VERSION 5.7 ;
BUSBITCHARS "[]" ;
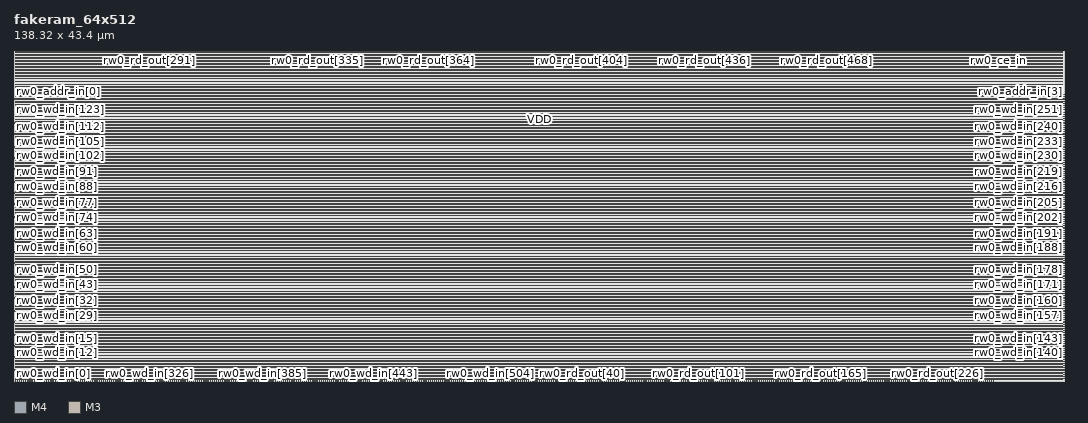
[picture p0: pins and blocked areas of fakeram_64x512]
MACRO fakeram_64x512
  FOREIGN fakeram_64x512 0 0 ;
  SYMMETRY X Y R90 ;
  SIZE 138.320 BY 43.400 ;
  CLASS BLOCK ;
  PIN rw0_wd_in[0]
    DIRECTION INPUT ;
    USE SIGNAL ;
    SHAPE ABUTMENT ;
    PORT
      LAYER M4 ;
      RECT 0.000 0.276 0.072 0.300 ;
    END
  END rw0_wd_in[0]
  PIN rw0_wd_in[1]
    DIRECTION INPUT ;
    USE SIGNAL ;
    SHAPE ABUTMENT ;
    PORT
      LAYER M4 ;
      RECT 0.000 0.564 0.072 0.588 ;
    END
  END rw0_wd_in[1]
  PIN rw0_wd_in[2]
    DIRECTION INPUT ;
    USE SIGNAL ;
    SHAPE ABUTMENT ;
    PORT
      LAYER M4 ;
      RECT 0.000 0.852 0.072 0.876 ;
    END
  END rw0_wd_in[2]
  PIN rw0_wd_in[3]
    DIRECTION INPUT ;
    USE SIGNAL ;
    SHAPE ABUTMENT ;
    PORT
      LAYER M4 ;
      RECT 0.000 1.140 0.072 1.164 ;
    END
  END rw0_wd_in[3]
  PIN rw0_wd_in[4]
    DIRECTION INPUT ;
    USE SIGNAL ;
    SHAPE ABUTMENT ;
    PORT
      LAYER M4 ;
      RECT 0.000 1.428 0.072 1.452 ;
    END
  END rw0_wd_in[4]
  PIN rw0_wd_in[5]
    DIRECTION INPUT ;
    USE SIGNAL ;
    SHAPE ABUTMENT ;
    PORT
      LAYER M4 ;
      RECT 0.000 1.716 0.072 1.740 ;
    END
  END rw0_wd_in[5]
  PIN rw0_wd_in[6]
    DIRECTION INPUT ;
    USE SIGNAL ;
    SHAPE ABUTMENT ;
    PORT
      LAYER M4 ;
      RECT 0.000 2.004 0.072 2.028 ;
    END
  END rw0_wd_in[6]
  PIN rw0_wd_in[7]
    DIRECTION INPUT ;
    USE SIGNAL ;
    SHAPE ABUTMENT ;
    PORT
      LAYER M4 ;
      RECT 0.000 2.292 0.072 2.316 ;
    END
  END rw0_wd_in[7]
  PIN rw0_wd_in[8]
    DIRECTION INPUT ;
    USE SIGNAL ;
    SHAPE ABUTMENT ;
    PORT
      LAYER M4 ;
      RECT 0.000 2.580 0.072 2.604 ;
    END
  END rw0_wd_in[8]
  PIN rw0_wd_in[9]
    DIRECTION INPUT ;
    USE SIGNAL ;
    SHAPE ABUTMENT ;
    PORT
      LAYER M4 ;
      RECT 0.000 2.868 0.072 2.892 ;
    END
  END rw0_wd_in[9]
  PIN rw0_wd_in[10]
    DIRECTION INPUT ;
    USE SIGNAL ;
    SHAPE ABUTMENT ;
    PORT
      LAYER M4 ;
      RECT 0.000 3.156 0.072 3.180 ;
    END
  END rw0_wd_in[10]
  PIN rw0_wd_in[11]
    DIRECTION INPUT ;
    USE SIGNAL ;
    SHAPE ABUTMENT ;
    PORT
      LAYER M4 ;
      RECT 0.000 3.444 0.072 3.468 ;
    END
  END rw0_wd_in[11]
  PIN rw0_wd_in[12]
    DIRECTION INPUT ;
    USE SIGNAL ;
    SHAPE ABUTMENT ;
    PORT
      LAYER M4 ;
      RECT 0.000 3.732 0.072 3.756 ;
    END
  END rw0_wd_in[12]
  PIN rw0_wd_in[13]
    DIRECTION INPUT ;
    USE SIGNAL ;
    SHAPE ABUTMENT ;
    PORT
      LAYER M4 ;
      RECT 0.000 4.020 0.072 4.044 ;
    END
  END rw0_wd_in[13]
  PIN rw0_wd_in[14]
    DIRECTION INPUT ;
    USE SIGNAL ;
    SHAPE ABUTMENT ;
    PORT
      LAYER M4 ;
      RECT 0.000 4.308 0.072 4.332 ;
    END
  END rw0_wd_in[14]
  PIN rw0_wd_in[15]
    DIRECTION INPUT ;
    USE SIGNAL ;
    SHAPE ABUTMENT ;
    PORT
      LAYER M4 ;
      RECT 0.000 4.596 0.072 4.620 ;
    END
  END rw0_wd_in[15]
  PIN rw0_wd_in[16]
    DIRECTION INPUT ;
    USE SIGNAL ;
    SHAPE ABUTMENT ;
    PORT
      LAYER M4 ;
      RECT 0.000 4.884 0.072 4.908 ;
    END
  END rw0_wd_in[16]
  PIN rw0_wd_in[17]
    DIRECTION INPUT ;
    USE SIGNAL ;
    SHAPE ABUTMENT ;
    PORT
      LAYER M4 ;
      RECT 0.000 5.172 0.072 5.196 ;
    END
  END rw0_wd_in[17]
  PIN rw0_wd_in[18]
    DIRECTION INPUT ;
    USE SIGNAL ;
    SHAPE ABUTMENT ;
    PORT
      LAYER M4 ;
      RECT 0.000 5.460 0.072 5.484 ;
    END
  END rw0_wd_in[18]
  PIN rw0_wd_in[19]
    DIRECTION INPUT ;
    USE SIGNAL ;
    SHAPE ABUTMENT ;
    PORT
      LAYER M4 ;
      RECT 0.000 5.748 0.072 5.772 ;
    END
  END rw0_wd_in[19]
  PIN rw0_wd_in[20]
    DIRECTION INPUT ;
    USE SIGNAL ;
    SHAPE ABUTMENT ;
    PORT
      LAYER M4 ;
      RECT 0.000 6.036 0.072 6.060 ;
    END
  END rw0_wd_in[20]
  PIN rw0_wd_in[21]
    DIRECTION INPUT ;
    USE SIGNAL ;
    SHAPE ABUTMENT ;
    PORT
      LAYER M4 ;
      RECT 0.000 6.324 0.072 6.348 ;
    END
  END rw0_wd_in[21]
  PIN rw0_wd_in[22]
    DIRECTION INPUT ;
    USE SIGNAL ;
    SHAPE ABUTMENT ;
    PORT
      LAYER M4 ;
      RECT 0.000 6.612 0.072 6.636 ;
    END
  END rw0_wd_in[22]
  PIN rw0_wd_in[23]
    DIRECTION INPUT ;
    USE SIGNAL ;
    SHAPE ABUTMENT ;
    PORT
      LAYER M4 ;
      RECT 0.000 6.900 0.072 6.924 ;
    END
  END rw0_wd_in[23]
  PIN rw0_wd_in[24]
    DIRECTION INPUT ;
    USE SIGNAL ;
    SHAPE ABUTMENT ;
    PORT
      LAYER M4 ;
      RECT 0.000 7.188 0.072 7.212 ;
    END
  END rw0_wd_in[24]
  PIN rw0_wd_in[25]
    DIRECTION INPUT ;
    USE SIGNAL ;
    SHAPE ABUTMENT ;
    PORT
      LAYER M4 ;
      RECT 0.000 7.476 0.072 7.500 ;
    END
  END rw0_wd_in[25]
  PIN rw0_wd_in[26]
    DIRECTION INPUT ;
    USE SIGNAL ;
    SHAPE ABUTMENT ;
    PORT
      LAYER M4 ;
      RECT 0.000 7.764 0.072 7.788 ;
    END
  END rw0_wd_in[26]
  PIN rw0_wd_in[27]
    DIRECTION INPUT ;
    USE SIGNAL ;
    SHAPE ABUTMENT ;
    PORT
      LAYER M4 ;
      RECT 0.000 8.052 0.072 8.076 ;
    END
  END rw0_wd_in[27]
  PIN rw0_wd_in[28]
    DIRECTION INPUT ;
    USE SIGNAL ;
    SHAPE ABUTMENT ;
    PORT
      LAYER M4 ;
      RECT 0.000 8.340 0.072 8.364 ;
    END
  END rw0_wd_in[28]
  PIN rw0_wd_in[29]
    DIRECTION INPUT ;
    USE SIGNAL ;
    SHAPE ABUTMENT ;
    PORT
      LAYER M4 ;
      RECT 0.000 8.628 0.072 8.652 ;
    END
  END rw0_wd_in[29]
  PIN rw0_wd_in[30]
    DIRECTION INPUT ;
    USE SIGNAL ;
    SHAPE ABUTMENT ;
    PORT
      LAYER M4 ;
      RECT 0.000 8.916 0.072 8.940 ;
    END
  END rw0_wd_in[30]
  PIN rw0_wd_in[31]
    DIRECTION INPUT ;
    USE SIGNAL ;
    SHAPE ABUTMENT ;
    PORT
      LAYER M4 ;
      RECT 0.000 9.204 0.072 9.228 ;
    END
  END rw0_wd_in[31]
  PIN rw0_wd_in[32]
    DIRECTION INPUT ;
    USE SIGNAL ;
    SHAPE ABUTMENT ;
    PORT
      LAYER M4 ;
      RECT 0.000 9.492 0.072 9.516 ;
    END
  END rw0_wd_in[32]
  PIN rw0_wd_in[33]
    DIRECTION INPUT ;
    USE SIGNAL ;
    SHAPE ABUTMENT ;
    PORT
      LAYER M4 ;
      RECT 0.000 9.780 0.072 9.804 ;
    END
  END rw0_wd_in[33]
  PIN rw0_wd_in[34]
    DIRECTION INPUT ;
    USE SIGNAL ;
    SHAPE ABUTMENT ;
    PORT
      LAYER M4 ;
      RECT 0.000 10.068 0.072 10.092 ;
    END
  END rw0_wd_in[34]
  PIN rw0_wd_in[35]
    DIRECTION INPUT ;
    USE SIGNAL ;
    SHAPE ABUTMENT ;
    PORT
      LAYER M4 ;
      RECT 0.000 10.356 0.072 10.380 ;
    END
  END rw0_wd_in[35]
  PIN rw0_wd_in[36]
    DIRECTION INPUT ;
    USE SIGNAL ;
    SHAPE ABUTMENT ;
    PORT
      LAYER M4 ;
      RECT 0.000 10.644 0.072 10.668 ;
    END
  END rw0_wd_in[36]
  PIN rw0_wd_in[37]
    DIRECTION INPUT ;
    USE SIGNAL ;
    SHAPE ABUTMENT ;
    PORT
      LAYER M4 ;
      RECT 0.000 10.932 0.072 10.956 ;
    END
  END rw0_wd_in[37]
  PIN rw0_wd_in[38]
    DIRECTION INPUT ;
    USE SIGNAL ;
    SHAPE ABUTMENT ;
    PORT
      LAYER M4 ;
      RECT 0.000 11.220 0.072 11.244 ;
    END
  END rw0_wd_in[38]
  PIN rw0_wd_in[39]
    DIRECTION INPUT ;
    USE SIGNAL ;
    SHAPE ABUTMENT ;
    PORT
      LAYER M4 ;
      RECT 0.000 11.508 0.072 11.532 ;
    END
  END rw0_wd_in[39]
  PIN rw0_wd_in[40]
    DIRECTION INPUT ;
    USE SIGNAL ;
    SHAPE ABUTMENT ;
    PORT
      LAYER M4 ;
      RECT 0.000 11.796 0.072 11.820 ;
    END
  END rw0_wd_in[40]
  PIN rw0_wd_in[41]
    DIRECTION INPUT ;
    USE SIGNAL ;
    SHAPE ABUTMENT ;
    PORT
      LAYER M4 ;
      RECT 0.000 12.084 0.072 12.108 ;
    END
  END rw0_wd_in[41]
  PIN rw0_wd_in[42]
    DIRECTION INPUT ;
    USE SIGNAL ;
    SHAPE ABUTMENT ;
    PORT
      LAYER M4 ;
      RECT 0.000 12.372 0.072 12.396 ;
    END
  END rw0_wd_in[42]
  PIN rw0_wd_in[43]
    DIRECTION INPUT ;
    USE SIGNAL ;
    SHAPE ABUTMENT ;
    PORT
      LAYER M4 ;
      RECT 0.000 12.660 0.072 12.684 ;
    END
  END rw0_wd_in[43]
  PIN rw0_wd_in[44]
    DIRECTION INPUT ;
    USE SIGNAL ;
    SHAPE ABUTMENT ;
    PORT
      LAYER M4 ;
      RECT 0.000 12.948 0.072 12.972 ;
    END
  END rw0_wd_in[44]
  PIN rw0_wd_in[45]
    DIRECTION INPUT ;
    USE SIGNAL ;
    SHAPE ABUTMENT ;
    PORT
      LAYER M4 ;
      RECT 0.000 13.236 0.072 13.260 ;
    END
  END rw0_wd_in[45]
  PIN rw0_wd_in[46]
    DIRECTION INPUT ;
    USE SIGNAL ;
    SHAPE ABUTMENT ;
    PORT
      LAYER M4 ;
      RECT 0.000 13.524 0.072 13.548 ;
    END
  END rw0_wd_in[46]
  PIN rw0_wd_in[47]
    DIRECTION INPUT ;
    USE SIGNAL ;
    SHAPE ABUTMENT ;
    PORT
      LAYER M4 ;
      RECT 0.000 13.812 0.072 13.836 ;
    END
  END rw0_wd_in[47]
  PIN rw0_wd_in[48]
    DIRECTION INPUT ;
    USE SIGNAL ;
    SHAPE ABUTMENT ;
    PORT
      LAYER M4 ;
      RECT 0.000 14.100 0.072 14.124 ;
    END
  END rw0_wd_in[48]
  PIN rw0_wd_in[49]
    DIRECTION INPUT ;
    USE SIGNAL ;
    SHAPE ABUTMENT ;
    PORT
      LAYER M4 ;
      RECT 0.000 14.388 0.072 14.412 ;
    END
  END rw0_wd_in[49]
  PIN rw0_wd_in[50]
    DIRECTION INPUT ;
    USE SIGNAL ;
    SHAPE ABUTMENT ;
    PORT
      LAYER M4 ;
      RECT 0.000 14.676 0.072 14.700 ;
    END
  END rw0_wd_in[50]
  PIN rw0_wd_in[51]
    DIRECTION INPUT ;
    USE SIGNAL ;
    SHAPE ABUTMENT ;
    PORT
      LAYER M4 ;
      RECT 0.000 14.964 0.072 14.988 ;
    END
  END rw0_wd_in[51]
  PIN rw0_wd_in[52]
    DIRECTION INPUT ;
    USE SIGNAL ;
    SHAPE ABUTMENT ;
    PORT
      LAYER M4 ;
      RECT 0.000 15.252 0.072 15.276 ;
    END
  END rw0_wd_in[52]
  PIN rw0_wd_in[53]
    DIRECTION INPUT ;
    USE SIGNAL ;
    SHAPE ABUTMENT ;
    PORT
      LAYER M4 ;
      RECT 0.000 15.540 0.072 15.564 ;
    END
  END rw0_wd_in[53]
  PIN rw0_wd_in[54]
    DIRECTION INPUT ;
    USE SIGNAL ;
    SHAPE ABUTMENT ;
    PORT
      LAYER M4 ;
      RECT 0.000 15.828 0.072 15.852 ;
    END
  END rw0_wd_in[54]
  PIN rw0_wd_in[55]
    DIRECTION INPUT ;
    USE SIGNAL ;
    SHAPE ABUTMENT ;
    PORT
      LAYER M4 ;
      RECT 0.000 16.116 0.072 16.140 ;
    END
  END rw0_wd_in[55]
  PIN rw0_wd_in[56]
    DIRECTION INPUT ;
    USE SIGNAL ;
    SHAPE ABUTMENT ;
    PORT
      LAYER M4 ;
      RECT 0.000 16.404 0.072 16.428 ;
    END
  END rw0_wd_in[56]
  PIN rw0_wd_in[57]
    DIRECTION INPUT ;
    USE SIGNAL ;
    SHAPE ABUTMENT ;
    PORT
      LAYER M4 ;
      RECT 0.000 16.692 0.072 16.716 ;
    END
  END rw0_wd_in[57]
  PIN rw0_wd_in[58]
    DIRECTION INPUT ;
    USE SIGNAL ;
    SHAPE ABUTMENT ;
    PORT
      LAYER M4 ;
      RECT 0.000 16.980 0.072 17.004 ;
    END
  END rw0_wd_in[58]
  PIN rw0_wd_in[59]
    DIRECTION INPUT ;
    USE SIGNAL ;
    SHAPE ABUTMENT ;
    PORT
      LAYER M4 ;
      RECT 0.000 17.268 0.072 17.292 ;
    END
  END rw0_wd_in[59]
  PIN rw0_wd_in[60]
    DIRECTION INPUT ;
    USE SIGNAL ;
    SHAPE ABUTMENT ;
    PORT
      LAYER M4 ;
      RECT 0.000 17.556 0.072 17.580 ;
    END
  END rw0_wd_in[60]
  PIN rw0_wd_in[61]
    DIRECTION INPUT ;
    USE SIGNAL ;
    SHAPE ABUTMENT ;
    PORT
      LAYER M4 ;
      RECT 0.000 17.844 0.072 17.868 ;
    END
  END rw0_wd_in[61]
  PIN rw0_wd_in[62]
    DIRECTION INPUT ;
    USE SIGNAL ;
    SHAPE ABUTMENT ;
    PORT
      LAYER M4 ;
      RECT 0.000 18.132 0.072 18.156 ;
    END
  END rw0_wd_in[62]
  PIN rw0_wd_in[63]
    DIRECTION INPUT ;
    USE SIGNAL ;
    SHAPE ABUTMENT ;
    PORT
      LAYER M4 ;
      RECT 0.000 18.420 0.072 18.444 ;
    END
  END rw0_wd_in[63]
  PIN rw0_wd_in[64]
    DIRECTION INPUT ;
    USE SIGNAL ;
    SHAPE ABUTMENT ;
    PORT
      LAYER M4 ;
      RECT 0.000 18.708 0.072 18.732 ;
    END
  END rw0_wd_in[64]
  PIN rw0_wd_in[65]
    DIRECTION INPUT ;
    USE SIGNAL ;
    SHAPE ABUTMENT ;
    PORT
      LAYER M4 ;
      RECT 0.000 18.996 0.072 19.020 ;
    END
  END rw0_wd_in[65]
  PIN rw0_wd_in[66]
    DIRECTION INPUT ;
    USE SIGNAL ;
    SHAPE ABUTMENT ;
    PORT
      LAYER M4 ;
      RECT 0.000 19.284 0.072 19.308 ;
    END
  END rw0_wd_in[66]
  PIN rw0_wd_in[67]
    DIRECTION INPUT ;
    USE SIGNAL ;
    SHAPE ABUTMENT ;
    PORT
      LAYER M4 ;
      RECT 0.000 19.572 0.072 19.596 ;
    END
  END rw0_wd_in[67]
  PIN rw0_wd_in[68]
    DIRECTION INPUT ;
    USE SIGNAL ;
    SHAPE ABUTMENT ;
    PORT
      LAYER M4 ;
      RECT 0.000 19.860 0.072 19.884 ;
    END
  END rw0_wd_in[68]
  PIN rw0_wd_in[69]
    DIRECTION INPUT ;
    USE SIGNAL ;
    SHAPE ABUTMENT ;
    PORT
      LAYER M4 ;
      RECT 0.000 20.148 0.072 20.172 ;
    END
  END rw0_wd_in[69]
  PIN rw0_wd_in[70]
    DIRECTION INPUT ;
    USE SIGNAL ;
    SHAPE ABUTMENT ;
    PORT
      LAYER M4 ;
      RECT 0.000 20.436 0.072 20.460 ;
    END
  END rw0_wd_in[70]
  PIN rw0_wd_in[71]
    DIRECTION INPUT ;
    USE SIGNAL ;
    SHAPE ABUTMENT ;
    PORT
      LAYER M4 ;
      RECT 0.000 20.724 0.072 20.748 ;
    END
  END rw0_wd_in[71]
  PIN rw0_wd_in[72]
    DIRECTION INPUT ;
    USE SIGNAL ;
    SHAPE ABUTMENT ;
    PORT
      LAYER M4 ;
      RECT 0.000 21.012 0.072 21.036 ;
    END
  END rw0_wd_in[72]
  PIN rw0_wd_in[73]
    DIRECTION INPUT ;
    USE SIGNAL ;
    SHAPE ABUTMENT ;
    PORT
      LAYER M4 ;
      RECT 0.000 21.300 0.072 21.324 ;
    END
  END rw0_wd_in[73]
  PIN rw0_wd_in[74]
    DIRECTION INPUT ;
    USE SIGNAL ;
    SHAPE ABUTMENT ;
    PORT
      LAYER M4 ;
      RECT 0.000 21.588 0.072 21.612 ;
    END
  END rw0_wd_in[74]
  PIN rw0_wd_in[75]
    DIRECTION INPUT ;
    USE SIGNAL ;
    SHAPE ABUTMENT ;
    PORT
      LAYER M4 ;
      RECT 0.000 21.876 0.072 21.900 ;
    END
  END rw0_wd_in[75]
  PIN rw0_wd_in[76]
    DIRECTION INPUT ;
    USE SIGNAL ;
    SHAPE ABUTMENT ;
    PORT
      LAYER M4 ;
      RECT 0.000 22.164 0.072 22.188 ;
    END
  END rw0_wd_in[76]
  PIN rw0_wd_in[77]
    DIRECTION INPUT ;
    USE SIGNAL ;
    SHAPE ABUTMENT ;
    PORT
      LAYER M4 ;
      RECT 0.000 22.452 0.072 22.476 ;
    END
  END rw0_wd_in[77]
  PIN rw0_wd_in[78]
    DIRECTION INPUT ;
    USE SIGNAL ;
    SHAPE ABUTMENT ;
    PORT
      LAYER M4 ;
      RECT 0.000 22.740 0.072 22.764 ;
    END
  END rw0_wd_in[78]
  PIN rw0_wd_in[79]
    DIRECTION INPUT ;
    USE SIGNAL ;
    SHAPE ABUTMENT ;
    PORT
      LAYER M4 ;
      RECT 0.000 23.028 0.072 23.052 ;
    END
  END rw0_wd_in[79]
  PIN rw0_wd_in[80]
    DIRECTION INPUT ;
    USE SIGNAL ;
    SHAPE ABUTMENT ;
    PORT
      LAYER M4 ;
      RECT 0.000 23.316 0.072 23.340 ;
    END
  END rw0_wd_in[80]
  PIN rw0_wd_in[81]
    DIRECTION INPUT ;
    USE SIGNAL ;
    SHAPE ABUTMENT ;
    PORT
      LAYER M4 ;
      RECT 0.000 23.604 0.072 23.628 ;
    END
  END rw0_wd_in[81]
  PIN rw0_wd_in[82]
    DIRECTION INPUT ;
    USE SIGNAL ;
    SHAPE ABUTMENT ;
    PORT
      LAYER M4 ;
      RECT 0.000 23.892 0.072 23.916 ;
    END
  END rw0_wd_in[82]
  PIN rw0_wd_in[83]
    DIRECTION INPUT ;
    USE SIGNAL ;
    SHAPE ABUTMENT ;
    PORT
      LAYER M4 ;
      RECT 0.000 24.180 0.072 24.204 ;
    END
  END rw0_wd_in[83]
  PIN rw0_wd_in[84]
    DIRECTION INPUT ;
    USE SIGNAL ;
    SHAPE ABUTMENT ;
    PORT
      LAYER M4 ;
      RECT 0.000 24.468 0.072 24.492 ;
    END
  END rw0_wd_in[84]
  PIN rw0_wd_in[85]
    DIRECTION INPUT ;
    USE SIGNAL ;
    SHAPE ABUTMENT ;
    PORT
      LAYER M4 ;
      RECT 0.000 24.756 0.072 24.780 ;
    END
  END rw0_wd_in[85]
  PIN rw0_wd_in[86]
    DIRECTION INPUT ;
    USE SIGNAL ;
    SHAPE ABUTMENT ;
    PORT
      LAYER M4 ;
      RECT 0.000 25.044 0.072 25.068 ;
    END
  END rw0_wd_in[86]
  PIN rw0_wd_in[87]
    DIRECTION INPUT ;
    USE SIGNAL ;
    SHAPE ABUTMENT ;
    PORT
      LAYER M4 ;
      RECT 0.000 25.332 0.072 25.356 ;
    END
  END rw0_wd_in[87]
  PIN rw0_wd_in[88]
    DIRECTION INPUT ;
    USE SIGNAL ;
    SHAPE ABUTMENT ;
    PORT
      LAYER M4 ;
      RECT 0.000 25.620 0.072 25.644 ;
    END
  END rw0_wd_in[88]
  PIN rw0_wd_in[89]
    DIRECTION INPUT ;
    USE SIGNAL ;
    SHAPE ABUTMENT ;
    PORT
      LAYER M4 ;
      RECT 0.000 25.908 0.072 25.932 ;
    END
  END rw0_wd_in[89]
  PIN rw0_wd_in[90]
    DIRECTION INPUT ;
    USE SIGNAL ;
    SHAPE ABUTMENT ;
    PORT
      LAYER M4 ;
      RECT 0.000 26.196 0.072 26.220 ;
    END
  END rw0_wd_in[90]
  PIN rw0_wd_in[91]
    DIRECTION INPUT ;
    USE SIGNAL ;
    SHAPE ABUTMENT ;
    PORT
      LAYER M4 ;
      RECT 0.000 26.484 0.072 26.508 ;
    END
  END rw0_wd_in[91]
  PIN rw0_wd_in[92]
    DIRECTION INPUT ;
    USE SIGNAL ;
    SHAPE ABUTMENT ;
    PORT
      LAYER M4 ;
      RECT 0.000 26.772 0.072 26.796 ;
    END
  END rw0_wd_in[92]
  PIN rw0_wd_in[93]
    DIRECTION INPUT ;
    USE SIGNAL ;
    SHAPE ABUTMENT ;
    PORT
      LAYER M4 ;
      RECT 0.000 27.060 0.072 27.084 ;
    END
  END rw0_wd_in[93]
  PIN rw0_wd_in[94]
    DIRECTION INPUT ;
    USE SIGNAL ;
    SHAPE ABUTMENT ;
    PORT
      LAYER M4 ;
      RECT 0.000 27.348 0.072 27.372 ;
    END
  END rw0_wd_in[94]
  PIN rw0_wd_in[95]
    DIRECTION INPUT ;
    USE SIGNAL ;
    SHAPE ABUTMENT ;
    PORT
      LAYER M4 ;
      RECT 0.000 27.636 0.072 27.660 ;
    END
  END rw0_wd_in[95]
  PIN rw0_wd_in[96]
    DIRECTION INPUT ;
    USE SIGNAL ;
    SHAPE ABUTMENT ;
    PORT
      LAYER M4 ;
      RECT 0.000 27.924 0.072 27.948 ;
    END
  END rw0_wd_in[96]
  PIN rw0_wd_in[97]
    DIRECTION INPUT ;
    USE SIGNAL ;
    SHAPE ABUTMENT ;
    PORT
      LAYER M4 ;
      RECT 0.000 28.212 0.072 28.236 ;
    END
  END rw0_wd_in[97]
  PIN rw0_wd_in[98]
    DIRECTION INPUT ;
    USE SIGNAL ;
    SHAPE ABUTMENT ;
    PORT
      LAYER M4 ;
      RECT 0.000 28.500 0.072 28.524 ;
    END
  END rw0_wd_in[98]
  PIN rw0_wd_in[99]
    DIRECTION INPUT ;
    USE SIGNAL ;
    SHAPE ABUTMENT ;
    PORT
      LAYER M4 ;
      RECT 0.000 28.788 0.072 28.812 ;
    END
  END rw0_wd_in[99]
  PIN rw0_wd_in[100]
    DIRECTION INPUT ;
    USE SIGNAL ;
    SHAPE ABUTMENT ;
    PORT
      LAYER M4 ;
      RECT 0.000 29.076 0.072 29.100 ;
    END
  END rw0_wd_in[100]
  PIN rw0_wd_in[101]
    DIRECTION INPUT ;
    USE SIGNAL ;
    SHAPE ABUTMENT ;
    PORT
      LAYER M4 ;
      RECT 0.000 29.364 0.072 29.388 ;
    END
  END rw0_wd_in[101]
  PIN rw0_wd_in[102]
    DIRECTION INPUT ;
    USE SIGNAL ;
    SHAPE ABUTMENT ;
    PORT
      LAYER M4 ;
      RECT 0.000 29.652 0.072 29.676 ;
    END
  END rw0_wd_in[102]
  PIN rw0_wd_in[103]
    DIRECTION INPUT ;
    USE SIGNAL ;
    SHAPE ABUTMENT ;
    PORT
      LAYER M4 ;
      RECT 0.000 29.940 0.072 29.964 ;
    END
  END rw0_wd_in[103]
  PIN rw0_wd_in[104]
    DIRECTION INPUT ;
    USE SIGNAL ;
    SHAPE ABUTMENT ;
    PORT
      LAYER M4 ;
      RECT 0.000 30.228 0.072 30.252 ;
    END
  END rw0_wd_in[104]
  PIN rw0_wd_in[105]
    DIRECTION INPUT ;
    USE SIGNAL ;
    SHAPE ABUTMENT ;
    PORT
      LAYER M4 ;
      RECT 0.000 30.516 0.072 30.540 ;
    END
  END rw0_wd_in[105]
  PIN rw0_wd_in[106]
    DIRECTION INPUT ;
    USE SIGNAL ;
    SHAPE ABUTMENT ;
    PORT
      LAYER M4 ;
      RECT 0.000 30.804 0.072 30.828 ;
    END
  END rw0_wd_in[106]
  PIN rw0_wd_in[107]
    DIRECTION INPUT ;
    USE SIGNAL ;
    SHAPE ABUTMENT ;
    PORT
      LAYER M4 ;
      RECT 0.000 31.092 0.072 31.116 ;
    END
  END rw0_wd_in[107]
  PIN rw0_wd_in[108]
    DIRECTION INPUT ;
    USE SIGNAL ;
    SHAPE ABUTMENT ;
    PORT
      LAYER M4 ;
      RECT 0.000 31.380 0.072 31.404 ;
    END
  END rw0_wd_in[108]
  PIN rw0_wd_in[109]
    DIRECTION INPUT ;
    USE SIGNAL ;
    SHAPE ABUTMENT ;
    PORT
      LAYER M4 ;
      RECT 0.000 31.668 0.072 31.692 ;
    END
  END rw0_wd_in[109]
  PIN rw0_wd_in[110]
    DIRECTION INPUT ;
    USE SIGNAL ;
    SHAPE ABUTMENT ;
    PORT
      LAYER M4 ;
      RECT 0.000 31.956 0.072 31.980 ;
    END
  END rw0_wd_in[110]
  PIN rw0_wd_in[111]
    DIRECTION INPUT ;
    USE SIGNAL ;
    SHAPE ABUTMENT ;
    PORT
      LAYER M4 ;
      RECT 0.000 32.244 0.072 32.268 ;
    END
  END rw0_wd_in[111]
  PIN rw0_wd_in[112]
    DIRECTION INPUT ;
    USE SIGNAL ;
    SHAPE ABUTMENT ;
    PORT
      LAYER M4 ;
      RECT 0.000 32.532 0.072 32.556 ;
    END
  END rw0_wd_in[112]
  PIN rw0_wd_in[113]
    DIRECTION INPUT ;
    USE SIGNAL ;
    SHAPE ABUTMENT ;
    PORT
      LAYER M4 ;
      RECT 0.000 32.820 0.072 32.844 ;
    END
  END rw0_wd_in[113]
  PIN rw0_wd_in[114]
    DIRECTION INPUT ;
    USE SIGNAL ;
    SHAPE ABUTMENT ;
    PORT
      LAYER M4 ;
      RECT 0.000 33.108 0.072 33.132 ;
    END
  END rw0_wd_in[114]
  PIN rw0_wd_in[115]
    DIRECTION INPUT ;
    USE SIGNAL ;
    SHAPE ABUTMENT ;
    PORT
      LAYER M4 ;
      RECT 0.000 33.396 0.072 33.420 ;
    END
  END rw0_wd_in[115]
  PIN rw0_wd_in[116]
    DIRECTION INPUT ;
    USE SIGNAL ;
    SHAPE ABUTMENT ;
    PORT
      LAYER M4 ;
      RECT 0.000 33.684 0.072 33.708 ;
    END
  END rw0_wd_in[116]
  PIN rw0_wd_in[117]
    DIRECTION INPUT ;
    USE SIGNAL ;
    SHAPE ABUTMENT ;
    PORT
      LAYER M4 ;
      RECT 0.000 33.972 0.072 33.996 ;
    END
  END rw0_wd_in[117]
  PIN rw0_wd_in[118]
    DIRECTION INPUT ;
    USE SIGNAL ;
    SHAPE ABUTMENT ;
    PORT
      LAYER M4 ;
      RECT 0.000 34.260 0.072 34.284 ;
    END
  END rw0_wd_in[118]
  PIN rw0_wd_in[119]
    DIRECTION INPUT ;
    USE SIGNAL ;
    SHAPE ABUTMENT ;
    PORT
      LAYER M4 ;
      RECT 0.000 34.548 0.072 34.572 ;
    END
  END rw0_wd_in[119]
  PIN rw0_wd_in[120]
    DIRECTION INPUT ;
    USE SIGNAL ;
    SHAPE ABUTMENT ;
    PORT
      LAYER M4 ;
      RECT 0.000 34.836 0.072 34.860 ;
    END
  END rw0_wd_in[120]
  PIN rw0_wd_in[121]
    DIRECTION INPUT ;
    USE SIGNAL ;
    SHAPE ABUTMENT ;
    PORT
      LAYER M4 ;
      RECT 0.000 35.124 0.072 35.148 ;
    END
  END rw0_wd_in[121]
  PIN rw0_wd_in[122]
    DIRECTION INPUT ;
    USE SIGNAL ;
    SHAPE ABUTMENT ;
    PORT
      LAYER M4 ;
      RECT 0.000 35.412 0.072 35.436 ;
    END
  END rw0_wd_in[122]
  PIN rw0_wd_in[123]
    DIRECTION INPUT ;
    USE SIGNAL ;
    SHAPE ABUTMENT ;
    PORT
      LAYER M4 ;
      RECT 0.000 35.700 0.072 35.724 ;
    END
  END rw0_wd_in[123]
  PIN rw0_wd_in[124]
    DIRECTION INPUT ;
    USE SIGNAL ;
    SHAPE ABUTMENT ;
    PORT
      LAYER M4 ;
      RECT 0.000 35.988 0.072 36.012 ;
    END
  END rw0_wd_in[124]
  PIN rw0_wd_in[125]
    DIRECTION INPUT ;
    USE SIGNAL ;
    SHAPE ABUTMENT ;
    PORT
      LAYER M4 ;
      RECT 0.000 36.276 0.072 36.300 ;
    END
  END rw0_wd_in[125]
  PIN rw0_wd_in[126]
    DIRECTION INPUT ;
    USE SIGNAL ;
    SHAPE ABUTMENT ;
    PORT
      LAYER M4 ;
      RECT 0.000 36.564 0.072 36.588 ;
    END
  END rw0_wd_in[126]
  PIN rw0_wd_in[127]
    DIRECTION INPUT ;
    USE SIGNAL ;
    SHAPE ABUTMENT ;
    PORT
      LAYER M4 ;
      RECT 0.000 36.852 0.072 36.876 ;
    END
  END rw0_wd_in[127]
  PIN rw0_wd_in[128]
    DIRECTION INPUT ;
    USE SIGNAL ;
    SHAPE ABUTMENT ;
    PORT
      LAYER M4 ;
      RECT 138.248 0.276 138.320 0.300 ;
    END
  END rw0_wd_in[128]
  PIN rw0_wd_in[129]
    DIRECTION INPUT ;
    USE SIGNAL ;
    SHAPE ABUTMENT ;
    PORT
      LAYER M4 ;
      RECT 138.248 0.564 138.320 0.588 ;
    END
  END rw0_wd_in[129]
  PIN rw0_wd_in[130]
    DIRECTION INPUT ;
    USE SIGNAL ;
    SHAPE ABUTMENT ;
    PORT
      LAYER M4 ;
      RECT 138.248 0.852 138.320 0.876 ;
    END
  END rw0_wd_in[130]
  PIN rw0_wd_in[131]
    DIRECTION INPUT ;
    USE SIGNAL ;
    SHAPE ABUTMENT ;
    PORT
      LAYER M4 ;
      RECT 138.248 1.140 138.320 1.164 ;
    END
  END rw0_wd_in[131]
  PIN rw0_wd_in[132]
    DIRECTION INPUT ;
    USE SIGNAL ;
    SHAPE ABUTMENT ;
    PORT
      LAYER M4 ;
      RECT 138.248 1.428 138.320 1.452 ;
    END
  END rw0_wd_in[132]
  PIN rw0_wd_in[133]
    DIRECTION INPUT ;
    USE SIGNAL ;
    SHAPE ABUTMENT ;
    PORT
      LAYER M4 ;
      RECT 138.248 1.716 138.320 1.740 ;
    END
  END rw0_wd_in[133]
  PIN rw0_wd_in[134]
    DIRECTION INPUT ;
    USE SIGNAL ;
    SHAPE ABUTMENT ;
    PORT
      LAYER M4 ;
      RECT 138.248 2.004 138.320 2.028 ;
    END
  END rw0_wd_in[134]
  PIN rw0_wd_in[135]
    DIRECTION INPUT ;
    USE SIGNAL ;
    SHAPE ABUTMENT ;
    PORT
      LAYER M4 ;
      RECT 138.248 2.292 138.320 2.316 ;
    END
  END rw0_wd_in[135]
  PIN rw0_wd_in[136]
    DIRECTION INPUT ;
    USE SIGNAL ;
    SHAPE ABUTMENT ;
    PORT
      LAYER M4 ;
      RECT 138.248 2.580 138.320 2.604 ;
    END
  END rw0_wd_in[136]
  PIN rw0_wd_in[137]
    DIRECTION INPUT ;
    USE SIGNAL ;
    SHAPE ABUTMENT ;
    PORT
      LAYER M4 ;
      RECT 138.248 2.868 138.320 2.892 ;
    END
  END rw0_wd_in[137]
  PIN rw0_wd_in[138]
    DIRECTION INPUT ;
    USE SIGNAL ;
    SHAPE ABUTMENT ;
    PORT
      LAYER M4 ;
      RECT 138.248 3.156 138.320 3.180 ;
    END
  END rw0_wd_in[138]
  PIN rw0_wd_in[139]
    DIRECTION INPUT ;
    USE SIGNAL ;
    SHAPE ABUTMENT ;
    PORT
      LAYER M4 ;
      RECT 138.248 3.444 138.320 3.468 ;
    END
  END rw0_wd_in[139]
  PIN rw0_wd_in[140]
    DIRECTION INPUT ;
    USE SIGNAL ;
    SHAPE ABUTMENT ;
    PORT
      LAYER M4 ;
      RECT 138.248 3.732 138.320 3.756 ;
    END
  END rw0_wd_in[140]
  PIN rw0_wd_in[141]
    DIRECTION INPUT ;
    USE SIGNAL ;
    SHAPE ABUTMENT ;
    PORT
      LAYER M4 ;
      RECT 138.248 4.020 138.320 4.044 ;
    END
  END rw0_wd_in[141]
  PIN rw0_wd_in[142]
    DIRECTION INPUT ;
    USE SIGNAL ;
    SHAPE ABUTMENT ;
    PORT
      LAYER M4 ;
      RECT 138.248 4.308 138.320 4.332 ;
    END
  END rw0_wd_in[142]
  PIN rw0_wd_in[143]
    DIRECTION INPUT ;
    USE SIGNAL ;
    SHAPE ABUTMENT ;
    PORT
      LAYER M4 ;
      RECT 138.248 4.596 138.320 4.620 ;
    END
  END rw0_wd_in[143]
  PIN rw0_wd_in[144]
    DIRECTION INPUT ;
    USE SIGNAL ;
    SHAPE ABUTMENT ;
    PORT
      LAYER M4 ;
      RECT 138.248 4.884 138.320 4.908 ;
    END
  END rw0_wd_in[144]
  PIN rw0_wd_in[145]
    DIRECTION INPUT ;
    USE SIGNAL ;
    SHAPE ABUTMENT ;
    PORT
      LAYER M4 ;
      RECT 138.248 5.172 138.320 5.196 ;
    END
  END rw0_wd_in[145]
  PIN rw0_wd_in[146]
    DIRECTION INPUT ;
    USE SIGNAL ;
    SHAPE ABUTMENT ;
    PORT
      LAYER M4 ;
      RECT 138.248 5.460 138.320 5.484 ;
    END
  END rw0_wd_in[146]
  PIN rw0_wd_in[147]
    DIRECTION INPUT ;
    USE SIGNAL ;
    SHAPE ABUTMENT ;
    PORT
      LAYER M4 ;
      RECT 138.248 5.748 138.320 5.772 ;
    END
  END rw0_wd_in[147]
  PIN rw0_wd_in[148]
    DIRECTION INPUT ;
    USE SIGNAL ;
    SHAPE ABUTMENT ;
    PORT
      LAYER M4 ;
      RECT 138.248 6.036 138.320 6.060 ;
    END
  END rw0_wd_in[148]
  PIN rw0_wd_in[149]
    DIRECTION INPUT ;
    USE SIGNAL ;
    SHAPE ABUTMENT ;
    PORT
      LAYER M4 ;
      RECT 138.248 6.324 138.320 6.348 ;
    END
  END rw0_wd_in[149]
  PIN rw0_wd_in[150]
    DIRECTION INPUT ;
    USE SIGNAL ;
    SHAPE ABUTMENT ;
    PORT
      LAYER M4 ;
      RECT 138.248 6.612 138.320 6.636 ;
    END
  END rw0_wd_in[150]
  PIN rw0_wd_in[151]
    DIRECTION INPUT ;
    USE SIGNAL ;
    SHAPE ABUTMENT ;
    PORT
      LAYER M4 ;
      RECT 138.248 6.900 138.320 6.924 ;
    END
  END rw0_wd_in[151]
  PIN rw0_wd_in[152]
    DIRECTION INPUT ;
    USE SIGNAL ;
    SHAPE ABUTMENT ;
    PORT
      LAYER M4 ;
      RECT 138.248 7.188 138.320 7.212 ;
    END
  END rw0_wd_in[152]
  PIN rw0_wd_in[153]
    DIRECTION INPUT ;
    USE SIGNAL ;
    SHAPE ABUTMENT ;
    PORT
      LAYER M4 ;
      RECT 138.248 7.476 138.320 7.500 ;
    END
  END rw0_wd_in[153]
  PIN rw0_wd_in[154]
    DIRECTION INPUT ;
    USE SIGNAL ;
    SHAPE ABUTMENT ;
    PORT
      LAYER M4 ;
      RECT 138.248 7.764 138.320 7.788 ;
    END
  END rw0_wd_in[154]
  PIN rw0_wd_in[155]
    DIRECTION INPUT ;
    USE SIGNAL ;
    SHAPE ABUTMENT ;
    PORT
      LAYER M4 ;
      RECT 138.248 8.052 138.320 8.076 ;
    END
  END rw0_wd_in[155]
  PIN rw0_wd_in[156]
    DIRECTION INPUT ;
    USE SIGNAL ;
    SHAPE ABUTMENT ;
    PORT
      LAYER M4 ;
      RECT 138.248 8.340 138.320 8.364 ;
    END
  END rw0_wd_in[156]
  PIN rw0_wd_in[157]
    DIRECTION INPUT ;
    USE SIGNAL ;
    SHAPE ABUTMENT ;
    PORT
      LAYER M4 ;
      RECT 138.248 8.628 138.320 8.652 ;
    END
  END rw0_wd_in[157]
  PIN rw0_wd_in[158]
    DIRECTION INPUT ;
    USE SIGNAL ;
    SHAPE ABUTMENT ;
    PORT
      LAYER M4 ;
      RECT 138.248 8.916 138.320 8.940 ;
    END
  END rw0_wd_in[158]
  PIN rw0_wd_in[159]
    DIRECTION INPUT ;
    USE SIGNAL ;
    SHAPE ABUTMENT ;
    PORT
      LAYER M4 ;
      RECT 138.248 9.204 138.320 9.228 ;
    END
  END rw0_wd_in[159]
  PIN rw0_wd_in[160]
    DIRECTION INPUT ;
    USE SIGNAL ;
    SHAPE ABUTMENT ;
    PORT
      LAYER M4 ;
      RECT 138.248 9.492 138.320 9.516 ;
    END
  END rw0_wd_in[160]
  PIN rw0_wd_in[161]
    DIRECTION INPUT ;
    USE SIGNAL ;
    SHAPE ABUTMENT ;
    PORT
      LAYER M4 ;
      RECT 138.248 9.780 138.320 9.804 ;
    END
  END rw0_wd_in[161]
  PIN rw0_wd_in[162]
    DIRECTION INPUT ;
    USE SIGNAL ;
    SHAPE ABUTMENT ;
    PORT
      LAYER M4 ;
      RECT 138.248 10.068 138.320 10.092 ;
    END
  END rw0_wd_in[162]
  PIN rw0_wd_in[163]
    DIRECTION INPUT ;
    USE SIGNAL ;
    SHAPE ABUTMENT ;
    PORT
      LAYER M4 ;
      RECT 138.248 10.356 138.320 10.380 ;
    END
  END rw0_wd_in[163]
  PIN rw0_wd_in[164]
    DIRECTION INPUT ;
    USE SIGNAL ;
    SHAPE ABUTMENT ;
    PORT
      LAYER M4 ;
      RECT 138.248 10.644 138.320 10.668 ;
    END
  END rw0_wd_in[164]
  PIN rw0_wd_in[165]
    DIRECTION INPUT ;
    USE SIGNAL ;
    SHAPE ABUTMENT ;
    PORT
      LAYER M4 ;
      RECT 138.248 10.932 138.320 10.956 ;
    END
  END rw0_wd_in[165]
  PIN rw0_wd_in[166]
    DIRECTION INPUT ;
    USE SIGNAL ;
    SHAPE ABUTMENT ;
    PORT
      LAYER M4 ;
      RECT 138.248 11.220 138.320 11.244 ;
    END
  END rw0_wd_in[166]
  PIN rw0_wd_in[167]
    DIRECTION INPUT ;
    USE SIGNAL ;
    SHAPE ABUTMENT ;
    PORT
      LAYER M4 ;
      RECT 138.248 11.508 138.320 11.532 ;
    END
  END rw0_wd_in[167]
  PIN rw0_wd_in[168]
    DIRECTION INPUT ;
    USE SIGNAL ;
    SHAPE ABUTMENT ;
    PORT
      LAYER M4 ;
      RECT 138.248 11.796 138.320 11.820 ;
    END
  END rw0_wd_in[168]
  PIN rw0_wd_in[169]
    DIRECTION INPUT ;
    USE SIGNAL ;
    SHAPE ABUTMENT ;
    PORT
      LAYER M4 ;
      RECT 138.248 12.084 138.320 12.108 ;
    END
  END rw0_wd_in[169]
  PIN rw0_wd_in[170]
    DIRECTION INPUT ;
    USE SIGNAL ;
    SHAPE ABUTMENT ;
    PORT
      LAYER M4 ;
      RECT 138.248 12.372 138.320 12.396 ;
    END
  END rw0_wd_in[170]
  PIN rw0_wd_in[171]
    DIRECTION INPUT ;
    USE SIGNAL ;
    SHAPE ABUTMENT ;
    PORT
      LAYER M4 ;
      RECT 138.248 12.660 138.320 12.684 ;
    END
  END rw0_wd_in[171]
  PIN rw0_wd_in[172]
    DIRECTION INPUT ;
    USE SIGNAL ;
    SHAPE ABUTMENT ;
    PORT
      LAYER M4 ;
      RECT 138.248 12.948 138.320 12.972 ;
    END
  END rw0_wd_in[172]
  PIN rw0_wd_in[173]
    DIRECTION INPUT ;
    USE SIGNAL ;
    SHAPE ABUTMENT ;
    PORT
      LAYER M4 ;
      RECT 138.248 13.236 138.320 13.260 ;
    END
  END rw0_wd_in[173]
  PIN rw0_wd_in[174]
    DIRECTION INPUT ;
    USE SIGNAL ;
    SHAPE ABUTMENT ;
    PORT
      LAYER M4 ;
      RECT 138.248 13.524 138.320 13.548 ;
    END
  END rw0_wd_in[174]
  PIN rw0_wd_in[175]
    DIRECTION INPUT ;
    USE SIGNAL ;
    SHAPE ABUTMENT ;
    PORT
      LAYER M4 ;
      RECT 138.248 13.812 138.320 13.836 ;
    END
  END rw0_wd_in[175]
  PIN rw0_wd_in[176]
    DIRECTION INPUT ;
    USE SIGNAL ;
    SHAPE ABUTMENT ;
    PORT
      LAYER M4 ;
      RECT 138.248 14.100 138.320 14.124 ;
    END
  END rw0_wd_in[176]
  PIN rw0_wd_in[177]
    DIRECTION INPUT ;
    USE SIGNAL ;
    SHAPE ABUTMENT ;
    PORT
      LAYER M4 ;
      RECT 138.248 14.388 138.320 14.412 ;
    END
  END rw0_wd_in[177]
  PIN rw0_wd_in[178]
    DIRECTION INPUT ;
    USE SIGNAL ;
    SHAPE ABUTMENT ;
    PORT
      LAYER M4 ;
      RECT 138.248 14.676 138.320 14.700 ;
    END
  END rw0_wd_in[178]
  PIN rw0_wd_in[179]
    DIRECTION INPUT ;
    USE SIGNAL ;
    SHAPE ABUTMENT ;
    PORT
      LAYER M4 ;
      RECT 138.248 14.964 138.320 14.988 ;
    END
  END rw0_wd_in[179]
  PIN rw0_wd_in[180]
    DIRECTION INPUT ;
    USE SIGNAL ;
    SHAPE ABUTMENT ;
    PORT
      LAYER M4 ;
      RECT 138.248 15.252 138.320 15.276 ;
    END
  END rw0_wd_in[180]
  PIN rw0_wd_in[181]
    DIRECTION INPUT ;
    USE SIGNAL ;
    SHAPE ABUTMENT ;
    PORT
      LAYER M4 ;
      RECT 138.248 15.540 138.320 15.564 ;
    END
  END rw0_wd_in[181]
  PIN rw0_wd_in[182]
    DIRECTION INPUT ;
    USE SIGNAL ;
    SHAPE ABUTMENT ;
    PORT
      LAYER M4 ;
      RECT 138.248 15.828 138.320 15.852 ;
    END
  END rw0_wd_in[182]
  PIN rw0_wd_in[183]
    DIRECTION INPUT ;
    USE SIGNAL ;
    SHAPE ABUTMENT ;
    PORT
      LAYER M4 ;
      RECT 138.248 16.116 138.320 16.140 ;
    END
  END rw0_wd_in[183]
  PIN rw0_wd_in[184]
    DIRECTION INPUT ;
    USE SIGNAL ;
    SHAPE ABUTMENT ;
    PORT
      LAYER M4 ;
      RECT 138.248 16.404 138.320 16.428 ;
    END
  END rw0_wd_in[184]
  PIN rw0_wd_in[185]
    DIRECTION INPUT ;
    USE SIGNAL ;
    SHAPE ABUTMENT ;
    PORT
      LAYER M4 ;
      RECT 138.248 16.692 138.320 16.716 ;
    END
  END rw0_wd_in[185]
  PIN rw0_wd_in[186]
    DIRECTION INPUT ;
    USE SIGNAL ;
    SHAPE ABUTMENT ;
    PORT
      LAYER M4 ;
      RECT 138.248 16.980 138.320 17.004 ;
    END
  END rw0_wd_in[186]
  PIN rw0_wd_in[187]
    DIRECTION INPUT ;
    USE SIGNAL ;
    SHAPE ABUTMENT ;
    PORT
      LAYER M4 ;
      RECT 138.248 17.268 138.320 17.292 ;
    END
  END rw0_wd_in[187]
  PIN rw0_wd_in[188]
    DIRECTION INPUT ;
    USE SIGNAL ;
    SHAPE ABUTMENT ;
    PORT
      LAYER M4 ;
      RECT 138.248 17.556 138.320 17.580 ;
    END
  END rw0_wd_in[188]
  PIN rw0_wd_in[189]
    DIRECTION INPUT ;
    USE SIGNAL ;
    SHAPE ABUTMENT ;
    PORT
      LAYER M4 ;
      RECT 138.248 17.844 138.320 17.868 ;
    END
  END rw0_wd_in[189]
  PIN rw0_wd_in[190]
    DIRECTION INPUT ;
    USE SIGNAL ;
    SHAPE ABUTMENT ;
    PORT
      LAYER M4 ;
      RECT 138.248 18.132 138.320 18.156 ;
    END
  END rw0_wd_in[190]
  PIN rw0_wd_in[191]
    DIRECTION INPUT ;
    USE SIGNAL ;
    SHAPE ABUTMENT ;
    PORT
      LAYER M4 ;
      RECT 138.248 18.420 138.320 18.444 ;
    END
  END rw0_wd_in[191]
  PIN rw0_wd_in[192]
    DIRECTION INPUT ;
    USE SIGNAL ;
    SHAPE ABUTMENT ;
    PORT
      LAYER M4 ;
      RECT 138.248 18.708 138.320 18.732 ;
    END
  END rw0_wd_in[192]
  PIN rw0_wd_in[193]
    DIRECTION INPUT ;
    USE SIGNAL ;
    SHAPE ABUTMENT ;
    PORT
      LAYER M4 ;
      RECT 138.248 18.996 138.320 19.020 ;
    END
  END rw0_wd_in[193]
  PIN rw0_wd_in[194]
    DIRECTION INPUT ;
    USE SIGNAL ;
    SHAPE ABUTMENT ;
    PORT
      LAYER M4 ;
      RECT 138.248 19.284 138.320 19.308 ;
    END
  END rw0_wd_in[194]
  PIN rw0_wd_in[195]
    DIRECTION INPUT ;
    USE SIGNAL ;
    SHAPE ABUTMENT ;
    PORT
      LAYER M4 ;
      RECT 138.248 19.572 138.320 19.596 ;
    END
  END rw0_wd_in[195]
  PIN rw0_wd_in[196]
    DIRECTION INPUT ;
    USE SIGNAL ;
    SHAPE ABUTMENT ;
    PORT
      LAYER M4 ;
      RECT 138.248 19.860 138.320 19.884 ;
    END
  END rw0_wd_in[196]
  PIN rw0_wd_in[197]
    DIRECTION INPUT ;
    USE SIGNAL ;
    SHAPE ABUTMENT ;
    PORT
      LAYER M4 ;
      RECT 138.248 20.148 138.320 20.172 ;
    END
  END rw0_wd_in[197]
  PIN rw0_wd_in[198]
    DIRECTION INPUT ;
    USE SIGNAL ;
    SHAPE ABUTMENT ;
    PORT
      LAYER M4 ;
      RECT 138.248 20.436 138.320 20.460 ;
    END
  END rw0_wd_in[198]
  PIN rw0_wd_in[199]
    DIRECTION INPUT ;
    USE SIGNAL ;
    SHAPE ABUTMENT ;
    PORT
      LAYER M4 ;
      RECT 138.248 20.724 138.320 20.748 ;
    END
  END rw0_wd_in[199]
  PIN rw0_wd_in[200]
    DIRECTION INPUT ;
    USE SIGNAL ;
    SHAPE ABUTMENT ;
    PORT
      LAYER M4 ;
      RECT 138.248 21.012 138.320 21.036 ;
    END
  END rw0_wd_in[200]
  PIN rw0_wd_in[201]
    DIRECTION INPUT ;
    USE SIGNAL ;
    SHAPE ABUTMENT ;
    PORT
      LAYER M4 ;
      RECT 138.248 21.300 138.320 21.324 ;
    END
  END rw0_wd_in[201]
  PIN rw0_wd_in[202]
    DIRECTION INPUT ;
    USE SIGNAL ;
    SHAPE ABUTMENT ;
    PORT
      LAYER M4 ;
      RECT 138.248 21.588 138.320 21.612 ;
    END
  END rw0_wd_in[202]
  PIN rw0_wd_in[203]
    DIRECTION INPUT ;
    USE SIGNAL ;
    SHAPE ABUTMENT ;
    PORT
      LAYER M4 ;
      RECT 138.248 21.876 138.320 21.900 ;
    END
  END rw0_wd_in[203]
  PIN rw0_wd_in[204]
    DIRECTION INPUT ;
    USE SIGNAL ;
    SHAPE ABUTMENT ;
    PORT
      LAYER M4 ;
      RECT 138.248 22.164 138.320 22.188 ;
    END
  END rw0_wd_in[204]
  PIN rw0_wd_in[205]
    DIRECTION INPUT ;
    USE SIGNAL ;
    SHAPE ABUTMENT ;
    PORT
      LAYER M4 ;
      RECT 138.248 22.452 138.320 22.476 ;
    END
  END rw0_wd_in[205]
  PIN rw0_wd_in[206]
    DIRECTION INPUT ;
    USE SIGNAL ;
    SHAPE ABUTMENT ;
    PORT
      LAYER M4 ;
      RECT 138.248 22.740 138.320 22.764 ;
    END
  END rw0_wd_in[206]
  PIN rw0_wd_in[207]
    DIRECTION INPUT ;
    USE SIGNAL ;
    SHAPE ABUTMENT ;
    PORT
      LAYER M4 ;
      RECT 138.248 23.028 138.320 23.052 ;
    END
  END rw0_wd_in[207]
  PIN rw0_wd_in[208]
    DIRECTION INPUT ;
    USE SIGNAL ;
    SHAPE ABUTMENT ;
    PORT
      LAYER M4 ;
      RECT 138.248 23.316 138.320 23.340 ;
    END
  END rw0_wd_in[208]
  PIN rw0_wd_in[209]
    DIRECTION INPUT ;
    USE SIGNAL ;
    SHAPE ABUTMENT ;
    PORT
      LAYER M4 ;
      RECT 138.248 23.604 138.320 23.628 ;
    END
  END rw0_wd_in[209]
  PIN rw0_wd_in[210]
    DIRECTION INPUT ;
    USE SIGNAL ;
    SHAPE ABUTMENT ;
    PORT
      LAYER M4 ;
      RECT 138.248 23.892 138.320 23.916 ;
    END
  END rw0_wd_in[210]
  PIN rw0_wd_in[211]
    DIRECTION INPUT ;
    USE SIGNAL ;
    SHAPE ABUTMENT ;
    PORT
      LAYER M4 ;
      RECT 138.248 24.180 138.320 24.204 ;
    END
  END rw0_wd_in[211]
  PIN rw0_wd_in[212]
    DIRECTION INPUT ;
    USE SIGNAL ;
    SHAPE ABUTMENT ;
    PORT
      LAYER M4 ;
      RECT 138.248 24.468 138.320 24.492 ;
    END
  END rw0_wd_in[212]
  PIN rw0_wd_in[213]
    DIRECTION INPUT ;
    USE SIGNAL ;
    SHAPE ABUTMENT ;
    PORT
      LAYER M4 ;
      RECT 138.248 24.756 138.320 24.780 ;
    END
  END rw0_wd_in[213]
  PIN rw0_wd_in[214]
    DIRECTION INPUT ;
    USE SIGNAL ;
    SHAPE ABUTMENT ;
    PORT
      LAYER M4 ;
      RECT 138.248 25.044 138.320 25.068 ;
    END
  END rw0_wd_in[214]
  PIN rw0_wd_in[215]
    DIRECTION INPUT ;
    USE SIGNAL ;
    SHAPE ABUTMENT ;
    PORT
      LAYER M4 ;
      RECT 138.248 25.332 138.320 25.356 ;
    END
  END rw0_wd_in[215]
  PIN rw0_wd_in[216]
    DIRECTION INPUT ;
    USE SIGNAL ;
    SHAPE ABUTMENT ;
    PORT
      LAYER M4 ;
      RECT 138.248 25.620 138.320 25.644 ;
    END
  END rw0_wd_in[216]
  PIN rw0_wd_in[217]
    DIRECTION INPUT ;
    USE SIGNAL ;
    SHAPE ABUTMENT ;
    PORT
      LAYER M4 ;
      RECT 138.248 25.908 138.320 25.932 ;
    END
  END rw0_wd_in[217]
  PIN rw0_wd_in[218]
    DIRECTION INPUT ;
    USE SIGNAL ;
    SHAPE ABUTMENT ;
    PORT
      LAYER M4 ;
      RECT 138.248 26.196 138.320 26.220 ;
    END
  END rw0_wd_in[218]
  PIN rw0_wd_in[219]
    DIRECTION INPUT ;
    USE SIGNAL ;
    SHAPE ABUTMENT ;
    PORT
      LAYER M4 ;
      RECT 138.248 26.484 138.320 26.508 ;
    END
  END rw0_wd_in[219]
  PIN rw0_wd_in[220]
    DIRECTION INPUT ;
    USE SIGNAL ;
    SHAPE ABUTMENT ;
    PORT
      LAYER M4 ;
      RECT 138.248 26.772 138.320 26.796 ;
    END
  END rw0_wd_in[220]
  PIN rw0_wd_in[221]
    DIRECTION INPUT ;
    USE SIGNAL ;
    SHAPE ABUTMENT ;
    PORT
      LAYER M4 ;
      RECT 138.248 27.060 138.320 27.084 ;
    END
  END rw0_wd_in[221]
  PIN rw0_wd_in[222]
    DIRECTION INPUT ;
    USE SIGNAL ;
    SHAPE ABUTMENT ;
    PORT
      LAYER M4 ;
      RECT 138.248 27.348 138.320 27.372 ;
    END
  END rw0_wd_in[222]
  PIN rw0_wd_in[223]
    DIRECTION INPUT ;
    USE SIGNAL ;
    SHAPE ABUTMENT ;
    PORT
      LAYER M4 ;
      RECT 138.248 27.636 138.320 27.660 ;
    END
  END rw0_wd_in[223]
  PIN rw0_wd_in[224]
    DIRECTION INPUT ;
    USE SIGNAL ;
    SHAPE ABUTMENT ;
    PORT
      LAYER M4 ;
      RECT 138.248 27.924 138.320 27.948 ;
    END
  END rw0_wd_in[224]
  PIN rw0_wd_in[225]
    DIRECTION INPUT ;
    USE SIGNAL ;
    SHAPE ABUTMENT ;
    PORT
      LAYER M4 ;
      RECT 138.248 28.212 138.320 28.236 ;
    END
  END rw0_wd_in[225]
  PIN rw0_wd_in[226]
    DIRECTION INPUT ;
    USE SIGNAL ;
    SHAPE ABUTMENT ;
    PORT
      LAYER M4 ;
      RECT 138.248 28.500 138.320 28.524 ;
    END
  END rw0_wd_in[226]
  PIN rw0_wd_in[227]
    DIRECTION INPUT ;
    USE SIGNAL ;
    SHAPE ABUTMENT ;
    PORT
      LAYER M4 ;
      RECT 138.248 28.788 138.320 28.812 ;
    END
  END rw0_wd_in[227]
  PIN rw0_wd_in[228]
    DIRECTION INPUT ;
    USE SIGNAL ;
    SHAPE ABUTMENT ;
    PORT
      LAYER M4 ;
      RECT 138.248 29.076 138.320 29.100 ;
    END
  END rw0_wd_in[228]
  PIN rw0_wd_in[229]
    DIRECTION INPUT ;
    USE SIGNAL ;
    SHAPE ABUTMENT ;
    PORT
      LAYER M4 ;
      RECT 138.248 29.364 138.320 29.388 ;
    END
  END rw0_wd_in[229]
  PIN rw0_wd_in[230]
    DIRECTION INPUT ;
    USE SIGNAL ;
    SHAPE ABUTMENT ;
    PORT
      LAYER M4 ;
      RECT 138.248 29.652 138.320 29.676 ;
    END
  END rw0_wd_in[230]
  PIN rw0_wd_in[231]
    DIRECTION INPUT ;
    USE SIGNAL ;
    SHAPE ABUTMENT ;
    PORT
      LAYER M4 ;
      RECT 138.248 29.940 138.320 29.964 ;
    END
  END rw0_wd_in[231]
  PIN rw0_wd_in[232]
    DIRECTION INPUT ;
    USE SIGNAL ;
    SHAPE ABUTMENT ;
    PORT
      LAYER M4 ;
      RECT 138.248 30.228 138.320 30.252 ;
    END
  END rw0_wd_in[232]
  PIN rw0_wd_in[233]
    DIRECTION INPUT ;
    USE SIGNAL ;
    SHAPE ABUTMENT ;
    PORT
      LAYER M4 ;
      RECT 138.248 30.516 138.320 30.540 ;
    END
  END rw0_wd_in[233]
  PIN rw0_wd_in[234]
    DIRECTION INPUT ;
    USE SIGNAL ;
    SHAPE ABUTMENT ;
    PORT
      LAYER M4 ;
      RECT 138.248 30.804 138.320 30.828 ;
    END
  END rw0_wd_in[234]
  PIN rw0_wd_in[235]
    DIRECTION INPUT ;
    USE SIGNAL ;
    SHAPE ABUTMENT ;
    PORT
      LAYER M4 ;
      RECT 138.248 31.092 138.320 31.116 ;
    END
  END rw0_wd_in[235]
  PIN rw0_wd_in[236]
    DIRECTION INPUT ;
    USE SIGNAL ;
    SHAPE ABUTMENT ;
    PORT
      LAYER M4 ;
      RECT 138.248 31.380 138.320 31.404 ;
    END
  END rw0_wd_in[236]
  PIN rw0_wd_in[237]
    DIRECTION INPUT ;
    USE SIGNAL ;
    SHAPE ABUTMENT ;
    PORT
      LAYER M4 ;
      RECT 138.248 31.668 138.320 31.692 ;
    END
  END rw0_wd_in[237]
  PIN rw0_wd_in[238]
    DIRECTION INPUT ;
    USE SIGNAL ;
    SHAPE ABUTMENT ;
    PORT
      LAYER M4 ;
      RECT 138.248 31.956 138.320 31.980 ;
    END
  END rw0_wd_in[238]
  PIN rw0_wd_in[239]
    DIRECTION INPUT ;
    USE SIGNAL ;
    SHAPE ABUTMENT ;
    PORT
      LAYER M4 ;
      RECT 138.248 32.244 138.320 32.268 ;
    END
  END rw0_wd_in[239]
  PIN rw0_wd_in[240]
    DIRECTION INPUT ;
    USE SIGNAL ;
    SHAPE ABUTMENT ;
    PORT
      LAYER M4 ;
      RECT 138.248 32.532 138.320 32.556 ;
    END
  END rw0_wd_in[240]
  PIN rw0_wd_in[241]
    DIRECTION INPUT ;
    USE SIGNAL ;
    SHAPE ABUTMENT ;
    PORT
      LAYER M4 ;
      RECT 138.248 32.820 138.320 32.844 ;
    END
  END rw0_wd_in[241]
  PIN rw0_wd_in[242]
    DIRECTION INPUT ;
    USE SIGNAL ;
    SHAPE ABUTMENT ;
    PORT
      LAYER M4 ;
      RECT 138.248 33.108 138.320 33.132 ;
    END
  END rw0_wd_in[242]
  PIN rw0_wd_in[243]
    DIRECTION INPUT ;
    USE SIGNAL ;
    SHAPE ABUTMENT ;
    PORT
      LAYER M4 ;
      RECT 138.248 33.396 138.320 33.420 ;
    END
  END rw0_wd_in[243]
  PIN rw0_wd_in[244]
    DIRECTION INPUT ;
    USE SIGNAL ;
    SHAPE ABUTMENT ;
    PORT
      LAYER M4 ;
      RECT 138.248 33.684 138.320 33.708 ;
    END
  END rw0_wd_in[244]
  PIN rw0_wd_in[245]
    DIRECTION INPUT ;
    USE SIGNAL ;
    SHAPE ABUTMENT ;
    PORT
      LAYER M4 ;
      RECT 138.248 33.972 138.320 33.996 ;
    END
  END rw0_wd_in[245]
  PIN rw0_wd_in[246]
    DIRECTION INPUT ;
    USE SIGNAL ;
    SHAPE ABUTMENT ;
    PORT
      LAYER M4 ;
      RECT 138.248 34.260 138.320 34.284 ;
    END
  END rw0_wd_in[246]
  PIN rw0_wd_in[247]
    DIRECTION INPUT ;
    USE SIGNAL ;
    SHAPE ABUTMENT ;
    PORT
      LAYER M4 ;
      RECT 138.248 34.548 138.320 34.572 ;
    END
  END rw0_wd_in[247]
  PIN rw0_wd_in[248]
    DIRECTION INPUT ;
    USE SIGNAL ;
    SHAPE ABUTMENT ;
    PORT
      LAYER M4 ;
      RECT 138.248 34.836 138.320 34.860 ;
    END
  END rw0_wd_in[248]
  PIN rw0_wd_in[249]
    DIRECTION INPUT ;
    USE SIGNAL ;
    SHAPE ABUTMENT ;
    PORT
      LAYER M4 ;
      RECT 138.248 35.124 138.320 35.148 ;
    END
  END rw0_wd_in[249]
  PIN rw0_wd_in[250]
    DIRECTION INPUT ;
    USE SIGNAL ;
    SHAPE ABUTMENT ;
    PORT
      LAYER M4 ;
      RECT 138.248 35.412 138.320 35.436 ;
    END
  END rw0_wd_in[250]
  PIN rw0_wd_in[251]
    DIRECTION INPUT ;
    USE SIGNAL ;
    SHAPE ABUTMENT ;
    PORT
      LAYER M4 ;
      RECT 138.248 35.700 138.320 35.724 ;
    END
  END rw0_wd_in[251]
  PIN rw0_wd_in[252]
    DIRECTION INPUT ;
    USE SIGNAL ;
    SHAPE ABUTMENT ;
    PORT
      LAYER M4 ;
      RECT 138.248 35.988 138.320 36.012 ;
    END
  END rw0_wd_in[252]
  PIN rw0_wd_in[253]
    DIRECTION INPUT ;
    USE SIGNAL ;
    SHAPE ABUTMENT ;
    PORT
      LAYER M4 ;
      RECT 138.248 36.276 138.320 36.300 ;
    END
  END rw0_wd_in[253]
  PIN rw0_wd_in[254]
    DIRECTION INPUT ;
    USE SIGNAL ;
    SHAPE ABUTMENT ;
    PORT
      LAYER M4 ;
      RECT 138.248 36.564 138.320 36.588 ;
    END
  END rw0_wd_in[254]
  PIN rw0_wd_in[255]
    DIRECTION INPUT ;
    USE SIGNAL ;
    SHAPE ABUTMENT ;
    PORT
      LAYER M4 ;
      RECT 138.248 36.852 138.320 36.876 ;
    END
  END rw0_wd_in[255]
  PIN rw0_wd_in[256]
    DIRECTION INPUT ;
    USE SIGNAL ;
    SHAPE ABUTMENT ;
    PORT
      LAYER M3 ;
      RECT 0.207 0.000 0.225 0.054 ;
    END
  END rw0_wd_in[256]
  PIN rw0_wd_in[257]
    DIRECTION INPUT ;
    USE SIGNAL ;
    SHAPE ABUTMENT ;
    PORT
      LAYER M3 ;
      RECT 0.459 0.000 0.477 0.054 ;
    END
  END rw0_wd_in[257]
  PIN rw0_wd_in[258]
    DIRECTION INPUT ;
    USE SIGNAL ;
    SHAPE ABUTMENT ;
    PORT
      LAYER M3 ;
      RECT 0.711 0.000 0.729 0.054 ;
    END
  END rw0_wd_in[258]
  PIN rw0_wd_in[259]
    DIRECTION INPUT ;
    USE SIGNAL ;
    SHAPE ABUTMENT ;
    PORT
      LAYER M3 ;
      RECT 0.963 0.000 0.981 0.054 ;
    END
  END rw0_wd_in[259]
  PIN rw0_wd_in[260]
    DIRECTION INPUT ;
    USE SIGNAL ;
    SHAPE ABUTMENT ;
    PORT
      LAYER M3 ;
      RECT 1.215 0.000 1.233 0.054 ;
    END
  END rw0_wd_in[260]
  PIN rw0_wd_in[261]
    DIRECTION INPUT ;
    USE SIGNAL ;
    SHAPE ABUTMENT ;
    PORT
      LAYER M3 ;
      RECT 1.467 0.000 1.485 0.054 ;
    END
  END rw0_wd_in[261]
  PIN rw0_wd_in[262]
    DIRECTION INPUT ;
    USE SIGNAL ;
    SHAPE ABUTMENT ;
    PORT
      LAYER M3 ;
      RECT 1.719 0.000 1.737 0.054 ;
    END
  END rw0_wd_in[262]
  PIN rw0_wd_in[263]
    DIRECTION INPUT ;
    USE SIGNAL ;
    SHAPE ABUTMENT ;
    PORT
      LAYER M3 ;
      RECT 1.971 0.000 1.989 0.054 ;
    END
  END rw0_wd_in[263]
  PIN rw0_wd_in[264]
    DIRECTION INPUT ;
    USE SIGNAL ;
    SHAPE ABUTMENT ;
    PORT
      LAYER M3 ;
      RECT 2.223 0.000 2.241 0.054 ;
    END
  END rw0_wd_in[264]
  PIN rw0_wd_in[265]
    DIRECTION INPUT ;
    USE SIGNAL ;
    SHAPE ABUTMENT ;
    PORT
      LAYER M3 ;
      RECT 2.475 0.000 2.493 0.054 ;
    END
  END rw0_wd_in[265]
  PIN rw0_wd_in[266]
    DIRECTION INPUT ;
    USE SIGNAL ;
    SHAPE ABUTMENT ;
    PORT
      LAYER M3 ;
      RECT 2.727 0.000 2.745 0.054 ;
    END
  END rw0_wd_in[266]
  PIN rw0_wd_in[267]
    DIRECTION INPUT ;
    USE SIGNAL ;
    SHAPE ABUTMENT ;
    PORT
      LAYER M3 ;
      RECT 2.979 0.000 2.997 0.054 ;
    END
  END rw0_wd_in[267]
  PIN rw0_wd_in[268]
    DIRECTION INPUT ;
    USE SIGNAL ;
    SHAPE ABUTMENT ;
    PORT
      LAYER M3 ;
      RECT 3.231 0.000 3.249 0.054 ;
    END
  END rw0_wd_in[268]
  PIN rw0_wd_in[269]
    DIRECTION INPUT ;
    USE SIGNAL ;
    SHAPE ABUTMENT ;
    PORT
      LAYER M3 ;
      RECT 3.483 0.000 3.501 0.054 ;
    END
  END rw0_wd_in[269]
  PIN rw0_wd_in[270]
    DIRECTION INPUT ;
    USE SIGNAL ;
    SHAPE ABUTMENT ;
    PORT
      LAYER M3 ;
      RECT 3.735 0.000 3.753 0.054 ;
    END
  END rw0_wd_in[270]
  PIN rw0_wd_in[271]
    DIRECTION INPUT ;
    USE SIGNAL ;
    SHAPE ABUTMENT ;
    PORT
      LAYER M3 ;
      RECT 3.987 0.000 4.005 0.054 ;
    END
  END rw0_wd_in[271]
  PIN rw0_wd_in[272]
    DIRECTION INPUT ;
    USE SIGNAL ;
    SHAPE ABUTMENT ;
    PORT
      LAYER M3 ;
      RECT 4.239 0.000 4.257 0.054 ;
    END
  END rw0_wd_in[272]
  PIN rw0_wd_in[273]
    DIRECTION INPUT ;
    USE SIGNAL ;
    SHAPE ABUTMENT ;
    PORT
      LAYER M3 ;
      RECT 4.491 0.000 4.509 0.054 ;
    END
  END rw0_wd_in[273]
  PIN rw0_wd_in[274]
    DIRECTION INPUT ;
    USE SIGNAL ;
    SHAPE ABUTMENT ;
    PORT
      LAYER M3 ;
      RECT 4.743 0.000 4.761 0.054 ;
    END
  END rw0_wd_in[274]
  PIN rw0_wd_in[275]
    DIRECTION INPUT ;
    USE SIGNAL ;
    SHAPE ABUTMENT ;
    PORT
      LAYER M3 ;
      RECT 4.995 0.000 5.013 0.054 ;
    END
  END rw0_wd_in[275]
  PIN rw0_wd_in[276]
    DIRECTION INPUT ;
    USE SIGNAL ;
    SHAPE ABUTMENT ;
    PORT
      LAYER M3 ;
      RECT 5.247 0.000 5.265 0.054 ;
    END
  END rw0_wd_in[276]
  PIN rw0_wd_in[277]
    DIRECTION INPUT ;
    USE SIGNAL ;
    SHAPE ABUTMENT ;
    PORT
      LAYER M3 ;
      RECT 5.499 0.000 5.517 0.054 ;
    END
  END rw0_wd_in[277]
  PIN rw0_wd_in[278]
    DIRECTION INPUT ;
    USE SIGNAL ;
    SHAPE ABUTMENT ;
    PORT
      LAYER M3 ;
      RECT 5.751 0.000 5.769 0.054 ;
    END
  END rw0_wd_in[278]
  PIN rw0_wd_in[279]
    DIRECTION INPUT ;
    USE SIGNAL ;
    SHAPE ABUTMENT ;
    PORT
      LAYER M3 ;
      RECT 6.003 0.000 6.021 0.054 ;
    END
  END rw0_wd_in[279]
  PIN rw0_wd_in[280]
    DIRECTION INPUT ;
    USE SIGNAL ;
    SHAPE ABUTMENT ;
    PORT
      LAYER M3 ;
      RECT 6.255 0.000 6.273 0.054 ;
    END
  END rw0_wd_in[280]
  PIN rw0_wd_in[281]
    DIRECTION INPUT ;
    USE SIGNAL ;
    SHAPE ABUTMENT ;
    PORT
      LAYER M3 ;
      RECT 6.507 0.000 6.525 0.054 ;
    END
  END rw0_wd_in[281]
  PIN rw0_wd_in[282]
    DIRECTION INPUT ;
    USE SIGNAL ;
    SHAPE ABUTMENT ;
    PORT
      LAYER M3 ;
      RECT 6.759 0.000 6.777 0.054 ;
    END
  END rw0_wd_in[282]
  PIN rw0_wd_in[283]
    DIRECTION INPUT ;
    USE SIGNAL ;
    SHAPE ABUTMENT ;
    PORT
      LAYER M3 ;
      RECT 7.011 0.000 7.029 0.054 ;
    END
  END rw0_wd_in[283]
  PIN rw0_wd_in[284]
    DIRECTION INPUT ;
    USE SIGNAL ;
    SHAPE ABUTMENT ;
    PORT
      LAYER M3 ;
      RECT 7.263 0.000 7.281 0.054 ;
    END
  END rw0_wd_in[284]
  PIN rw0_wd_in[285]
    DIRECTION INPUT ;
    USE SIGNAL ;
    SHAPE ABUTMENT ;
    PORT
      LAYER M3 ;
      RECT 7.515 0.000 7.533 0.054 ;
    END
  END rw0_wd_in[285]
  PIN rw0_wd_in[286]
    DIRECTION INPUT ;
    USE SIGNAL ;
    SHAPE ABUTMENT ;
    PORT
      LAYER M3 ;
      RECT 7.767 0.000 7.785 0.054 ;
    END
  END rw0_wd_in[286]
  PIN rw0_wd_in[287]
    DIRECTION INPUT ;
    USE SIGNAL ;
    SHAPE ABUTMENT ;
    PORT
      LAYER M3 ;
      RECT 8.019 0.000 8.037 0.054 ;
    END
  END rw0_wd_in[287]
  PIN rw0_wd_in[288]
    DIRECTION INPUT ;
    USE SIGNAL ;
    SHAPE ABUTMENT ;
    PORT
      LAYER M3 ;
      RECT 8.271 0.000 8.289 0.054 ;
    END
  END rw0_wd_in[288]
  PIN rw0_wd_in[289]
    DIRECTION INPUT ;
    USE SIGNAL ;
    SHAPE ABUTMENT ;
    PORT
      LAYER M3 ;
      RECT 8.523 0.000 8.541 0.054 ;
    END
  END rw0_wd_in[289]
  PIN rw0_wd_in[290]
    DIRECTION INPUT ;
    USE SIGNAL ;
    SHAPE ABUTMENT ;
    PORT
      LAYER M3 ;
      RECT 8.775 0.000 8.793 0.054 ;
    END
  END rw0_wd_in[290]
  PIN rw0_wd_in[291]
    DIRECTION INPUT ;
    USE SIGNAL ;
    SHAPE ABUTMENT ;
    PORT
      LAYER M3 ;
      RECT 9.027 0.000 9.045 0.054 ;
    END
  END rw0_wd_in[291]
  PIN rw0_wd_in[292]
    DIRECTION INPUT ;
    USE SIGNAL ;
    SHAPE ABUTMENT ;
    PORT
      LAYER M3 ;
      RECT 9.279 0.000 9.297 0.054 ;
    END
  END rw0_wd_in[292]
  PIN rw0_wd_in[293]
    DIRECTION INPUT ;
    USE SIGNAL ;
    SHAPE ABUTMENT ;
    PORT
      LAYER M3 ;
      RECT 9.531 0.000 9.549 0.054 ;
    END
  END rw0_wd_in[293]
  PIN rw0_wd_in[294]
    DIRECTION INPUT ;
    USE SIGNAL ;
    SHAPE ABUTMENT ;
    PORT
      LAYER M3 ;
      RECT 9.783 0.000 9.801 0.054 ;
    END
  END rw0_wd_in[294]
  PIN rw0_wd_in[295]
    DIRECTION INPUT ;
    USE SIGNAL ;
    SHAPE ABUTMENT ;
    PORT
      LAYER M3 ;
      RECT 10.035 0.000 10.053 0.054 ;
    END
  END rw0_wd_in[295]
  PIN rw0_wd_in[296]
    DIRECTION INPUT ;
    USE SIGNAL ;
    SHAPE ABUTMENT ;
    PORT
      LAYER M3 ;
      RECT 10.287 0.000 10.305 0.054 ;
    END
  END rw0_wd_in[296]
  PIN rw0_wd_in[297]
    DIRECTION INPUT ;
    USE SIGNAL ;
    SHAPE ABUTMENT ;
    PORT
      LAYER M3 ;
      RECT 10.539 0.000 10.557 0.054 ;
    END
  END rw0_wd_in[297]
  PIN rw0_wd_in[298]
    DIRECTION INPUT ;
    USE SIGNAL ;
    SHAPE ABUTMENT ;
    PORT
      LAYER M3 ;
      RECT 10.791 0.000 10.809 0.054 ;
    END
  END rw0_wd_in[298]
  PIN rw0_wd_in[299]
    DIRECTION INPUT ;
    USE SIGNAL ;
    SHAPE ABUTMENT ;
    PORT
      LAYER M3 ;
      RECT 11.043 0.000 11.061 0.054 ;
    END
  END rw0_wd_in[299]
  PIN rw0_wd_in[300]
    DIRECTION INPUT ;
    USE SIGNAL ;
    SHAPE ABUTMENT ;
    PORT
      LAYER M3 ;
      RECT 11.295 0.000 11.313 0.054 ;
    END
  END rw0_wd_in[300]
  PIN rw0_wd_in[301]
    DIRECTION INPUT ;
    USE SIGNAL ;
    SHAPE ABUTMENT ;
    PORT
      LAYER M3 ;
      RECT 11.547 0.000 11.565 0.054 ;
    END
  END rw0_wd_in[301]
  PIN rw0_wd_in[302]
    DIRECTION INPUT ;
    USE SIGNAL ;
    SHAPE ABUTMENT ;
    PORT
      LAYER M3 ;
      RECT 11.799 0.000 11.817 0.054 ;
    END
  END rw0_wd_in[302]
  PIN rw0_wd_in[303]
    DIRECTION INPUT ;
    USE SIGNAL ;
    SHAPE ABUTMENT ;
    PORT
      LAYER M3 ;
      RECT 12.051 0.000 12.069 0.054 ;
    END
  END rw0_wd_in[303]
  PIN rw0_wd_in[304]
    DIRECTION INPUT ;
    USE SIGNAL ;
    SHAPE ABUTMENT ;
    PORT
      LAYER M3 ;
      RECT 12.303 0.000 12.321 0.054 ;
    END
  END rw0_wd_in[304]
  PIN rw0_wd_in[305]
    DIRECTION INPUT ;
    USE SIGNAL ;
    SHAPE ABUTMENT ;
    PORT
      LAYER M3 ;
      RECT 12.555 0.000 12.573 0.054 ;
    END
  END rw0_wd_in[305]
  PIN rw0_wd_in[306]
    DIRECTION INPUT ;
    USE SIGNAL ;
    SHAPE ABUTMENT ;
    PORT
      LAYER M3 ;
      RECT 12.807 0.000 12.825 0.054 ;
    END
  END rw0_wd_in[306]
  PIN rw0_wd_in[307]
    DIRECTION INPUT ;
    USE SIGNAL ;
    SHAPE ABUTMENT ;
    PORT
      LAYER M3 ;
      RECT 13.059 0.000 13.077 0.054 ;
    END
  END rw0_wd_in[307]
  PIN rw0_wd_in[308]
    DIRECTION INPUT ;
    USE SIGNAL ;
    SHAPE ABUTMENT ;
    PORT
      LAYER M3 ;
      RECT 13.311 0.000 13.329 0.054 ;
    END
  END rw0_wd_in[308]
  PIN rw0_wd_in[309]
    DIRECTION INPUT ;
    USE SIGNAL ;
    SHAPE ABUTMENT ;
    PORT
      LAYER M3 ;
      RECT 13.563 0.000 13.581 0.054 ;
    END
  END rw0_wd_in[309]
  PIN rw0_wd_in[310]
    DIRECTION INPUT ;
    USE SIGNAL ;
    SHAPE ABUTMENT ;
    PORT
      LAYER M3 ;
      RECT 13.815 0.000 13.833 0.054 ;
    END
  END rw0_wd_in[310]
  PIN rw0_wd_in[311]
    DIRECTION INPUT ;
    USE SIGNAL ;
    SHAPE ABUTMENT ;
    PORT
      LAYER M3 ;
      RECT 14.067 0.000 14.085 0.054 ;
    END
  END rw0_wd_in[311]
  PIN rw0_wd_in[312]
    DIRECTION INPUT ;
    USE SIGNAL ;
    SHAPE ABUTMENT ;
    PORT
      LAYER M3 ;
      RECT 14.319 0.000 14.337 0.054 ;
    END
  END rw0_wd_in[312]
  PIN rw0_wd_in[313]
    DIRECTION INPUT ;
    USE SIGNAL ;
    SHAPE ABUTMENT ;
    PORT
      LAYER M3 ;
      RECT 14.571 0.000 14.589 0.054 ;
    END
  END rw0_wd_in[313]
  PIN rw0_wd_in[314]
    DIRECTION INPUT ;
    USE SIGNAL ;
    SHAPE ABUTMENT ;
    PORT
      LAYER M3 ;
      RECT 14.823 0.000 14.841 0.054 ;
    END
  END rw0_wd_in[314]
  PIN rw0_wd_in[315]
    DIRECTION INPUT ;
    USE SIGNAL ;
    SHAPE ABUTMENT ;
    PORT
      LAYER M3 ;
      RECT 15.075 0.000 15.093 0.054 ;
    END
  END rw0_wd_in[315]
  PIN rw0_wd_in[316]
    DIRECTION INPUT ;
    USE SIGNAL ;
    SHAPE ABUTMENT ;
    PORT
      LAYER M3 ;
      RECT 15.327 0.000 15.345 0.054 ;
    END
  END rw0_wd_in[316]
  PIN rw0_wd_in[317]
    DIRECTION INPUT ;
    USE SIGNAL ;
    SHAPE ABUTMENT ;
    PORT
      LAYER M3 ;
      RECT 15.579 0.000 15.597 0.054 ;
    END
  END rw0_wd_in[317]
  PIN rw0_wd_in[318]
    DIRECTION INPUT ;
    USE SIGNAL ;
    SHAPE ABUTMENT ;
    PORT
      LAYER M3 ;
      RECT 15.831 0.000 15.849 0.054 ;
    END
  END rw0_wd_in[318]
  PIN rw0_wd_in[319]
    DIRECTION INPUT ;
    USE SIGNAL ;
    SHAPE ABUTMENT ;
    PORT
      LAYER M3 ;
      RECT 16.083 0.000 16.101 0.054 ;
    END
  END rw0_wd_in[319]
  PIN rw0_wd_in[320]
    DIRECTION INPUT ;
    USE SIGNAL ;
    SHAPE ABUTMENT ;
    PORT
      LAYER M3 ;
      RECT 16.335 0.000 16.353 0.054 ;
    END
  END rw0_wd_in[320]
  PIN rw0_wd_in[321]
    DIRECTION INPUT ;
    USE SIGNAL ;
    SHAPE ABUTMENT ;
    PORT
      LAYER M3 ;
      RECT 16.587 0.000 16.605 0.054 ;
    END
  END rw0_wd_in[321]
  PIN rw0_wd_in[322]
    DIRECTION INPUT ;
    USE SIGNAL ;
    SHAPE ABUTMENT ;
    PORT
      LAYER M3 ;
      RECT 16.839 0.000 16.857 0.054 ;
    END
  END rw0_wd_in[322]
  PIN rw0_wd_in[323]
    DIRECTION INPUT ;
    USE SIGNAL ;
    SHAPE ABUTMENT ;
    PORT
      LAYER M3 ;
      RECT 17.091 0.000 17.109 0.054 ;
    END
  END rw0_wd_in[323]
  PIN rw0_wd_in[324]
    DIRECTION INPUT ;
    USE SIGNAL ;
    SHAPE ABUTMENT ;
    PORT
      LAYER M3 ;
      RECT 17.343 0.000 17.361 0.054 ;
    END
  END rw0_wd_in[324]
  PIN rw0_wd_in[325]
    DIRECTION INPUT ;
    USE SIGNAL ;
    SHAPE ABUTMENT ;
    PORT
      LAYER M3 ;
      RECT 17.595 0.000 17.613 0.054 ;
    END
  END rw0_wd_in[325]
  PIN rw0_wd_in[326]
    DIRECTION INPUT ;
    USE SIGNAL ;
    SHAPE ABUTMENT ;
    PORT
      LAYER M3 ;
      RECT 17.847 0.000 17.865 0.054 ;
    END
  END rw0_wd_in[326]
  PIN rw0_wd_in[327]
    DIRECTION INPUT ;
    USE SIGNAL ;
    SHAPE ABUTMENT ;
    PORT
      LAYER M3 ;
      RECT 18.099 0.000 18.117 0.054 ;
    END
  END rw0_wd_in[327]
  PIN rw0_wd_in[328]
    DIRECTION INPUT ;
    USE SIGNAL ;
    SHAPE ABUTMENT ;
    PORT
      LAYER M3 ;
      RECT 18.351 0.000 18.369 0.054 ;
    END
  END rw0_wd_in[328]
  PIN rw0_wd_in[329]
    DIRECTION INPUT ;
    USE SIGNAL ;
    SHAPE ABUTMENT ;
    PORT
      LAYER M3 ;
      RECT 18.603 0.000 18.621 0.054 ;
    END
  END rw0_wd_in[329]
  PIN rw0_wd_in[330]
    DIRECTION INPUT ;
    USE SIGNAL ;
    SHAPE ABUTMENT ;
    PORT
      LAYER M3 ;
      RECT 18.855 0.000 18.873 0.054 ;
    END
  END rw0_wd_in[330]
  PIN rw0_wd_in[331]
    DIRECTION INPUT ;
    USE SIGNAL ;
    SHAPE ABUTMENT ;
    PORT
      LAYER M3 ;
      RECT 19.107 0.000 19.125 0.054 ;
    END
  END rw0_wd_in[331]
  PIN rw0_wd_in[332]
    DIRECTION INPUT ;
    USE SIGNAL ;
    SHAPE ABUTMENT ;
    PORT
      LAYER M3 ;
      RECT 19.359 0.000 19.377 0.054 ;
    END
  END rw0_wd_in[332]
  PIN rw0_wd_in[333]
    DIRECTION INPUT ;
    USE SIGNAL ;
    SHAPE ABUTMENT ;
    PORT
      LAYER M3 ;
      RECT 19.611 0.000 19.629 0.054 ;
    END
  END rw0_wd_in[333]
  PIN rw0_wd_in[334]
    DIRECTION INPUT ;
    USE SIGNAL ;
    SHAPE ABUTMENT ;
    PORT
      LAYER M3 ;
      RECT 19.863 0.000 19.881 0.054 ;
    END
  END rw0_wd_in[334]
  PIN rw0_wd_in[335]
    DIRECTION INPUT ;
    USE SIGNAL ;
    SHAPE ABUTMENT ;
    PORT
      LAYER M3 ;
      RECT 20.115 0.000 20.133 0.054 ;
    END
  END rw0_wd_in[335]
  PIN rw0_wd_in[336]
    DIRECTION INPUT ;
    USE SIGNAL ;
    SHAPE ABUTMENT ;
    PORT
      LAYER M3 ;
      RECT 20.367 0.000 20.385 0.054 ;
    END
  END rw0_wd_in[336]
  PIN rw0_wd_in[337]
    DIRECTION INPUT ;
    USE SIGNAL ;
    SHAPE ABUTMENT ;
    PORT
      LAYER M3 ;
      RECT 20.619 0.000 20.637 0.054 ;
    END
  END rw0_wd_in[337]
  PIN rw0_wd_in[338]
    DIRECTION INPUT ;
    USE SIGNAL ;
    SHAPE ABUTMENT ;
    PORT
      LAYER M3 ;
      RECT 20.871 0.000 20.889 0.054 ;
    END
  END rw0_wd_in[338]
  PIN rw0_wd_in[339]
    DIRECTION INPUT ;
    USE SIGNAL ;
    SHAPE ABUTMENT ;
    PORT
      LAYER M3 ;
      RECT 21.123 0.000 21.141 0.054 ;
    END
  END rw0_wd_in[339]
  PIN rw0_wd_in[340]
    DIRECTION INPUT ;
    USE SIGNAL ;
    SHAPE ABUTMENT ;
    PORT
      LAYER M3 ;
      RECT 21.375 0.000 21.393 0.054 ;
    END
  END rw0_wd_in[340]
  PIN rw0_wd_in[341]
    DIRECTION INPUT ;
    USE SIGNAL ;
    SHAPE ABUTMENT ;
    PORT
      LAYER M3 ;
      RECT 21.627 0.000 21.645 0.054 ;
    END
  END rw0_wd_in[341]
  PIN rw0_wd_in[342]
    DIRECTION INPUT ;
    USE SIGNAL ;
    SHAPE ABUTMENT ;
    PORT
      LAYER M3 ;
      RECT 21.879 0.000 21.897 0.054 ;
    END
  END rw0_wd_in[342]
  PIN rw0_wd_in[343]
    DIRECTION INPUT ;
    USE SIGNAL ;
    SHAPE ABUTMENT ;
    PORT
      LAYER M3 ;
      RECT 22.131 0.000 22.149 0.054 ;
    END
  END rw0_wd_in[343]
  PIN rw0_wd_in[344]
    DIRECTION INPUT ;
    USE SIGNAL ;
    SHAPE ABUTMENT ;
    PORT
      LAYER M3 ;
      RECT 22.383 0.000 22.401 0.054 ;
    END
  END rw0_wd_in[344]
  PIN rw0_wd_in[345]
    DIRECTION INPUT ;
    USE SIGNAL ;
    SHAPE ABUTMENT ;
    PORT
      LAYER M3 ;
      RECT 22.635 0.000 22.653 0.054 ;
    END
  END rw0_wd_in[345]
  PIN rw0_wd_in[346]
    DIRECTION INPUT ;
    USE SIGNAL ;
    SHAPE ABUTMENT ;
    PORT
      LAYER M3 ;
      RECT 22.887 0.000 22.905 0.054 ;
    END
  END rw0_wd_in[346]
  PIN rw0_wd_in[347]
    DIRECTION INPUT ;
    USE SIGNAL ;
    SHAPE ABUTMENT ;
    PORT
      LAYER M3 ;
      RECT 23.139 0.000 23.157 0.054 ;
    END
  END rw0_wd_in[347]
  PIN rw0_wd_in[348]
    DIRECTION INPUT ;
    USE SIGNAL ;
    SHAPE ABUTMENT ;
    PORT
      LAYER M3 ;
      RECT 23.391 0.000 23.409 0.054 ;
    END
  END rw0_wd_in[348]
  PIN rw0_wd_in[349]
    DIRECTION INPUT ;
    USE SIGNAL ;
    SHAPE ABUTMENT ;
    PORT
      LAYER M3 ;
      RECT 23.643 0.000 23.661 0.054 ;
    END
  END rw0_wd_in[349]
  PIN rw0_wd_in[350]
    DIRECTION INPUT ;
    USE SIGNAL ;
    SHAPE ABUTMENT ;
    PORT
      LAYER M3 ;
      RECT 23.895 0.000 23.913 0.054 ;
    END
  END rw0_wd_in[350]
  PIN rw0_wd_in[351]
    DIRECTION INPUT ;
    USE SIGNAL ;
    SHAPE ABUTMENT ;
    PORT
      LAYER M3 ;
      RECT 24.147 0.000 24.165 0.054 ;
    END
  END rw0_wd_in[351]
  PIN rw0_wd_in[352]
    DIRECTION INPUT ;
    USE SIGNAL ;
    SHAPE ABUTMENT ;
    PORT
      LAYER M3 ;
      RECT 24.399 0.000 24.417 0.054 ;
    END
  END rw0_wd_in[352]
  PIN rw0_wd_in[353]
    DIRECTION INPUT ;
    USE SIGNAL ;
    SHAPE ABUTMENT ;
    PORT
      LAYER M3 ;
      RECT 24.651 0.000 24.669 0.054 ;
    END
  END rw0_wd_in[353]
  PIN rw0_wd_in[354]
    DIRECTION INPUT ;
    USE SIGNAL ;
    SHAPE ABUTMENT ;
    PORT
      LAYER M3 ;
      RECT 24.903 0.000 24.921 0.054 ;
    END
  END rw0_wd_in[354]
  PIN rw0_wd_in[355]
    DIRECTION INPUT ;
    USE SIGNAL ;
    SHAPE ABUTMENT ;
    PORT
      LAYER M3 ;
      RECT 25.155 0.000 25.173 0.054 ;
    END
  END rw0_wd_in[355]
  PIN rw0_wd_in[356]
    DIRECTION INPUT ;
    USE SIGNAL ;
    SHAPE ABUTMENT ;
    PORT
      LAYER M3 ;
      RECT 25.407 0.000 25.425 0.054 ;
    END
  END rw0_wd_in[356]
  PIN rw0_wd_in[357]
    DIRECTION INPUT ;
    USE SIGNAL ;
    SHAPE ABUTMENT ;
    PORT
      LAYER M3 ;
      RECT 25.659 0.000 25.677 0.054 ;
    END
  END rw0_wd_in[357]
  PIN rw0_wd_in[358]
    DIRECTION INPUT ;
    USE SIGNAL ;
    SHAPE ABUTMENT ;
    PORT
      LAYER M3 ;
      RECT 25.911 0.000 25.929 0.054 ;
    END
  END rw0_wd_in[358]
  PIN rw0_wd_in[359]
    DIRECTION INPUT ;
    USE SIGNAL ;
    SHAPE ABUTMENT ;
    PORT
      LAYER M3 ;
      RECT 26.163 0.000 26.181 0.054 ;
    END
  END rw0_wd_in[359]
  PIN rw0_wd_in[360]
    DIRECTION INPUT ;
    USE SIGNAL ;
    SHAPE ABUTMENT ;
    PORT
      LAYER M3 ;
      RECT 26.415 0.000 26.433 0.054 ;
    END
  END rw0_wd_in[360]
  PIN rw0_wd_in[361]
    DIRECTION INPUT ;
    USE SIGNAL ;
    SHAPE ABUTMENT ;
    PORT
      LAYER M3 ;
      RECT 26.667 0.000 26.685 0.054 ;
    END
  END rw0_wd_in[361]
  PIN rw0_wd_in[362]
    DIRECTION INPUT ;
    USE SIGNAL ;
    SHAPE ABUTMENT ;
    PORT
      LAYER M3 ;
      RECT 26.919 0.000 26.937 0.054 ;
    END
  END rw0_wd_in[362]
  PIN rw0_wd_in[363]
    DIRECTION INPUT ;
    USE SIGNAL ;
    SHAPE ABUTMENT ;
    PORT
      LAYER M3 ;
      RECT 27.171 0.000 27.189 0.054 ;
    END
  END rw0_wd_in[363]
  PIN rw0_wd_in[364]
    DIRECTION INPUT ;
    USE SIGNAL ;
    SHAPE ABUTMENT ;
    PORT
      LAYER M3 ;
      RECT 27.423 0.000 27.441 0.054 ;
    END
  END rw0_wd_in[364]
  PIN rw0_wd_in[365]
    DIRECTION INPUT ;
    USE SIGNAL ;
    SHAPE ABUTMENT ;
    PORT
      LAYER M3 ;
      RECT 27.675 0.000 27.693 0.054 ;
    END
  END rw0_wd_in[365]
  PIN rw0_wd_in[366]
    DIRECTION INPUT ;
    USE SIGNAL ;
    SHAPE ABUTMENT ;
    PORT
      LAYER M3 ;
      RECT 27.927 0.000 27.945 0.054 ;
    END
  END rw0_wd_in[366]
  PIN rw0_wd_in[367]
    DIRECTION INPUT ;
    USE SIGNAL ;
    SHAPE ABUTMENT ;
    PORT
      LAYER M3 ;
      RECT 28.179 0.000 28.197 0.054 ;
    END
  END rw0_wd_in[367]
  PIN rw0_wd_in[368]
    DIRECTION INPUT ;
    USE SIGNAL ;
    SHAPE ABUTMENT ;
    PORT
      LAYER M3 ;
      RECT 28.431 0.000 28.449 0.054 ;
    END
  END rw0_wd_in[368]
  PIN rw0_wd_in[369]
    DIRECTION INPUT ;
    USE SIGNAL ;
    SHAPE ABUTMENT ;
    PORT
      LAYER M3 ;
      RECT 28.683 0.000 28.701 0.054 ;
    END
  END rw0_wd_in[369]
  PIN rw0_wd_in[370]
    DIRECTION INPUT ;
    USE SIGNAL ;
    SHAPE ABUTMENT ;
    PORT
      LAYER M3 ;
      RECT 28.935 0.000 28.953 0.054 ;
    END
  END rw0_wd_in[370]
  PIN rw0_wd_in[371]
    DIRECTION INPUT ;
    USE SIGNAL ;
    SHAPE ABUTMENT ;
    PORT
      LAYER M3 ;
      RECT 29.187 0.000 29.205 0.054 ;
    END
  END rw0_wd_in[371]
  PIN rw0_wd_in[372]
    DIRECTION INPUT ;
    USE SIGNAL ;
    SHAPE ABUTMENT ;
    PORT
      LAYER M3 ;
      RECT 29.439 0.000 29.457 0.054 ;
    END
  END rw0_wd_in[372]
  PIN rw0_wd_in[373]
    DIRECTION INPUT ;
    USE SIGNAL ;
    SHAPE ABUTMENT ;
    PORT
      LAYER M3 ;
      RECT 29.691 0.000 29.709 0.054 ;
    END
  END rw0_wd_in[373]
  PIN rw0_wd_in[374]
    DIRECTION INPUT ;
    USE SIGNAL ;
    SHAPE ABUTMENT ;
    PORT
      LAYER M3 ;
      RECT 29.943 0.000 29.961 0.054 ;
    END
  END rw0_wd_in[374]
  PIN rw0_wd_in[375]
    DIRECTION INPUT ;
    USE SIGNAL ;
    SHAPE ABUTMENT ;
    PORT
      LAYER M3 ;
      RECT 30.195 0.000 30.213 0.054 ;
    END
  END rw0_wd_in[375]
  PIN rw0_wd_in[376]
    DIRECTION INPUT ;
    USE SIGNAL ;
    SHAPE ABUTMENT ;
    PORT
      LAYER M3 ;
      RECT 30.447 0.000 30.465 0.054 ;
    END
  END rw0_wd_in[376]
  PIN rw0_wd_in[377]
    DIRECTION INPUT ;
    USE SIGNAL ;
    SHAPE ABUTMENT ;
    PORT
      LAYER M3 ;
      RECT 30.699 0.000 30.717 0.054 ;
    END
  END rw0_wd_in[377]
  PIN rw0_wd_in[378]
    DIRECTION INPUT ;
    USE SIGNAL ;
    SHAPE ABUTMENT ;
    PORT
      LAYER M3 ;
      RECT 30.951 0.000 30.969 0.054 ;
    END
  END rw0_wd_in[378]
  PIN rw0_wd_in[379]
    DIRECTION INPUT ;
    USE SIGNAL ;
    SHAPE ABUTMENT ;
    PORT
      LAYER M3 ;
      RECT 31.203 0.000 31.221 0.054 ;
    END
  END rw0_wd_in[379]
  PIN rw0_wd_in[380]
    DIRECTION INPUT ;
    USE SIGNAL ;
    SHAPE ABUTMENT ;
    PORT
      LAYER M3 ;
      RECT 31.455 0.000 31.473 0.054 ;
    END
  END rw0_wd_in[380]
  PIN rw0_wd_in[381]
    DIRECTION INPUT ;
    USE SIGNAL ;
    SHAPE ABUTMENT ;
    PORT
      LAYER M3 ;
      RECT 31.707 0.000 31.725 0.054 ;
    END
  END rw0_wd_in[381]
  PIN rw0_wd_in[382]
    DIRECTION INPUT ;
    USE SIGNAL ;
    SHAPE ABUTMENT ;
    PORT
      LAYER M3 ;
      RECT 31.959 0.000 31.977 0.054 ;
    END
  END rw0_wd_in[382]
  PIN rw0_wd_in[383]
    DIRECTION INPUT ;
    USE SIGNAL ;
    SHAPE ABUTMENT ;
    PORT
      LAYER M3 ;
      RECT 32.211 0.000 32.229 0.054 ;
    END
  END rw0_wd_in[383]
  PIN rw0_wd_in[384]
    DIRECTION INPUT ;
    USE SIGNAL ;
    SHAPE ABUTMENT ;
    PORT
      LAYER M3 ;
      RECT 32.463 0.000 32.481 0.054 ;
    END
  END rw0_wd_in[384]
  PIN rw0_wd_in[385]
    DIRECTION INPUT ;
    USE SIGNAL ;
    SHAPE ABUTMENT ;
    PORT
      LAYER M3 ;
      RECT 32.715 0.000 32.733 0.054 ;
    END
  END rw0_wd_in[385]
  PIN rw0_wd_in[386]
    DIRECTION INPUT ;
    USE SIGNAL ;
    SHAPE ABUTMENT ;
    PORT
      LAYER M3 ;
      RECT 32.967 0.000 32.985 0.054 ;
    END
  END rw0_wd_in[386]
  PIN rw0_wd_in[387]
    DIRECTION INPUT ;
    USE SIGNAL ;
    SHAPE ABUTMENT ;
    PORT
      LAYER M3 ;
      RECT 33.219 0.000 33.237 0.054 ;
    END
  END rw0_wd_in[387]
  PIN rw0_wd_in[388]
    DIRECTION INPUT ;
    USE SIGNAL ;
    SHAPE ABUTMENT ;
    PORT
      LAYER M3 ;
      RECT 33.471 0.000 33.489 0.054 ;
    END
  END rw0_wd_in[388]
  PIN rw0_wd_in[389]
    DIRECTION INPUT ;
    USE SIGNAL ;
    SHAPE ABUTMENT ;
    PORT
      LAYER M3 ;
      RECT 33.723 0.000 33.741 0.054 ;
    END
  END rw0_wd_in[389]
  PIN rw0_wd_in[390]
    DIRECTION INPUT ;
    USE SIGNAL ;
    SHAPE ABUTMENT ;
    PORT
      LAYER M3 ;
      RECT 33.975 0.000 33.993 0.054 ;
    END
  END rw0_wd_in[390]
  PIN rw0_wd_in[391]
    DIRECTION INPUT ;
    USE SIGNAL ;
    SHAPE ABUTMENT ;
    PORT
      LAYER M3 ;
      RECT 34.227 0.000 34.245 0.054 ;
    END
  END rw0_wd_in[391]
  PIN rw0_wd_in[392]
    DIRECTION INPUT ;
    USE SIGNAL ;
    SHAPE ABUTMENT ;
    PORT
      LAYER M3 ;
      RECT 34.479 0.000 34.497 0.054 ;
    END
  END rw0_wd_in[392]
  PIN rw0_wd_in[393]
    DIRECTION INPUT ;
    USE SIGNAL ;
    SHAPE ABUTMENT ;
    PORT
      LAYER M3 ;
      RECT 34.731 0.000 34.749 0.054 ;
    END
  END rw0_wd_in[393]
  PIN rw0_wd_in[394]
    DIRECTION INPUT ;
    USE SIGNAL ;
    SHAPE ABUTMENT ;
    PORT
      LAYER M3 ;
      RECT 34.983 0.000 35.001 0.054 ;
    END
  END rw0_wd_in[394]
  PIN rw0_wd_in[395]
    DIRECTION INPUT ;
    USE SIGNAL ;
    SHAPE ABUTMENT ;
    PORT
      LAYER M3 ;
      RECT 35.235 0.000 35.253 0.054 ;
    END
  END rw0_wd_in[395]
  PIN rw0_wd_in[396]
    DIRECTION INPUT ;
    USE SIGNAL ;
    SHAPE ABUTMENT ;
    PORT
      LAYER M3 ;
      RECT 35.487 0.000 35.505 0.054 ;
    END
  END rw0_wd_in[396]
  PIN rw0_wd_in[397]
    DIRECTION INPUT ;
    USE SIGNAL ;
    SHAPE ABUTMENT ;
    PORT
      LAYER M3 ;
      RECT 35.739 0.000 35.757 0.054 ;
    END
  END rw0_wd_in[397]
  PIN rw0_wd_in[398]
    DIRECTION INPUT ;
    USE SIGNAL ;
    SHAPE ABUTMENT ;
    PORT
      LAYER M3 ;
      RECT 35.991 0.000 36.009 0.054 ;
    END
  END rw0_wd_in[398]
  PIN rw0_wd_in[399]
    DIRECTION INPUT ;
    USE SIGNAL ;
    SHAPE ABUTMENT ;
    PORT
      LAYER M3 ;
      RECT 36.243 0.000 36.261 0.054 ;
    END
  END rw0_wd_in[399]
  PIN rw0_wd_in[400]
    DIRECTION INPUT ;
    USE SIGNAL ;
    SHAPE ABUTMENT ;
    PORT
      LAYER M3 ;
      RECT 36.495 0.000 36.513 0.054 ;
    END
  END rw0_wd_in[400]
  PIN rw0_wd_in[401]
    DIRECTION INPUT ;
    USE SIGNAL ;
    SHAPE ABUTMENT ;
    PORT
      LAYER M3 ;
      RECT 36.747 0.000 36.765 0.054 ;
    END
  END rw0_wd_in[401]
  PIN rw0_wd_in[402]
    DIRECTION INPUT ;
    USE SIGNAL ;
    SHAPE ABUTMENT ;
    PORT
      LAYER M3 ;
      RECT 36.999 0.000 37.017 0.054 ;
    END
  END rw0_wd_in[402]
  PIN rw0_wd_in[403]
    DIRECTION INPUT ;
    USE SIGNAL ;
    SHAPE ABUTMENT ;
    PORT
      LAYER M3 ;
      RECT 37.251 0.000 37.269 0.054 ;
    END
  END rw0_wd_in[403]
  PIN rw0_wd_in[404]
    DIRECTION INPUT ;
    USE SIGNAL ;
    SHAPE ABUTMENT ;
    PORT
      LAYER M3 ;
      RECT 37.503 0.000 37.521 0.054 ;
    END
  END rw0_wd_in[404]
  PIN rw0_wd_in[405]
    DIRECTION INPUT ;
    USE SIGNAL ;
    SHAPE ABUTMENT ;
    PORT
      LAYER M3 ;
      RECT 37.755 0.000 37.773 0.054 ;
    END
  END rw0_wd_in[405]
  PIN rw0_wd_in[406]
    DIRECTION INPUT ;
    USE SIGNAL ;
    SHAPE ABUTMENT ;
    PORT
      LAYER M3 ;
      RECT 38.007 0.000 38.025 0.054 ;
    END
  END rw0_wd_in[406]
  PIN rw0_wd_in[407]
    DIRECTION INPUT ;
    USE SIGNAL ;
    SHAPE ABUTMENT ;
    PORT
      LAYER M3 ;
      RECT 38.259 0.000 38.277 0.054 ;
    END
  END rw0_wd_in[407]
  PIN rw0_wd_in[408]
    DIRECTION INPUT ;
    USE SIGNAL ;
    SHAPE ABUTMENT ;
    PORT
      LAYER M3 ;
      RECT 38.511 0.000 38.529 0.054 ;
    END
  END rw0_wd_in[408]
  PIN rw0_wd_in[409]
    DIRECTION INPUT ;
    USE SIGNAL ;
    SHAPE ABUTMENT ;
    PORT
      LAYER M3 ;
      RECT 38.763 0.000 38.781 0.054 ;
    END
  END rw0_wd_in[409]
  PIN rw0_wd_in[410]
    DIRECTION INPUT ;
    USE SIGNAL ;
    SHAPE ABUTMENT ;
    PORT
      LAYER M3 ;
      RECT 39.015 0.000 39.033 0.054 ;
    END
  END rw0_wd_in[410]
  PIN rw0_wd_in[411]
    DIRECTION INPUT ;
    USE SIGNAL ;
    SHAPE ABUTMENT ;
    PORT
      LAYER M3 ;
      RECT 39.267 0.000 39.285 0.054 ;
    END
  END rw0_wd_in[411]
  PIN rw0_wd_in[412]
    DIRECTION INPUT ;
    USE SIGNAL ;
    SHAPE ABUTMENT ;
    PORT
      LAYER M3 ;
      RECT 39.519 0.000 39.537 0.054 ;
    END
  END rw0_wd_in[412]
  PIN rw0_wd_in[413]
    DIRECTION INPUT ;
    USE SIGNAL ;
    SHAPE ABUTMENT ;
    PORT
      LAYER M3 ;
      RECT 39.771 0.000 39.789 0.054 ;
    END
  END rw0_wd_in[413]
  PIN rw0_wd_in[414]
    DIRECTION INPUT ;
    USE SIGNAL ;
    SHAPE ABUTMENT ;
    PORT
      LAYER M3 ;
      RECT 40.023 0.000 40.041 0.054 ;
    END
  END rw0_wd_in[414]
  PIN rw0_wd_in[415]
    DIRECTION INPUT ;
    USE SIGNAL ;
    SHAPE ABUTMENT ;
    PORT
      LAYER M3 ;
      RECT 40.275 0.000 40.293 0.054 ;
    END
  END rw0_wd_in[415]
  PIN rw0_wd_in[416]
    DIRECTION INPUT ;
    USE SIGNAL ;
    SHAPE ABUTMENT ;
    PORT
      LAYER M3 ;
      RECT 40.527 0.000 40.545 0.054 ;
    END
  END rw0_wd_in[416]
  PIN rw0_wd_in[417]
    DIRECTION INPUT ;
    USE SIGNAL ;
    SHAPE ABUTMENT ;
    PORT
      LAYER M3 ;
      RECT 40.779 0.000 40.797 0.054 ;
    END
  END rw0_wd_in[417]
  PIN rw0_wd_in[418]
    DIRECTION INPUT ;
    USE SIGNAL ;
    SHAPE ABUTMENT ;
    PORT
      LAYER M3 ;
      RECT 41.031 0.000 41.049 0.054 ;
    END
  END rw0_wd_in[418]
  PIN rw0_wd_in[419]
    DIRECTION INPUT ;
    USE SIGNAL ;
    SHAPE ABUTMENT ;
    PORT
      LAYER M3 ;
      RECT 41.283 0.000 41.301 0.054 ;
    END
  END rw0_wd_in[419]
  PIN rw0_wd_in[420]
    DIRECTION INPUT ;
    USE SIGNAL ;
    SHAPE ABUTMENT ;
    PORT
      LAYER M3 ;
      RECT 41.535 0.000 41.553 0.054 ;
    END
  END rw0_wd_in[420]
  PIN rw0_wd_in[421]
    DIRECTION INPUT ;
    USE SIGNAL ;
    SHAPE ABUTMENT ;
    PORT
      LAYER M3 ;
      RECT 41.787 0.000 41.805 0.054 ;
    END
  END rw0_wd_in[421]
  PIN rw0_wd_in[422]
    DIRECTION INPUT ;
    USE SIGNAL ;
    SHAPE ABUTMENT ;
    PORT
      LAYER M3 ;
      RECT 42.039 0.000 42.057 0.054 ;
    END
  END rw0_wd_in[422]
  PIN rw0_wd_in[423]
    DIRECTION INPUT ;
    USE SIGNAL ;
    SHAPE ABUTMENT ;
    PORT
      LAYER M3 ;
      RECT 42.291 0.000 42.309 0.054 ;
    END
  END rw0_wd_in[423]
  PIN rw0_wd_in[424]
    DIRECTION INPUT ;
    USE SIGNAL ;
    SHAPE ABUTMENT ;
    PORT
      LAYER M3 ;
      RECT 42.543 0.000 42.561 0.054 ;
    END
  END rw0_wd_in[424]
  PIN rw0_wd_in[425]
    DIRECTION INPUT ;
    USE SIGNAL ;
    SHAPE ABUTMENT ;
    PORT
      LAYER M3 ;
      RECT 42.795 0.000 42.813 0.054 ;
    END
  END rw0_wd_in[425]
  PIN rw0_wd_in[426]
    DIRECTION INPUT ;
    USE SIGNAL ;
    SHAPE ABUTMENT ;
    PORT
      LAYER M3 ;
      RECT 43.047 0.000 43.065 0.054 ;
    END
  END rw0_wd_in[426]
  PIN rw0_wd_in[427]
    DIRECTION INPUT ;
    USE SIGNAL ;
    SHAPE ABUTMENT ;
    PORT
      LAYER M3 ;
      RECT 43.299 0.000 43.317 0.054 ;
    END
  END rw0_wd_in[427]
  PIN rw0_wd_in[428]
    DIRECTION INPUT ;
    USE SIGNAL ;
    SHAPE ABUTMENT ;
    PORT
      LAYER M3 ;
      RECT 43.551 0.000 43.569 0.054 ;
    END
  END rw0_wd_in[428]
  PIN rw0_wd_in[429]
    DIRECTION INPUT ;
    USE SIGNAL ;
    SHAPE ABUTMENT ;
    PORT
      LAYER M3 ;
      RECT 43.803 0.000 43.821 0.054 ;
    END
  END rw0_wd_in[429]
  PIN rw0_wd_in[430]
    DIRECTION INPUT ;
    USE SIGNAL ;
    SHAPE ABUTMENT ;
    PORT
      LAYER M3 ;
      RECT 44.055 0.000 44.073 0.054 ;
    END
  END rw0_wd_in[430]
  PIN rw0_wd_in[431]
    DIRECTION INPUT ;
    USE SIGNAL ;
    SHAPE ABUTMENT ;
    PORT
      LAYER M3 ;
      RECT 44.307 0.000 44.325 0.054 ;
    END
  END rw0_wd_in[431]
  PIN rw0_wd_in[432]
    DIRECTION INPUT ;
    USE SIGNAL ;
    SHAPE ABUTMENT ;
    PORT
      LAYER M3 ;
      RECT 44.559 0.000 44.577 0.054 ;
    END
  END rw0_wd_in[432]
  PIN rw0_wd_in[433]
    DIRECTION INPUT ;
    USE SIGNAL ;
    SHAPE ABUTMENT ;
    PORT
      LAYER M3 ;
      RECT 44.811 0.000 44.829 0.054 ;
    END
  END rw0_wd_in[433]
  PIN rw0_wd_in[434]
    DIRECTION INPUT ;
    USE SIGNAL ;
    SHAPE ABUTMENT ;
    PORT
      LAYER M3 ;
      RECT 45.063 0.000 45.081 0.054 ;
    END
  END rw0_wd_in[434]
  PIN rw0_wd_in[435]
    DIRECTION INPUT ;
    USE SIGNAL ;
    SHAPE ABUTMENT ;
    PORT
      LAYER M3 ;
      RECT 45.315 0.000 45.333 0.054 ;
    END
  END rw0_wd_in[435]
  PIN rw0_wd_in[436]
    DIRECTION INPUT ;
    USE SIGNAL ;
    SHAPE ABUTMENT ;
    PORT
      LAYER M3 ;
      RECT 45.567 0.000 45.585 0.054 ;
    END
  END rw0_wd_in[436]
  PIN rw0_wd_in[437]
    DIRECTION INPUT ;
    USE SIGNAL ;
    SHAPE ABUTMENT ;
    PORT
      LAYER M3 ;
      RECT 45.819 0.000 45.837 0.054 ;
    END
  END rw0_wd_in[437]
  PIN rw0_wd_in[438]
    DIRECTION INPUT ;
    USE SIGNAL ;
    SHAPE ABUTMENT ;
    PORT
      LAYER M3 ;
      RECT 46.071 0.000 46.089 0.054 ;
    END
  END rw0_wd_in[438]
  PIN rw0_wd_in[439]
    DIRECTION INPUT ;
    USE SIGNAL ;
    SHAPE ABUTMENT ;
    PORT
      LAYER M3 ;
      RECT 46.323 0.000 46.341 0.054 ;
    END
  END rw0_wd_in[439]
  PIN rw0_wd_in[440]
    DIRECTION INPUT ;
    USE SIGNAL ;
    SHAPE ABUTMENT ;
    PORT
      LAYER M3 ;
      RECT 46.575 0.000 46.593 0.054 ;
    END
  END rw0_wd_in[440]
  PIN rw0_wd_in[441]
    DIRECTION INPUT ;
    USE SIGNAL ;
    SHAPE ABUTMENT ;
    PORT
      LAYER M3 ;
      RECT 46.827 0.000 46.845 0.054 ;
    END
  END rw0_wd_in[441]
  PIN rw0_wd_in[442]
    DIRECTION INPUT ;
    USE SIGNAL ;
    SHAPE ABUTMENT ;
    PORT
      LAYER M3 ;
      RECT 47.079 0.000 47.097 0.054 ;
    END
  END rw0_wd_in[442]
  PIN rw0_wd_in[443]
    DIRECTION INPUT ;
    USE SIGNAL ;
    SHAPE ABUTMENT ;
    PORT
      LAYER M3 ;
      RECT 47.331 0.000 47.349 0.054 ;
    END
  END rw0_wd_in[443]
  PIN rw0_wd_in[444]
    DIRECTION INPUT ;
    USE SIGNAL ;
    SHAPE ABUTMENT ;
    PORT
      LAYER M3 ;
      RECT 47.583 0.000 47.601 0.054 ;
    END
  END rw0_wd_in[444]
  PIN rw0_wd_in[445]
    DIRECTION INPUT ;
    USE SIGNAL ;
    SHAPE ABUTMENT ;
    PORT
      LAYER M3 ;
      RECT 47.835 0.000 47.853 0.054 ;
    END
  END rw0_wd_in[445]
  PIN rw0_wd_in[446]
    DIRECTION INPUT ;
    USE SIGNAL ;
    SHAPE ABUTMENT ;
    PORT
      LAYER M3 ;
      RECT 48.087 0.000 48.105 0.054 ;
    END
  END rw0_wd_in[446]
  PIN rw0_wd_in[447]
    DIRECTION INPUT ;
    USE SIGNAL ;
    SHAPE ABUTMENT ;
    PORT
      LAYER M3 ;
      RECT 48.339 0.000 48.357 0.054 ;
    END
  END rw0_wd_in[447]
  PIN rw0_wd_in[448]
    DIRECTION INPUT ;
    USE SIGNAL ;
    SHAPE ABUTMENT ;
    PORT
      LAYER M3 ;
      RECT 48.591 0.000 48.609 0.054 ;
    END
  END rw0_wd_in[448]
  PIN rw0_wd_in[449]
    DIRECTION INPUT ;
    USE SIGNAL ;
    SHAPE ABUTMENT ;
    PORT
      LAYER M3 ;
      RECT 48.843 0.000 48.861 0.054 ;
    END
  END rw0_wd_in[449]
  PIN rw0_wd_in[450]
    DIRECTION INPUT ;
    USE SIGNAL ;
    SHAPE ABUTMENT ;
    PORT
      LAYER M3 ;
      RECT 49.095 0.000 49.113 0.054 ;
    END
  END rw0_wd_in[450]
  PIN rw0_wd_in[451]
    DIRECTION INPUT ;
    USE SIGNAL ;
    SHAPE ABUTMENT ;
    PORT
      LAYER M3 ;
      RECT 49.347 0.000 49.365 0.054 ;
    END
  END rw0_wd_in[451]
  PIN rw0_wd_in[452]
    DIRECTION INPUT ;
    USE SIGNAL ;
    SHAPE ABUTMENT ;
    PORT
      LAYER M3 ;
      RECT 49.599 0.000 49.617 0.054 ;
    END
  END rw0_wd_in[452]
  PIN rw0_wd_in[453]
    DIRECTION INPUT ;
    USE SIGNAL ;
    SHAPE ABUTMENT ;
    PORT
      LAYER M3 ;
      RECT 49.851 0.000 49.869 0.054 ;
    END
  END rw0_wd_in[453]
  PIN rw0_wd_in[454]
    DIRECTION INPUT ;
    USE SIGNAL ;
    SHAPE ABUTMENT ;
    PORT
      LAYER M3 ;
      RECT 50.103 0.000 50.121 0.054 ;
    END
  END rw0_wd_in[454]
  PIN rw0_wd_in[455]
    DIRECTION INPUT ;
    USE SIGNAL ;
    SHAPE ABUTMENT ;
    PORT
      LAYER M3 ;
      RECT 50.355 0.000 50.373 0.054 ;
    END
  END rw0_wd_in[455]
  PIN rw0_wd_in[456]
    DIRECTION INPUT ;
    USE SIGNAL ;
    SHAPE ABUTMENT ;
    PORT
      LAYER M3 ;
      RECT 50.607 0.000 50.625 0.054 ;
    END
  END rw0_wd_in[456]
  PIN rw0_wd_in[457]
    DIRECTION INPUT ;
    USE SIGNAL ;
    SHAPE ABUTMENT ;
    PORT
      LAYER M3 ;
      RECT 50.859 0.000 50.877 0.054 ;
    END
  END rw0_wd_in[457]
  PIN rw0_wd_in[458]
    DIRECTION INPUT ;
    USE SIGNAL ;
    SHAPE ABUTMENT ;
    PORT
      LAYER M3 ;
      RECT 51.111 0.000 51.129 0.054 ;
    END
  END rw0_wd_in[458]
  PIN rw0_wd_in[459]
    DIRECTION INPUT ;
    USE SIGNAL ;
    SHAPE ABUTMENT ;
    PORT
      LAYER M3 ;
      RECT 51.363 0.000 51.381 0.054 ;
    END
  END rw0_wd_in[459]
  PIN rw0_wd_in[460]
    DIRECTION INPUT ;
    USE SIGNAL ;
    SHAPE ABUTMENT ;
    PORT
      LAYER M3 ;
      RECT 51.615 0.000 51.633 0.054 ;
    END
  END rw0_wd_in[460]
  PIN rw0_wd_in[461]
    DIRECTION INPUT ;
    USE SIGNAL ;
    SHAPE ABUTMENT ;
    PORT
      LAYER M3 ;
      RECT 51.867 0.000 51.885 0.054 ;
    END
  END rw0_wd_in[461]
  PIN rw0_wd_in[462]
    DIRECTION INPUT ;
    USE SIGNAL ;
    SHAPE ABUTMENT ;
    PORT
      LAYER M3 ;
      RECT 52.119 0.000 52.137 0.054 ;
    END
  END rw0_wd_in[462]
  PIN rw0_wd_in[463]
    DIRECTION INPUT ;
    USE SIGNAL ;
    SHAPE ABUTMENT ;
    PORT
      LAYER M3 ;
      RECT 52.371 0.000 52.389 0.054 ;
    END
  END rw0_wd_in[463]
  PIN rw0_wd_in[464]
    DIRECTION INPUT ;
    USE SIGNAL ;
    SHAPE ABUTMENT ;
    PORT
      LAYER M3 ;
      RECT 52.623 0.000 52.641 0.054 ;
    END
  END rw0_wd_in[464]
  PIN rw0_wd_in[465]
    DIRECTION INPUT ;
    USE SIGNAL ;
    SHAPE ABUTMENT ;
    PORT
      LAYER M3 ;
      RECT 52.875 0.000 52.893 0.054 ;
    END
  END rw0_wd_in[465]
  PIN rw0_wd_in[466]
    DIRECTION INPUT ;
    USE SIGNAL ;
    SHAPE ABUTMENT ;
    PORT
      LAYER M3 ;
      RECT 53.127 0.000 53.145 0.054 ;
    END
  END rw0_wd_in[466]
  PIN rw0_wd_in[467]
    DIRECTION INPUT ;
    USE SIGNAL ;
    SHAPE ABUTMENT ;
    PORT
      LAYER M3 ;
      RECT 53.379 0.000 53.397 0.054 ;
    END
  END rw0_wd_in[467]
  PIN rw0_wd_in[468]
    DIRECTION INPUT ;
    USE SIGNAL ;
    SHAPE ABUTMENT ;
    PORT
      LAYER M3 ;
      RECT 53.631 0.000 53.649 0.054 ;
    END
  END rw0_wd_in[468]
  PIN rw0_wd_in[469]
    DIRECTION INPUT ;
    USE SIGNAL ;
    SHAPE ABUTMENT ;
    PORT
      LAYER M3 ;
      RECT 53.883 0.000 53.901 0.054 ;
    END
  END rw0_wd_in[469]
  PIN rw0_wd_in[470]
    DIRECTION INPUT ;
    USE SIGNAL ;
    SHAPE ABUTMENT ;
    PORT
      LAYER M3 ;
      RECT 54.135 0.000 54.153 0.054 ;
    END
  END rw0_wd_in[470]
  PIN rw0_wd_in[471]
    DIRECTION INPUT ;
    USE SIGNAL ;
    SHAPE ABUTMENT ;
    PORT
      LAYER M3 ;
      RECT 54.387 0.000 54.405 0.054 ;
    END
  END rw0_wd_in[471]
  PIN rw0_wd_in[472]
    DIRECTION INPUT ;
    USE SIGNAL ;
    SHAPE ABUTMENT ;
    PORT
      LAYER M3 ;
      RECT 54.639 0.000 54.657 0.054 ;
    END
  END rw0_wd_in[472]
  PIN rw0_wd_in[473]
    DIRECTION INPUT ;
    USE SIGNAL ;
    SHAPE ABUTMENT ;
    PORT
      LAYER M3 ;
      RECT 54.891 0.000 54.909 0.054 ;
    END
  END rw0_wd_in[473]
  PIN rw0_wd_in[474]
    DIRECTION INPUT ;
    USE SIGNAL ;
    SHAPE ABUTMENT ;
    PORT
      LAYER M3 ;
      RECT 55.143 0.000 55.161 0.054 ;
    END
  END rw0_wd_in[474]
  PIN rw0_wd_in[475]
    DIRECTION INPUT ;
    USE SIGNAL ;
    SHAPE ABUTMENT ;
    PORT
      LAYER M3 ;
      RECT 55.395 0.000 55.413 0.054 ;
    END
  END rw0_wd_in[475]
  PIN rw0_wd_in[476]
    DIRECTION INPUT ;
    USE SIGNAL ;
    SHAPE ABUTMENT ;
    PORT
      LAYER M3 ;
      RECT 55.647 0.000 55.665 0.054 ;
    END
  END rw0_wd_in[476]
  PIN rw0_wd_in[477]
    DIRECTION INPUT ;
    USE SIGNAL ;
    SHAPE ABUTMENT ;
    PORT
      LAYER M3 ;
      RECT 55.899 0.000 55.917 0.054 ;
    END
  END rw0_wd_in[477]
  PIN rw0_wd_in[478]
    DIRECTION INPUT ;
    USE SIGNAL ;
    SHAPE ABUTMENT ;
    PORT
      LAYER M3 ;
      RECT 56.151 0.000 56.169 0.054 ;
    END
  END rw0_wd_in[478]
  PIN rw0_wd_in[479]
    DIRECTION INPUT ;
    USE SIGNAL ;
    SHAPE ABUTMENT ;
    PORT
      LAYER M3 ;
      RECT 56.403 0.000 56.421 0.054 ;
    END
  END rw0_wd_in[479]
  PIN rw0_wd_in[480]
    DIRECTION INPUT ;
    USE SIGNAL ;
    SHAPE ABUTMENT ;
    PORT
      LAYER M3 ;
      RECT 56.655 0.000 56.673 0.054 ;
    END
  END rw0_wd_in[480]
  PIN rw0_wd_in[481]
    DIRECTION INPUT ;
    USE SIGNAL ;
    SHAPE ABUTMENT ;
    PORT
      LAYER M3 ;
      RECT 56.907 0.000 56.925 0.054 ;
    END
  END rw0_wd_in[481]
  PIN rw0_wd_in[482]
    DIRECTION INPUT ;
    USE SIGNAL ;
    SHAPE ABUTMENT ;
    PORT
      LAYER M3 ;
      RECT 57.159 0.000 57.177 0.054 ;
    END
  END rw0_wd_in[482]
  PIN rw0_wd_in[483]
    DIRECTION INPUT ;
    USE SIGNAL ;
    SHAPE ABUTMENT ;
    PORT
      LAYER M3 ;
      RECT 57.411 0.000 57.429 0.054 ;
    END
  END rw0_wd_in[483]
  PIN rw0_wd_in[484]
    DIRECTION INPUT ;
    USE SIGNAL ;
    SHAPE ABUTMENT ;
    PORT
      LAYER M3 ;
      RECT 57.663 0.000 57.681 0.054 ;
    END
  END rw0_wd_in[484]
  PIN rw0_wd_in[485]
    DIRECTION INPUT ;
    USE SIGNAL ;
    SHAPE ABUTMENT ;
    PORT
      LAYER M3 ;
      RECT 57.915 0.000 57.933 0.054 ;
    END
  END rw0_wd_in[485]
  PIN rw0_wd_in[486]
    DIRECTION INPUT ;
    USE SIGNAL ;
    SHAPE ABUTMENT ;
    PORT
      LAYER M3 ;
      RECT 58.167 0.000 58.185 0.054 ;
    END
  END rw0_wd_in[486]
  PIN rw0_wd_in[487]
    DIRECTION INPUT ;
    USE SIGNAL ;
    SHAPE ABUTMENT ;
    PORT
      LAYER M3 ;
      RECT 58.419 0.000 58.437 0.054 ;
    END
  END rw0_wd_in[487]
  PIN rw0_wd_in[488]
    DIRECTION INPUT ;
    USE SIGNAL ;
    SHAPE ABUTMENT ;
    PORT
      LAYER M3 ;
      RECT 58.671 0.000 58.689 0.054 ;
    END
  END rw0_wd_in[488]
  PIN rw0_wd_in[489]
    DIRECTION INPUT ;
    USE SIGNAL ;
    SHAPE ABUTMENT ;
    PORT
      LAYER M3 ;
      RECT 58.923 0.000 58.941 0.054 ;
    END
  END rw0_wd_in[489]
  PIN rw0_wd_in[490]
    DIRECTION INPUT ;
    USE SIGNAL ;
    SHAPE ABUTMENT ;
    PORT
      LAYER M3 ;
      RECT 59.175 0.000 59.193 0.054 ;
    END
  END rw0_wd_in[490]
  PIN rw0_wd_in[491]
    DIRECTION INPUT ;
    USE SIGNAL ;
    SHAPE ABUTMENT ;
    PORT
      LAYER M3 ;
      RECT 59.427 0.000 59.445 0.054 ;
    END
  END rw0_wd_in[491]
  PIN rw0_wd_in[492]
    DIRECTION INPUT ;
    USE SIGNAL ;
    SHAPE ABUTMENT ;
    PORT
      LAYER M3 ;
      RECT 59.679 0.000 59.697 0.054 ;
    END
  END rw0_wd_in[492]
  PIN rw0_wd_in[493]
    DIRECTION INPUT ;
    USE SIGNAL ;
    SHAPE ABUTMENT ;
    PORT
      LAYER M3 ;
      RECT 59.931 0.000 59.949 0.054 ;
    END
  END rw0_wd_in[493]
  PIN rw0_wd_in[494]
    DIRECTION INPUT ;
    USE SIGNAL ;
    SHAPE ABUTMENT ;
    PORT
      LAYER M3 ;
      RECT 60.183 0.000 60.201 0.054 ;
    END
  END rw0_wd_in[494]
  PIN rw0_wd_in[495]
    DIRECTION INPUT ;
    USE SIGNAL ;
    SHAPE ABUTMENT ;
    PORT
      LAYER M3 ;
      RECT 60.435 0.000 60.453 0.054 ;
    END
  END rw0_wd_in[495]
  PIN rw0_wd_in[496]
    DIRECTION INPUT ;
    USE SIGNAL ;
    SHAPE ABUTMENT ;
    PORT
      LAYER M3 ;
      RECT 60.687 0.000 60.705 0.054 ;
    END
  END rw0_wd_in[496]
  PIN rw0_wd_in[497]
    DIRECTION INPUT ;
    USE SIGNAL ;
    SHAPE ABUTMENT ;
    PORT
      LAYER M3 ;
      RECT 60.939 0.000 60.957 0.054 ;
    END
  END rw0_wd_in[497]
  PIN rw0_wd_in[498]
    DIRECTION INPUT ;
    USE SIGNAL ;
    SHAPE ABUTMENT ;
    PORT
      LAYER M3 ;
      RECT 61.191 0.000 61.209 0.054 ;
    END
  END rw0_wd_in[498]
  PIN rw0_wd_in[499]
    DIRECTION INPUT ;
    USE SIGNAL ;
    SHAPE ABUTMENT ;
    PORT
      LAYER M3 ;
      RECT 61.443 0.000 61.461 0.054 ;
    END
  END rw0_wd_in[499]
  PIN rw0_wd_in[500]
    DIRECTION INPUT ;
    USE SIGNAL ;
    SHAPE ABUTMENT ;
    PORT
      LAYER M3 ;
      RECT 61.695 0.000 61.713 0.054 ;
    END
  END rw0_wd_in[500]
  PIN rw0_wd_in[501]
    DIRECTION INPUT ;
    USE SIGNAL ;
    SHAPE ABUTMENT ;
    PORT
      LAYER M3 ;
      RECT 61.947 0.000 61.965 0.054 ;
    END
  END rw0_wd_in[501]
  PIN rw0_wd_in[502]
    DIRECTION INPUT ;
    USE SIGNAL ;
    SHAPE ABUTMENT ;
    PORT
      LAYER M3 ;
      RECT 62.199 0.000 62.217 0.054 ;
    END
  END rw0_wd_in[502]
  PIN rw0_wd_in[503]
    DIRECTION INPUT ;
    USE SIGNAL ;
    SHAPE ABUTMENT ;
    PORT
      LAYER M3 ;
      RECT 62.451 0.000 62.469 0.054 ;
    END
  END rw0_wd_in[503]
  PIN rw0_wd_in[504]
    DIRECTION INPUT ;
    USE SIGNAL ;
    SHAPE ABUTMENT ;
    PORT
      LAYER M3 ;
      RECT 62.703 0.000 62.721 0.054 ;
    END
  END rw0_wd_in[504]
  PIN rw0_wd_in[505]
    DIRECTION INPUT ;
    USE SIGNAL ;
    SHAPE ABUTMENT ;
    PORT
      LAYER M3 ;
      RECT 62.955 0.000 62.973 0.054 ;
    END
  END rw0_wd_in[505]
  PIN rw0_wd_in[506]
    DIRECTION INPUT ;
    USE SIGNAL ;
    SHAPE ABUTMENT ;
    PORT
      LAYER M3 ;
      RECT 63.207 0.000 63.225 0.054 ;
    END
  END rw0_wd_in[506]
  PIN rw0_wd_in[507]
    DIRECTION INPUT ;
    USE SIGNAL ;
    SHAPE ABUTMENT ;
    PORT
      LAYER M3 ;
      RECT 63.459 0.000 63.477 0.054 ;
    END
  END rw0_wd_in[507]
  PIN rw0_wd_in[508]
    DIRECTION INPUT ;
    USE SIGNAL ;
    SHAPE ABUTMENT ;
    PORT
      LAYER M3 ;
      RECT 63.711 0.000 63.729 0.054 ;
    END
  END rw0_wd_in[508]
  PIN rw0_wd_in[509]
    DIRECTION INPUT ;
    USE SIGNAL ;
    SHAPE ABUTMENT ;
    PORT
      LAYER M3 ;
      RECT 63.963 0.000 63.981 0.054 ;
    END
  END rw0_wd_in[509]
  PIN rw0_wd_in[510]
    DIRECTION INPUT ;
    USE SIGNAL ;
    SHAPE ABUTMENT ;
    PORT
      LAYER M3 ;
      RECT 64.215 0.000 64.233 0.054 ;
    END
  END rw0_wd_in[510]
  PIN rw0_wd_in[511]
    DIRECTION INPUT ;
    USE SIGNAL ;
    SHAPE ABUTMENT ;
    PORT
      LAYER M3 ;
      RECT 64.467 0.000 64.485 0.054 ;
    END
  END rw0_wd_in[511]
  PIN rw0_rd_out[0]
    DIRECTION OUTPUT ;
    USE SIGNAL ;
    SHAPE ABUTMENT ;
    PORT
      LAYER M3 ;
      RECT 64.719 0.000 64.737 0.054 ;
    END
  END rw0_rd_out[0]
  PIN rw0_rd_out[1]
    DIRECTION OUTPUT ;
    USE SIGNAL ;
    SHAPE ABUTMENT ;
    PORT
      LAYER M3 ;
      RECT 64.971 0.000 64.989 0.054 ;
    END
  END rw0_rd_out[1]
  PIN rw0_rd_out[2]
    DIRECTION OUTPUT ;
    USE SIGNAL ;
    SHAPE ABUTMENT ;
    PORT
      LAYER M3 ;
      RECT 65.223 0.000 65.241 0.054 ;
    END
  END rw0_rd_out[2]
  PIN rw0_rd_out[3]
    DIRECTION OUTPUT ;
    USE SIGNAL ;
    SHAPE ABUTMENT ;
    PORT
      LAYER M3 ;
      RECT 65.475 0.000 65.493 0.054 ;
    END
  END rw0_rd_out[3]
  PIN rw0_rd_out[4]
    DIRECTION OUTPUT ;
    USE SIGNAL ;
    SHAPE ABUTMENT ;
    PORT
      LAYER M3 ;
      RECT 65.727 0.000 65.745 0.054 ;
    END
  END rw0_rd_out[4]
  PIN rw0_rd_out[5]
    DIRECTION OUTPUT ;
    USE SIGNAL ;
    SHAPE ABUTMENT ;
    PORT
      LAYER M3 ;
      RECT 65.979 0.000 65.997 0.054 ;
    END
  END rw0_rd_out[5]
  PIN rw0_rd_out[6]
    DIRECTION OUTPUT ;
    USE SIGNAL ;
    SHAPE ABUTMENT ;
    PORT
      LAYER M3 ;
      RECT 66.231 0.000 66.249 0.054 ;
    END
  END rw0_rd_out[6]
  PIN rw0_rd_out[7]
    DIRECTION OUTPUT ;
    USE SIGNAL ;
    SHAPE ABUTMENT ;
    PORT
      LAYER M3 ;
      RECT 66.483 0.000 66.501 0.054 ;
    END
  END rw0_rd_out[7]
  PIN rw0_rd_out[8]
    DIRECTION OUTPUT ;
    USE SIGNAL ;
    SHAPE ABUTMENT ;
    PORT
      LAYER M3 ;
      RECT 66.735 0.000 66.753 0.054 ;
    END
  END rw0_rd_out[8]
  PIN rw0_rd_out[9]
    DIRECTION OUTPUT ;
    USE SIGNAL ;
    SHAPE ABUTMENT ;
    PORT
      LAYER M3 ;
      RECT 66.987 0.000 67.005 0.054 ;
    END
  END rw0_rd_out[9]
  PIN rw0_rd_out[10]
    DIRECTION OUTPUT ;
    USE SIGNAL ;
    SHAPE ABUTMENT ;
    PORT
      LAYER M3 ;
      RECT 67.239 0.000 67.257 0.054 ;
    END
  END rw0_rd_out[10]
  PIN rw0_rd_out[11]
    DIRECTION OUTPUT ;
    USE SIGNAL ;
    SHAPE ABUTMENT ;
    PORT
      LAYER M3 ;
      RECT 67.491 0.000 67.509 0.054 ;
    END
  END rw0_rd_out[11]
  PIN rw0_rd_out[12]
    DIRECTION OUTPUT ;
    USE SIGNAL ;
    SHAPE ABUTMENT ;
    PORT
      LAYER M3 ;
      RECT 67.743 0.000 67.761 0.054 ;
    END
  END rw0_rd_out[12]
  PIN rw0_rd_out[13]
    DIRECTION OUTPUT ;
    USE SIGNAL ;
    SHAPE ABUTMENT ;
    PORT
      LAYER M3 ;
      RECT 67.995 0.000 68.013 0.054 ;
    END
  END rw0_rd_out[13]
  PIN rw0_rd_out[14]
    DIRECTION OUTPUT ;
    USE SIGNAL ;
    SHAPE ABUTMENT ;
    PORT
      LAYER M3 ;
      RECT 68.247 0.000 68.265 0.054 ;
    END
  END rw0_rd_out[14]
  PIN rw0_rd_out[15]
    DIRECTION OUTPUT ;
    USE SIGNAL ;
    SHAPE ABUTMENT ;
    PORT
      LAYER M3 ;
      RECT 68.499 0.000 68.517 0.054 ;
    END
  END rw0_rd_out[15]
  PIN rw0_rd_out[16]
    DIRECTION OUTPUT ;
    USE SIGNAL ;
    SHAPE ABUTMENT ;
    PORT
      LAYER M3 ;
      RECT 68.751 0.000 68.769 0.054 ;
    END
  END rw0_rd_out[16]
  PIN rw0_rd_out[17]
    DIRECTION OUTPUT ;
    USE SIGNAL ;
    SHAPE ABUTMENT ;
    PORT
      LAYER M3 ;
      RECT 69.003 0.000 69.021 0.054 ;
    END
  END rw0_rd_out[17]
  PIN rw0_rd_out[18]
    DIRECTION OUTPUT ;
    USE SIGNAL ;
    SHAPE ABUTMENT ;
    PORT
      LAYER M3 ;
      RECT 69.255 0.000 69.273 0.054 ;
    END
  END rw0_rd_out[18]
  PIN rw0_rd_out[19]
    DIRECTION OUTPUT ;
    USE SIGNAL ;
    SHAPE ABUTMENT ;
    PORT
      LAYER M3 ;
      RECT 69.507 0.000 69.525 0.054 ;
    END
  END rw0_rd_out[19]
  PIN rw0_rd_out[20]
    DIRECTION OUTPUT ;
    USE SIGNAL ;
    SHAPE ABUTMENT ;
    PORT
      LAYER M3 ;
      RECT 69.759 0.000 69.777 0.054 ;
    END
  END rw0_rd_out[20]
  PIN rw0_rd_out[21]
    DIRECTION OUTPUT ;
    USE SIGNAL ;
    SHAPE ABUTMENT ;
    PORT
      LAYER M3 ;
      RECT 70.011 0.000 70.029 0.054 ;
    END
  END rw0_rd_out[21]
  PIN rw0_rd_out[22]
    DIRECTION OUTPUT ;
    USE SIGNAL ;
    SHAPE ABUTMENT ;
    PORT
      LAYER M3 ;
      RECT 70.263 0.000 70.281 0.054 ;
    END
  END rw0_rd_out[22]
  PIN rw0_rd_out[23]
    DIRECTION OUTPUT ;
    USE SIGNAL ;
    SHAPE ABUTMENT ;
    PORT
      LAYER M3 ;
      RECT 70.515 0.000 70.533 0.054 ;
    END
  END rw0_rd_out[23]
  PIN rw0_rd_out[24]
    DIRECTION OUTPUT ;
    USE SIGNAL ;
    SHAPE ABUTMENT ;
    PORT
      LAYER M3 ;
      RECT 70.767 0.000 70.785 0.054 ;
    END
  END rw0_rd_out[24]
  PIN rw0_rd_out[25]
    DIRECTION OUTPUT ;
    USE SIGNAL ;
    SHAPE ABUTMENT ;
    PORT
      LAYER M3 ;
      RECT 71.019 0.000 71.037 0.054 ;
    END
  END rw0_rd_out[25]
  PIN rw0_rd_out[26]
    DIRECTION OUTPUT ;
    USE SIGNAL ;
    SHAPE ABUTMENT ;
    PORT
      LAYER M3 ;
      RECT 71.271 0.000 71.289 0.054 ;
    END
  END rw0_rd_out[26]
  PIN rw0_rd_out[27]
    DIRECTION OUTPUT ;
    USE SIGNAL ;
    SHAPE ABUTMENT ;
    PORT
      LAYER M3 ;
      RECT 71.523 0.000 71.541 0.054 ;
    END
  END rw0_rd_out[27]
  PIN rw0_rd_out[28]
    DIRECTION OUTPUT ;
    USE SIGNAL ;
    SHAPE ABUTMENT ;
    PORT
      LAYER M3 ;
      RECT 71.775 0.000 71.793 0.054 ;
    END
  END rw0_rd_out[28]
  PIN rw0_rd_out[29]
    DIRECTION OUTPUT ;
    USE SIGNAL ;
    SHAPE ABUTMENT ;
    PORT
      LAYER M3 ;
      RECT 72.027 0.000 72.045 0.054 ;
    END
  END rw0_rd_out[29]
  PIN rw0_rd_out[30]
    DIRECTION OUTPUT ;
    USE SIGNAL ;
    SHAPE ABUTMENT ;
    PORT
      LAYER M3 ;
      RECT 72.279 0.000 72.297 0.054 ;
    END
  END rw0_rd_out[30]
  PIN rw0_rd_out[31]
    DIRECTION OUTPUT ;
    USE SIGNAL ;
    SHAPE ABUTMENT ;
    PORT
      LAYER M3 ;
      RECT 72.531 0.000 72.549 0.054 ;
    END
  END rw0_rd_out[31]
  PIN rw0_rd_out[32]
    DIRECTION OUTPUT ;
    USE SIGNAL ;
    SHAPE ABUTMENT ;
    PORT
      LAYER M3 ;
      RECT 72.783 0.000 72.801 0.054 ;
    END
  END rw0_rd_out[32]
  PIN rw0_rd_out[33]
    DIRECTION OUTPUT ;
    USE SIGNAL ;
    SHAPE ABUTMENT ;
    PORT
      LAYER M3 ;
      RECT 73.035 0.000 73.053 0.054 ;
    END
  END rw0_rd_out[33]
  PIN rw0_rd_out[34]
    DIRECTION OUTPUT ;
    USE SIGNAL ;
    SHAPE ABUTMENT ;
    PORT
      LAYER M3 ;
      RECT 73.287 0.000 73.305 0.054 ;
    END
  END rw0_rd_out[34]
  PIN rw0_rd_out[35]
    DIRECTION OUTPUT ;
    USE SIGNAL ;
    SHAPE ABUTMENT ;
    PORT
      LAYER M3 ;
      RECT 73.539 0.000 73.557 0.054 ;
    END
  END rw0_rd_out[35]
  PIN rw0_rd_out[36]
    DIRECTION OUTPUT ;
    USE SIGNAL ;
    SHAPE ABUTMENT ;
    PORT
      LAYER M3 ;
      RECT 73.791 0.000 73.809 0.054 ;
    END
  END rw0_rd_out[36]
  PIN rw0_rd_out[37]
    DIRECTION OUTPUT ;
    USE SIGNAL ;
    SHAPE ABUTMENT ;
    PORT
      LAYER M3 ;
      RECT 74.043 0.000 74.061 0.054 ;
    END
  END rw0_rd_out[37]
  PIN rw0_rd_out[38]
    DIRECTION OUTPUT ;
    USE SIGNAL ;
    SHAPE ABUTMENT ;
    PORT
      LAYER M3 ;
      RECT 74.295 0.000 74.313 0.054 ;
    END
  END rw0_rd_out[38]
  PIN rw0_rd_out[39]
    DIRECTION OUTPUT ;
    USE SIGNAL ;
    SHAPE ABUTMENT ;
    PORT
      LAYER M3 ;
      RECT 74.547 0.000 74.565 0.054 ;
    END
  END rw0_rd_out[39]
  PIN rw0_rd_out[40]
    DIRECTION OUTPUT ;
    USE SIGNAL ;
    SHAPE ABUTMENT ;
    PORT
      LAYER M3 ;
      RECT 74.799 0.000 74.817 0.054 ;
    END
  END rw0_rd_out[40]
  PIN rw0_rd_out[41]
    DIRECTION OUTPUT ;
    USE SIGNAL ;
    SHAPE ABUTMENT ;
    PORT
      LAYER M3 ;
      RECT 75.051 0.000 75.069 0.054 ;
    END
  END rw0_rd_out[41]
  PIN rw0_rd_out[42]
    DIRECTION OUTPUT ;
    USE SIGNAL ;
    SHAPE ABUTMENT ;
    PORT
      LAYER M3 ;
      RECT 75.303 0.000 75.321 0.054 ;
    END
  END rw0_rd_out[42]
  PIN rw0_rd_out[43]
    DIRECTION OUTPUT ;
    USE SIGNAL ;
    SHAPE ABUTMENT ;
    PORT
      LAYER M3 ;
      RECT 75.555 0.000 75.573 0.054 ;
    END
  END rw0_rd_out[43]
  PIN rw0_rd_out[44]
    DIRECTION OUTPUT ;
    USE SIGNAL ;
    SHAPE ABUTMENT ;
    PORT
      LAYER M3 ;
      RECT 75.807 0.000 75.825 0.054 ;
    END
  END rw0_rd_out[44]
  PIN rw0_rd_out[45]
    DIRECTION OUTPUT ;
    USE SIGNAL ;
    SHAPE ABUTMENT ;
    PORT
      LAYER M3 ;
      RECT 76.059 0.000 76.077 0.054 ;
    END
  END rw0_rd_out[45]
  PIN rw0_rd_out[46]
    DIRECTION OUTPUT ;
    USE SIGNAL ;
    SHAPE ABUTMENT ;
    PORT
      LAYER M3 ;
      RECT 76.311 0.000 76.329 0.054 ;
    END
  END rw0_rd_out[46]
  PIN rw0_rd_out[47]
    DIRECTION OUTPUT ;
    USE SIGNAL ;
    SHAPE ABUTMENT ;
    PORT
      LAYER M3 ;
      RECT 76.563 0.000 76.581 0.054 ;
    END
  END rw0_rd_out[47]
  PIN rw0_rd_out[48]
    DIRECTION OUTPUT ;
    USE SIGNAL ;
    SHAPE ABUTMENT ;
    PORT
      LAYER M3 ;
      RECT 76.815 0.000 76.833 0.054 ;
    END
  END rw0_rd_out[48]
  PIN rw0_rd_out[49]
    DIRECTION OUTPUT ;
    USE SIGNAL ;
    SHAPE ABUTMENT ;
    PORT
      LAYER M3 ;
      RECT 77.067 0.000 77.085 0.054 ;
    END
  END rw0_rd_out[49]
  PIN rw0_rd_out[50]
    DIRECTION OUTPUT ;
    USE SIGNAL ;
    SHAPE ABUTMENT ;
    PORT
      LAYER M3 ;
      RECT 77.319 0.000 77.337 0.054 ;
    END
  END rw0_rd_out[50]
  PIN rw0_rd_out[51]
    DIRECTION OUTPUT ;
    USE SIGNAL ;
    SHAPE ABUTMENT ;
    PORT
      LAYER M3 ;
      RECT 77.571 0.000 77.589 0.054 ;
    END
  END rw0_rd_out[51]
  PIN rw0_rd_out[52]
    DIRECTION OUTPUT ;
    USE SIGNAL ;
    SHAPE ABUTMENT ;
    PORT
      LAYER M3 ;
      RECT 77.823 0.000 77.841 0.054 ;
    END
  END rw0_rd_out[52]
  PIN rw0_rd_out[53]
    DIRECTION OUTPUT ;
    USE SIGNAL ;
    SHAPE ABUTMENT ;
    PORT
      LAYER M3 ;
      RECT 78.075 0.000 78.093 0.054 ;
    END
  END rw0_rd_out[53]
  PIN rw0_rd_out[54]
    DIRECTION OUTPUT ;
    USE SIGNAL ;
    SHAPE ABUTMENT ;
    PORT
      LAYER M3 ;
      RECT 78.327 0.000 78.345 0.054 ;
    END
  END rw0_rd_out[54]
  PIN rw0_rd_out[55]
    DIRECTION OUTPUT ;
    USE SIGNAL ;
    SHAPE ABUTMENT ;
    PORT
      LAYER M3 ;
      RECT 78.579 0.000 78.597 0.054 ;
    END
  END rw0_rd_out[55]
  PIN rw0_rd_out[56]
    DIRECTION OUTPUT ;
    USE SIGNAL ;
    SHAPE ABUTMENT ;
    PORT
      LAYER M3 ;
      RECT 78.831 0.000 78.849 0.054 ;
    END
  END rw0_rd_out[56]
  PIN rw0_rd_out[57]
    DIRECTION OUTPUT ;
    USE SIGNAL ;
    SHAPE ABUTMENT ;
    PORT
      LAYER M3 ;
      RECT 79.083 0.000 79.101 0.054 ;
    END
  END rw0_rd_out[57]
  PIN rw0_rd_out[58]
    DIRECTION OUTPUT ;
    USE SIGNAL ;
    SHAPE ABUTMENT ;
    PORT
      LAYER M3 ;
      RECT 79.335 0.000 79.353 0.054 ;
    END
  END rw0_rd_out[58]
  PIN rw0_rd_out[59]
    DIRECTION OUTPUT ;
    USE SIGNAL ;
    SHAPE ABUTMENT ;
    PORT
      LAYER M3 ;
      RECT 79.587 0.000 79.605 0.054 ;
    END
  END rw0_rd_out[59]
  PIN rw0_rd_out[60]
    DIRECTION OUTPUT ;
    USE SIGNAL ;
    SHAPE ABUTMENT ;
    PORT
      LAYER M3 ;
      RECT 79.839 0.000 79.857 0.054 ;
    END
  END rw0_rd_out[60]
  PIN rw0_rd_out[61]
    DIRECTION OUTPUT ;
    USE SIGNAL ;
    SHAPE ABUTMENT ;
    PORT
      LAYER M3 ;
      RECT 80.091 0.000 80.109 0.054 ;
    END
  END rw0_rd_out[61]
  PIN rw0_rd_out[62]
    DIRECTION OUTPUT ;
    USE SIGNAL ;
    SHAPE ABUTMENT ;
    PORT
      LAYER M3 ;
      RECT 80.343 0.000 80.361 0.054 ;
    END
  END rw0_rd_out[62]
  PIN rw0_rd_out[63]
    DIRECTION OUTPUT ;
    USE SIGNAL ;
    SHAPE ABUTMENT ;
    PORT
      LAYER M3 ;
      RECT 80.595 0.000 80.613 0.054 ;
    END
  END rw0_rd_out[63]
  PIN rw0_rd_out[64]
    DIRECTION OUTPUT ;
    USE SIGNAL ;
    SHAPE ABUTMENT ;
    PORT
      LAYER M3 ;
      RECT 80.847 0.000 80.865 0.054 ;
    END
  END rw0_rd_out[64]
  PIN rw0_rd_out[65]
    DIRECTION OUTPUT ;
    USE SIGNAL ;
    SHAPE ABUTMENT ;
    PORT
      LAYER M3 ;
      RECT 81.099 0.000 81.117 0.054 ;
    END
  END rw0_rd_out[65]
  PIN rw0_rd_out[66]
    DIRECTION OUTPUT ;
    USE SIGNAL ;
    SHAPE ABUTMENT ;
    PORT
      LAYER M3 ;
      RECT 81.351 0.000 81.369 0.054 ;
    END
  END rw0_rd_out[66]
  PIN rw0_rd_out[67]
    DIRECTION OUTPUT ;
    USE SIGNAL ;
    SHAPE ABUTMENT ;
    PORT
      LAYER M3 ;
      RECT 81.603 0.000 81.621 0.054 ;
    END
  END rw0_rd_out[67]
  PIN rw0_rd_out[68]
    DIRECTION OUTPUT ;
    USE SIGNAL ;
    SHAPE ABUTMENT ;
    PORT
      LAYER M3 ;
      RECT 81.855 0.000 81.873 0.054 ;
    END
  END rw0_rd_out[68]
  PIN rw0_rd_out[69]
    DIRECTION OUTPUT ;
    USE SIGNAL ;
    SHAPE ABUTMENT ;
    PORT
      LAYER M3 ;
      RECT 82.107 0.000 82.125 0.054 ;
    END
  END rw0_rd_out[69]
  PIN rw0_rd_out[70]
    DIRECTION OUTPUT ;
    USE SIGNAL ;
    SHAPE ABUTMENT ;
    PORT
      LAYER M3 ;
      RECT 82.359 0.000 82.377 0.054 ;
    END
  END rw0_rd_out[70]
  PIN rw0_rd_out[71]
    DIRECTION OUTPUT ;
    USE SIGNAL ;
    SHAPE ABUTMENT ;
    PORT
      LAYER M3 ;
      RECT 82.611 0.000 82.629 0.054 ;
    END
  END rw0_rd_out[71]
  PIN rw0_rd_out[72]
    DIRECTION OUTPUT ;
    USE SIGNAL ;
    SHAPE ABUTMENT ;
    PORT
      LAYER M3 ;
      RECT 82.863 0.000 82.881 0.054 ;
    END
  END rw0_rd_out[72]
  PIN rw0_rd_out[73]
    DIRECTION OUTPUT ;
    USE SIGNAL ;
    SHAPE ABUTMENT ;
    PORT
      LAYER M3 ;
      RECT 83.115 0.000 83.133 0.054 ;
    END
  END rw0_rd_out[73]
  PIN rw0_rd_out[74]
    DIRECTION OUTPUT ;
    USE SIGNAL ;
    SHAPE ABUTMENT ;
    PORT
      LAYER M3 ;
      RECT 83.367 0.000 83.385 0.054 ;
    END
  END rw0_rd_out[74]
  PIN rw0_rd_out[75]
    DIRECTION OUTPUT ;
    USE SIGNAL ;
    SHAPE ABUTMENT ;
    PORT
      LAYER M3 ;
      RECT 83.619 0.000 83.637 0.054 ;
    END
  END rw0_rd_out[75]
  PIN rw0_rd_out[76]
    DIRECTION OUTPUT ;
    USE SIGNAL ;
    SHAPE ABUTMENT ;
    PORT
      LAYER M3 ;
      RECT 83.871 0.000 83.889 0.054 ;
    END
  END rw0_rd_out[76]
  PIN rw0_rd_out[77]
    DIRECTION OUTPUT ;
    USE SIGNAL ;
    SHAPE ABUTMENT ;
    PORT
      LAYER M3 ;
      RECT 84.123 0.000 84.141 0.054 ;
    END
  END rw0_rd_out[77]
  PIN rw0_rd_out[78]
    DIRECTION OUTPUT ;
    USE SIGNAL ;
    SHAPE ABUTMENT ;
    PORT
      LAYER M3 ;
      RECT 84.375 0.000 84.393 0.054 ;
    END
  END rw0_rd_out[78]
  PIN rw0_rd_out[79]
    DIRECTION OUTPUT ;
    USE SIGNAL ;
    SHAPE ABUTMENT ;
    PORT
      LAYER M3 ;
      RECT 84.627 0.000 84.645 0.054 ;
    END
  END rw0_rd_out[79]
  PIN rw0_rd_out[80]
    DIRECTION OUTPUT ;
    USE SIGNAL ;
    SHAPE ABUTMENT ;
    PORT
      LAYER M3 ;
      RECT 84.879 0.000 84.897 0.054 ;
    END
  END rw0_rd_out[80]
  PIN rw0_rd_out[81]
    DIRECTION OUTPUT ;
    USE SIGNAL ;
    SHAPE ABUTMENT ;
    PORT
      LAYER M3 ;
      RECT 85.131 0.000 85.149 0.054 ;
    END
  END rw0_rd_out[81]
  PIN rw0_rd_out[82]
    DIRECTION OUTPUT ;
    USE SIGNAL ;
    SHAPE ABUTMENT ;
    PORT
      LAYER M3 ;
      RECT 85.383 0.000 85.401 0.054 ;
    END
  END rw0_rd_out[82]
  PIN rw0_rd_out[83]
    DIRECTION OUTPUT ;
    USE SIGNAL ;
    SHAPE ABUTMENT ;
    PORT
      LAYER M3 ;
      RECT 85.635 0.000 85.653 0.054 ;
    END
  END rw0_rd_out[83]
  PIN rw0_rd_out[84]
    DIRECTION OUTPUT ;
    USE SIGNAL ;
    SHAPE ABUTMENT ;
    PORT
      LAYER M3 ;
      RECT 85.887 0.000 85.905 0.054 ;
    END
  END rw0_rd_out[84]
  PIN rw0_rd_out[85]
    DIRECTION OUTPUT ;
    USE SIGNAL ;
    SHAPE ABUTMENT ;
    PORT
      LAYER M3 ;
      RECT 86.139 0.000 86.157 0.054 ;
    END
  END rw0_rd_out[85]
  PIN rw0_rd_out[86]
    DIRECTION OUTPUT ;
    USE SIGNAL ;
    SHAPE ABUTMENT ;
    PORT
      LAYER M3 ;
      RECT 86.391 0.000 86.409 0.054 ;
    END
  END rw0_rd_out[86]
  PIN rw0_rd_out[87]
    DIRECTION OUTPUT ;
    USE SIGNAL ;
    SHAPE ABUTMENT ;
    PORT
      LAYER M3 ;
      RECT 86.643 0.000 86.661 0.054 ;
    END
  END rw0_rd_out[87]
  PIN rw0_rd_out[88]
    DIRECTION OUTPUT ;
    USE SIGNAL ;
    SHAPE ABUTMENT ;
    PORT
      LAYER M3 ;
      RECT 86.895 0.000 86.913 0.054 ;
    END
  END rw0_rd_out[88]
  PIN rw0_rd_out[89]
    DIRECTION OUTPUT ;
    USE SIGNAL ;
    SHAPE ABUTMENT ;
    PORT
      LAYER M3 ;
      RECT 87.147 0.000 87.165 0.054 ;
    END
  END rw0_rd_out[89]
  PIN rw0_rd_out[90]
    DIRECTION OUTPUT ;
    USE SIGNAL ;
    SHAPE ABUTMENT ;
    PORT
      LAYER M3 ;
      RECT 87.399 0.000 87.417 0.054 ;
    END
  END rw0_rd_out[90]
  PIN rw0_rd_out[91]
    DIRECTION OUTPUT ;
    USE SIGNAL ;
    SHAPE ABUTMENT ;
    PORT
      LAYER M3 ;
      RECT 87.651 0.000 87.669 0.054 ;
    END
  END rw0_rd_out[91]
  PIN rw0_rd_out[92]
    DIRECTION OUTPUT ;
    USE SIGNAL ;
    SHAPE ABUTMENT ;
    PORT
      LAYER M3 ;
      RECT 87.903 0.000 87.921 0.054 ;
    END
  END rw0_rd_out[92]
  PIN rw0_rd_out[93]
    DIRECTION OUTPUT ;
    USE SIGNAL ;
    SHAPE ABUTMENT ;
    PORT
      LAYER M3 ;
      RECT 88.155 0.000 88.173 0.054 ;
    END
  END rw0_rd_out[93]
  PIN rw0_rd_out[94]
    DIRECTION OUTPUT ;
    USE SIGNAL ;
    SHAPE ABUTMENT ;
    PORT
      LAYER M3 ;
      RECT 88.407 0.000 88.425 0.054 ;
    END
  END rw0_rd_out[94]
  PIN rw0_rd_out[95]
    DIRECTION OUTPUT ;
    USE SIGNAL ;
    SHAPE ABUTMENT ;
    PORT
      LAYER M3 ;
      RECT 88.659 0.000 88.677 0.054 ;
    END
  END rw0_rd_out[95]
  PIN rw0_rd_out[96]
    DIRECTION OUTPUT ;
    USE SIGNAL ;
    SHAPE ABUTMENT ;
    PORT
      LAYER M3 ;
      RECT 88.911 0.000 88.929 0.054 ;
    END
  END rw0_rd_out[96]
  PIN rw0_rd_out[97]
    DIRECTION OUTPUT ;
    USE SIGNAL ;
    SHAPE ABUTMENT ;
    PORT
      LAYER M3 ;
      RECT 89.163 0.000 89.181 0.054 ;
    END
  END rw0_rd_out[97]
  PIN rw0_rd_out[98]
    DIRECTION OUTPUT ;
    USE SIGNAL ;
    SHAPE ABUTMENT ;
    PORT
      LAYER M3 ;
      RECT 89.415 0.000 89.433 0.054 ;
    END
  END rw0_rd_out[98]
  PIN rw0_rd_out[99]
    DIRECTION OUTPUT ;
    USE SIGNAL ;
    SHAPE ABUTMENT ;
    PORT
      LAYER M3 ;
      RECT 89.667 0.000 89.685 0.054 ;
    END
  END rw0_rd_out[99]
  PIN rw0_rd_out[100]
    DIRECTION OUTPUT ;
    USE SIGNAL ;
    SHAPE ABUTMENT ;
    PORT
      LAYER M3 ;
      RECT 89.919 0.000 89.937 0.054 ;
    END
  END rw0_rd_out[100]
  PIN rw0_rd_out[101]
    DIRECTION OUTPUT ;
    USE SIGNAL ;
    SHAPE ABUTMENT ;
    PORT
      LAYER M3 ;
      RECT 90.171 0.000 90.189 0.054 ;
    END
  END rw0_rd_out[101]
  PIN rw0_rd_out[102]
    DIRECTION OUTPUT ;
    USE SIGNAL ;
    SHAPE ABUTMENT ;
    PORT
      LAYER M3 ;
      RECT 90.423 0.000 90.441 0.054 ;
    END
  END rw0_rd_out[102]
  PIN rw0_rd_out[103]
    DIRECTION OUTPUT ;
    USE SIGNAL ;
    SHAPE ABUTMENT ;
    PORT
      LAYER M3 ;
      RECT 90.675 0.000 90.693 0.054 ;
    END
  END rw0_rd_out[103]
  PIN rw0_rd_out[104]
    DIRECTION OUTPUT ;
    USE SIGNAL ;
    SHAPE ABUTMENT ;
    PORT
      LAYER M3 ;
      RECT 90.927 0.000 90.945 0.054 ;
    END
  END rw0_rd_out[104]
  PIN rw0_rd_out[105]
    DIRECTION OUTPUT ;
    USE SIGNAL ;
    SHAPE ABUTMENT ;
    PORT
      LAYER M3 ;
      RECT 91.179 0.000 91.197 0.054 ;
    END
  END rw0_rd_out[105]
  PIN rw0_rd_out[106]
    DIRECTION OUTPUT ;
    USE SIGNAL ;
    SHAPE ABUTMENT ;
    PORT
      LAYER M3 ;
      RECT 91.431 0.000 91.449 0.054 ;
    END
  END rw0_rd_out[106]
  PIN rw0_rd_out[107]
    DIRECTION OUTPUT ;
    USE SIGNAL ;
    SHAPE ABUTMENT ;
    PORT
      LAYER M3 ;
      RECT 91.683 0.000 91.701 0.054 ;
    END
  END rw0_rd_out[107]
  PIN rw0_rd_out[108]
    DIRECTION OUTPUT ;
    USE SIGNAL ;
    SHAPE ABUTMENT ;
    PORT
      LAYER M3 ;
      RECT 91.935 0.000 91.953 0.054 ;
    END
  END rw0_rd_out[108]
  PIN rw0_rd_out[109]
    DIRECTION OUTPUT ;
    USE SIGNAL ;
    SHAPE ABUTMENT ;
    PORT
      LAYER M3 ;
      RECT 92.187 0.000 92.205 0.054 ;
    END
  END rw0_rd_out[109]
  PIN rw0_rd_out[110]
    DIRECTION OUTPUT ;
    USE SIGNAL ;
    SHAPE ABUTMENT ;
    PORT
      LAYER M3 ;
      RECT 92.439 0.000 92.457 0.054 ;
    END
  END rw0_rd_out[110]
  PIN rw0_rd_out[111]
    DIRECTION OUTPUT ;
    USE SIGNAL ;
    SHAPE ABUTMENT ;
    PORT
      LAYER M3 ;
      RECT 92.691 0.000 92.709 0.054 ;
    END
  END rw0_rd_out[111]
  PIN rw0_rd_out[112]
    DIRECTION OUTPUT ;
    USE SIGNAL ;
    SHAPE ABUTMENT ;
    PORT
      LAYER M3 ;
      RECT 92.943 0.000 92.961 0.054 ;
    END
  END rw0_rd_out[112]
  PIN rw0_rd_out[113]
    DIRECTION OUTPUT ;
    USE SIGNAL ;
    SHAPE ABUTMENT ;
    PORT
      LAYER M3 ;
      RECT 93.195 0.000 93.213 0.054 ;
    END
  END rw0_rd_out[113]
  PIN rw0_rd_out[114]
    DIRECTION OUTPUT ;
    USE SIGNAL ;
    SHAPE ABUTMENT ;
    PORT
      LAYER M3 ;
      RECT 93.447 0.000 93.465 0.054 ;
    END
  END rw0_rd_out[114]
  PIN rw0_rd_out[115]
    DIRECTION OUTPUT ;
    USE SIGNAL ;
    SHAPE ABUTMENT ;
    PORT
      LAYER M3 ;
      RECT 93.699 0.000 93.717 0.054 ;
    END
  END rw0_rd_out[115]
  PIN rw0_rd_out[116]
    DIRECTION OUTPUT ;
    USE SIGNAL ;
    SHAPE ABUTMENT ;
    PORT
      LAYER M3 ;
      RECT 93.951 0.000 93.969 0.054 ;
    END
  END rw0_rd_out[116]
  PIN rw0_rd_out[117]
    DIRECTION OUTPUT ;
    USE SIGNAL ;
    SHAPE ABUTMENT ;
    PORT
      LAYER M3 ;
      RECT 94.203 0.000 94.221 0.054 ;
    END
  END rw0_rd_out[117]
  PIN rw0_rd_out[118]
    DIRECTION OUTPUT ;
    USE SIGNAL ;
    SHAPE ABUTMENT ;
    PORT
      LAYER M3 ;
      RECT 94.455 0.000 94.473 0.054 ;
    END
  END rw0_rd_out[118]
  PIN rw0_rd_out[119]
    DIRECTION OUTPUT ;
    USE SIGNAL ;
    SHAPE ABUTMENT ;
    PORT
      LAYER M3 ;
      RECT 94.707 0.000 94.725 0.054 ;
    END
  END rw0_rd_out[119]
  PIN rw0_rd_out[120]
    DIRECTION OUTPUT ;
    USE SIGNAL ;
    SHAPE ABUTMENT ;
    PORT
      LAYER M3 ;
      RECT 94.959 0.000 94.977 0.054 ;
    END
  END rw0_rd_out[120]
  PIN rw0_rd_out[121]
    DIRECTION OUTPUT ;
    USE SIGNAL ;
    SHAPE ABUTMENT ;
    PORT
      LAYER M3 ;
      RECT 95.211 0.000 95.229 0.054 ;
    END
  END rw0_rd_out[121]
  PIN rw0_rd_out[122]
    DIRECTION OUTPUT ;
    USE SIGNAL ;
    SHAPE ABUTMENT ;
    PORT
      LAYER M3 ;
      RECT 95.463 0.000 95.481 0.054 ;
    END
  END rw0_rd_out[122]
  PIN rw0_rd_out[123]
    DIRECTION OUTPUT ;
    USE SIGNAL ;
    SHAPE ABUTMENT ;
    PORT
      LAYER M3 ;
      RECT 95.715 0.000 95.733 0.054 ;
    END
  END rw0_rd_out[123]
  PIN rw0_rd_out[124]
    DIRECTION OUTPUT ;
    USE SIGNAL ;
    SHAPE ABUTMENT ;
    PORT
      LAYER M3 ;
      RECT 95.967 0.000 95.985 0.054 ;
    END
  END rw0_rd_out[124]
  PIN rw0_rd_out[125]
    DIRECTION OUTPUT ;
    USE SIGNAL ;
    SHAPE ABUTMENT ;
    PORT
      LAYER M3 ;
      RECT 96.219 0.000 96.237 0.054 ;
    END
  END rw0_rd_out[125]
  PIN rw0_rd_out[126]
    DIRECTION OUTPUT ;
    USE SIGNAL ;
    SHAPE ABUTMENT ;
    PORT
      LAYER M3 ;
      RECT 96.471 0.000 96.489 0.054 ;
    END
  END rw0_rd_out[126]
  PIN rw0_rd_out[127]
    DIRECTION OUTPUT ;
    USE SIGNAL ;
    SHAPE ABUTMENT ;
    PORT
      LAYER M3 ;
      RECT 96.723 0.000 96.741 0.054 ;
    END
  END rw0_rd_out[127]
  PIN rw0_rd_out[128]
    DIRECTION OUTPUT ;
    USE SIGNAL ;
    SHAPE ABUTMENT ;
    PORT
      LAYER M3 ;
      RECT 96.975 0.000 96.993 0.054 ;
    END
  END rw0_rd_out[128]
  PIN rw0_rd_out[129]
    DIRECTION OUTPUT ;
    USE SIGNAL ;
    SHAPE ABUTMENT ;
    PORT
      LAYER M3 ;
      RECT 97.227 0.000 97.245 0.054 ;
    END
  END rw0_rd_out[129]
  PIN rw0_rd_out[130]
    DIRECTION OUTPUT ;
    USE SIGNAL ;
    SHAPE ABUTMENT ;
    PORT
      LAYER M3 ;
      RECT 97.479 0.000 97.497 0.054 ;
    END
  END rw0_rd_out[130]
  PIN rw0_rd_out[131]
    DIRECTION OUTPUT ;
    USE SIGNAL ;
    SHAPE ABUTMENT ;
    PORT
      LAYER M3 ;
      RECT 97.731 0.000 97.749 0.054 ;
    END
  END rw0_rd_out[131]
  PIN rw0_rd_out[132]
    DIRECTION OUTPUT ;
    USE SIGNAL ;
    SHAPE ABUTMENT ;
    PORT
      LAYER M3 ;
      RECT 97.983 0.000 98.001 0.054 ;
    END
  END rw0_rd_out[132]
  PIN rw0_rd_out[133]
    DIRECTION OUTPUT ;
    USE SIGNAL ;
    SHAPE ABUTMENT ;
    PORT
      LAYER M3 ;
      RECT 98.235 0.000 98.253 0.054 ;
    END
  END rw0_rd_out[133]
  PIN rw0_rd_out[134]
    DIRECTION OUTPUT ;
    USE SIGNAL ;
    SHAPE ABUTMENT ;
    PORT
      LAYER M3 ;
      RECT 98.487 0.000 98.505 0.054 ;
    END
  END rw0_rd_out[134]
  PIN rw0_rd_out[135]
    DIRECTION OUTPUT ;
    USE SIGNAL ;
    SHAPE ABUTMENT ;
    PORT
      LAYER M3 ;
      RECT 98.739 0.000 98.757 0.054 ;
    END
  END rw0_rd_out[135]
  PIN rw0_rd_out[136]
    DIRECTION OUTPUT ;
    USE SIGNAL ;
    SHAPE ABUTMENT ;
    PORT
      LAYER M3 ;
      RECT 98.991 0.000 99.009 0.054 ;
    END
  END rw0_rd_out[136]
  PIN rw0_rd_out[137]
    DIRECTION OUTPUT ;
    USE SIGNAL ;
    SHAPE ABUTMENT ;
    PORT
      LAYER M3 ;
      RECT 99.243 0.000 99.261 0.054 ;
    END
  END rw0_rd_out[137]
  PIN rw0_rd_out[138]
    DIRECTION OUTPUT ;
    USE SIGNAL ;
    SHAPE ABUTMENT ;
    PORT
      LAYER M3 ;
      RECT 99.495 0.000 99.513 0.054 ;
    END
  END rw0_rd_out[138]
  PIN rw0_rd_out[139]
    DIRECTION OUTPUT ;
    USE SIGNAL ;
    SHAPE ABUTMENT ;
    PORT
      LAYER M3 ;
      RECT 99.747 0.000 99.765 0.054 ;
    END
  END rw0_rd_out[139]
  PIN rw0_rd_out[140]
    DIRECTION OUTPUT ;
    USE SIGNAL ;
    SHAPE ABUTMENT ;
    PORT
      LAYER M3 ;
      RECT 99.999 0.000 100.017 0.054 ;
    END
  END rw0_rd_out[140]
  PIN rw0_rd_out[141]
    DIRECTION OUTPUT ;
    USE SIGNAL ;
    SHAPE ABUTMENT ;
    PORT
      LAYER M3 ;
      RECT 100.251 0.000 100.269 0.054 ;
    END
  END rw0_rd_out[141]
  PIN rw0_rd_out[142]
    DIRECTION OUTPUT ;
    USE SIGNAL ;
    SHAPE ABUTMENT ;
    PORT
      LAYER M3 ;
      RECT 100.503 0.000 100.521 0.054 ;
    END
  END rw0_rd_out[142]
  PIN rw0_rd_out[143]
    DIRECTION OUTPUT ;
    USE SIGNAL ;
    SHAPE ABUTMENT ;
    PORT
      LAYER M3 ;
      RECT 100.755 0.000 100.773 0.054 ;
    END
  END rw0_rd_out[143]
  PIN rw0_rd_out[144]
    DIRECTION OUTPUT ;
    USE SIGNAL ;
    SHAPE ABUTMENT ;
    PORT
      LAYER M3 ;
      RECT 101.007 0.000 101.025 0.054 ;
    END
  END rw0_rd_out[144]
  PIN rw0_rd_out[145]
    DIRECTION OUTPUT ;
    USE SIGNAL ;
    SHAPE ABUTMENT ;
    PORT
      LAYER M3 ;
      RECT 101.259 0.000 101.277 0.054 ;
    END
  END rw0_rd_out[145]
  PIN rw0_rd_out[146]
    DIRECTION OUTPUT ;
    USE SIGNAL ;
    SHAPE ABUTMENT ;
    PORT
      LAYER M3 ;
      RECT 101.511 0.000 101.529 0.054 ;
    END
  END rw0_rd_out[146]
  PIN rw0_rd_out[147]
    DIRECTION OUTPUT ;
    USE SIGNAL ;
    SHAPE ABUTMENT ;
    PORT
      LAYER M3 ;
      RECT 101.763 0.000 101.781 0.054 ;
    END
  END rw0_rd_out[147]
  PIN rw0_rd_out[148]
    DIRECTION OUTPUT ;
    USE SIGNAL ;
    SHAPE ABUTMENT ;
    PORT
      LAYER M3 ;
      RECT 102.015 0.000 102.033 0.054 ;
    END
  END rw0_rd_out[148]
  PIN rw0_rd_out[149]
    DIRECTION OUTPUT ;
    USE SIGNAL ;
    SHAPE ABUTMENT ;
    PORT
      LAYER M3 ;
      RECT 102.267 0.000 102.285 0.054 ;
    END
  END rw0_rd_out[149]
  PIN rw0_rd_out[150]
    DIRECTION OUTPUT ;
    USE SIGNAL ;
    SHAPE ABUTMENT ;
    PORT
      LAYER M3 ;
      RECT 102.519 0.000 102.537 0.054 ;
    END
  END rw0_rd_out[150]
  PIN rw0_rd_out[151]
    DIRECTION OUTPUT ;
    USE SIGNAL ;
    SHAPE ABUTMENT ;
    PORT
      LAYER M3 ;
      RECT 102.771 0.000 102.789 0.054 ;
    END
  END rw0_rd_out[151]
  PIN rw0_rd_out[152]
    DIRECTION OUTPUT ;
    USE SIGNAL ;
    SHAPE ABUTMENT ;
    PORT
      LAYER M3 ;
      RECT 103.023 0.000 103.041 0.054 ;
    END
  END rw0_rd_out[152]
  PIN rw0_rd_out[153]
    DIRECTION OUTPUT ;
    USE SIGNAL ;
    SHAPE ABUTMENT ;
    PORT
      LAYER M3 ;
      RECT 103.275 0.000 103.293 0.054 ;
    END
  END rw0_rd_out[153]
  PIN rw0_rd_out[154]
    DIRECTION OUTPUT ;
    USE SIGNAL ;
    SHAPE ABUTMENT ;
    PORT
      LAYER M3 ;
      RECT 103.527 0.000 103.545 0.054 ;
    END
  END rw0_rd_out[154]
  PIN rw0_rd_out[155]
    DIRECTION OUTPUT ;
    USE SIGNAL ;
    SHAPE ABUTMENT ;
    PORT
      LAYER M3 ;
      RECT 103.779 0.000 103.797 0.054 ;
    END
  END rw0_rd_out[155]
  PIN rw0_rd_out[156]
    DIRECTION OUTPUT ;
    USE SIGNAL ;
    SHAPE ABUTMENT ;
    PORT
      LAYER M3 ;
      RECT 104.031 0.000 104.049 0.054 ;
    END
  END rw0_rd_out[156]
  PIN rw0_rd_out[157]
    DIRECTION OUTPUT ;
    USE SIGNAL ;
    SHAPE ABUTMENT ;
    PORT
      LAYER M3 ;
      RECT 104.283 0.000 104.301 0.054 ;
    END
  END rw0_rd_out[157]
  PIN rw0_rd_out[158]
    DIRECTION OUTPUT ;
    USE SIGNAL ;
    SHAPE ABUTMENT ;
    PORT
      LAYER M3 ;
      RECT 104.535 0.000 104.553 0.054 ;
    END
  END rw0_rd_out[158]
  PIN rw0_rd_out[159]
    DIRECTION OUTPUT ;
    USE SIGNAL ;
    SHAPE ABUTMENT ;
    PORT
      LAYER M3 ;
      RECT 104.787 0.000 104.805 0.054 ;
    END
  END rw0_rd_out[159]
  PIN rw0_rd_out[160]
    DIRECTION OUTPUT ;
    USE SIGNAL ;
    SHAPE ABUTMENT ;
    PORT
      LAYER M3 ;
      RECT 105.039 0.000 105.057 0.054 ;
    END
  END rw0_rd_out[160]
  PIN rw0_rd_out[161]
    DIRECTION OUTPUT ;
    USE SIGNAL ;
    SHAPE ABUTMENT ;
    PORT
      LAYER M3 ;
      RECT 105.291 0.000 105.309 0.054 ;
    END
  END rw0_rd_out[161]
  PIN rw0_rd_out[162]
    DIRECTION OUTPUT ;
    USE SIGNAL ;
    SHAPE ABUTMENT ;
    PORT
      LAYER M3 ;
      RECT 105.543 0.000 105.561 0.054 ;
    END
  END rw0_rd_out[162]
  PIN rw0_rd_out[163]
    DIRECTION OUTPUT ;
    USE SIGNAL ;
    SHAPE ABUTMENT ;
    PORT
      LAYER M3 ;
      RECT 105.795 0.000 105.813 0.054 ;
    END
  END rw0_rd_out[163]
  PIN rw0_rd_out[164]
    DIRECTION OUTPUT ;
    USE SIGNAL ;
    SHAPE ABUTMENT ;
    PORT
      LAYER M3 ;
      RECT 106.047 0.000 106.065 0.054 ;
    END
  END rw0_rd_out[164]
  PIN rw0_rd_out[165]
    DIRECTION OUTPUT ;
    USE SIGNAL ;
    SHAPE ABUTMENT ;
    PORT
      LAYER M3 ;
      RECT 106.299 0.000 106.317 0.054 ;
    END
  END rw0_rd_out[165]
  PIN rw0_rd_out[166]
    DIRECTION OUTPUT ;
    USE SIGNAL ;
    SHAPE ABUTMENT ;
    PORT
      LAYER M3 ;
      RECT 106.551 0.000 106.569 0.054 ;
    END
  END rw0_rd_out[166]
  PIN rw0_rd_out[167]
    DIRECTION OUTPUT ;
    USE SIGNAL ;
    SHAPE ABUTMENT ;
    PORT
      LAYER M3 ;
      RECT 106.803 0.000 106.821 0.054 ;
    END
  END rw0_rd_out[167]
  PIN rw0_rd_out[168]
    DIRECTION OUTPUT ;
    USE SIGNAL ;
    SHAPE ABUTMENT ;
    PORT
      LAYER M3 ;
      RECT 107.055 0.000 107.073 0.054 ;
    END
  END rw0_rd_out[168]
  PIN rw0_rd_out[169]
    DIRECTION OUTPUT ;
    USE SIGNAL ;
    SHAPE ABUTMENT ;
    PORT
      LAYER M3 ;
      RECT 107.307 0.000 107.325 0.054 ;
    END
  END rw0_rd_out[169]
  PIN rw0_rd_out[170]
    DIRECTION OUTPUT ;
    USE SIGNAL ;
    SHAPE ABUTMENT ;
    PORT
      LAYER M3 ;
      RECT 107.559 0.000 107.577 0.054 ;
    END
  END rw0_rd_out[170]
  PIN rw0_rd_out[171]
    DIRECTION OUTPUT ;
    USE SIGNAL ;
    SHAPE ABUTMENT ;
    PORT
      LAYER M3 ;
      RECT 107.811 0.000 107.829 0.054 ;
    END
  END rw0_rd_out[171]
  PIN rw0_rd_out[172]
    DIRECTION OUTPUT ;
    USE SIGNAL ;
    SHAPE ABUTMENT ;
    PORT
      LAYER M3 ;
      RECT 108.063 0.000 108.081 0.054 ;
    END
  END rw0_rd_out[172]
  PIN rw0_rd_out[173]
    DIRECTION OUTPUT ;
    USE SIGNAL ;
    SHAPE ABUTMENT ;
    PORT
      LAYER M3 ;
      RECT 108.315 0.000 108.333 0.054 ;
    END
  END rw0_rd_out[173]
  PIN rw0_rd_out[174]
    DIRECTION OUTPUT ;
    USE SIGNAL ;
    SHAPE ABUTMENT ;
    PORT
      LAYER M3 ;
      RECT 108.567 0.000 108.585 0.054 ;
    END
  END rw0_rd_out[174]
  PIN rw0_rd_out[175]
    DIRECTION OUTPUT ;
    USE SIGNAL ;
    SHAPE ABUTMENT ;
    PORT
      LAYER M3 ;
      RECT 108.819 0.000 108.837 0.054 ;
    END
  END rw0_rd_out[175]
  PIN rw0_rd_out[176]
    DIRECTION OUTPUT ;
    USE SIGNAL ;
    SHAPE ABUTMENT ;
    PORT
      LAYER M3 ;
      RECT 109.071 0.000 109.089 0.054 ;
    END
  END rw0_rd_out[176]
  PIN rw0_rd_out[177]
    DIRECTION OUTPUT ;
    USE SIGNAL ;
    SHAPE ABUTMENT ;
    PORT
      LAYER M3 ;
      RECT 109.323 0.000 109.341 0.054 ;
    END
  END rw0_rd_out[177]
  PIN rw0_rd_out[178]
    DIRECTION OUTPUT ;
    USE SIGNAL ;
    SHAPE ABUTMENT ;
    PORT
      LAYER M3 ;
      RECT 109.575 0.000 109.593 0.054 ;
    END
  END rw0_rd_out[178]
  PIN rw0_rd_out[179]
    DIRECTION OUTPUT ;
    USE SIGNAL ;
    SHAPE ABUTMENT ;
    PORT
      LAYER M3 ;
      RECT 109.827 0.000 109.845 0.054 ;
    END
  END rw0_rd_out[179]
  PIN rw0_rd_out[180]
    DIRECTION OUTPUT ;
    USE SIGNAL ;
    SHAPE ABUTMENT ;
    PORT
      LAYER M3 ;
      RECT 110.079 0.000 110.097 0.054 ;
    END
  END rw0_rd_out[180]
  PIN rw0_rd_out[181]
    DIRECTION OUTPUT ;
    USE SIGNAL ;
    SHAPE ABUTMENT ;
    PORT
      LAYER M3 ;
      RECT 110.331 0.000 110.349 0.054 ;
    END
  END rw0_rd_out[181]
  PIN rw0_rd_out[182]
    DIRECTION OUTPUT ;
    USE SIGNAL ;
    SHAPE ABUTMENT ;
    PORT
      LAYER M3 ;
      RECT 110.583 0.000 110.601 0.054 ;
    END
  END rw0_rd_out[182]
  PIN rw0_rd_out[183]
    DIRECTION OUTPUT ;
    USE SIGNAL ;
    SHAPE ABUTMENT ;
    PORT
      LAYER M3 ;
      RECT 110.835 0.000 110.853 0.054 ;
    END
  END rw0_rd_out[183]
  PIN rw0_rd_out[184]
    DIRECTION OUTPUT ;
    USE SIGNAL ;
    SHAPE ABUTMENT ;
    PORT
      LAYER M3 ;
      RECT 111.087 0.000 111.105 0.054 ;
    END
  END rw0_rd_out[184]
  PIN rw0_rd_out[185]
    DIRECTION OUTPUT ;
    USE SIGNAL ;
    SHAPE ABUTMENT ;
    PORT
      LAYER M3 ;
      RECT 111.339 0.000 111.357 0.054 ;
    END
  END rw0_rd_out[185]
  PIN rw0_rd_out[186]
    DIRECTION OUTPUT ;
    USE SIGNAL ;
    SHAPE ABUTMENT ;
    PORT
      LAYER M3 ;
      RECT 111.591 0.000 111.609 0.054 ;
    END
  END rw0_rd_out[186]
  PIN rw0_rd_out[187]
    DIRECTION OUTPUT ;
    USE SIGNAL ;
    SHAPE ABUTMENT ;
    PORT
      LAYER M3 ;
      RECT 111.843 0.000 111.861 0.054 ;
    END
  END rw0_rd_out[187]
  PIN rw0_rd_out[188]
    DIRECTION OUTPUT ;
    USE SIGNAL ;
    SHAPE ABUTMENT ;
    PORT
      LAYER M3 ;
      RECT 112.095 0.000 112.113 0.054 ;
    END
  END rw0_rd_out[188]
  PIN rw0_rd_out[189]
    DIRECTION OUTPUT ;
    USE SIGNAL ;
    SHAPE ABUTMENT ;
    PORT
      LAYER M3 ;
      RECT 112.347 0.000 112.365 0.054 ;
    END
  END rw0_rd_out[189]
  PIN rw0_rd_out[190]
    DIRECTION OUTPUT ;
    USE SIGNAL ;
    SHAPE ABUTMENT ;
    PORT
      LAYER M3 ;
      RECT 112.599 0.000 112.617 0.054 ;
    END
  END rw0_rd_out[190]
  PIN rw0_rd_out[191]
    DIRECTION OUTPUT ;
    USE SIGNAL ;
    SHAPE ABUTMENT ;
    PORT
      LAYER M3 ;
      RECT 112.851 0.000 112.869 0.054 ;
    END
  END rw0_rd_out[191]
  PIN rw0_rd_out[192]
    DIRECTION OUTPUT ;
    USE SIGNAL ;
    SHAPE ABUTMENT ;
    PORT
      LAYER M3 ;
      RECT 113.103 0.000 113.121 0.054 ;
    END
  END rw0_rd_out[192]
  PIN rw0_rd_out[193]
    DIRECTION OUTPUT ;
    USE SIGNAL ;
    SHAPE ABUTMENT ;
    PORT
      LAYER M3 ;
      RECT 113.355 0.000 113.373 0.054 ;
    END
  END rw0_rd_out[193]
  PIN rw0_rd_out[194]
    DIRECTION OUTPUT ;
    USE SIGNAL ;
    SHAPE ABUTMENT ;
    PORT
      LAYER M3 ;
      RECT 113.607 0.000 113.625 0.054 ;
    END
  END rw0_rd_out[194]
  PIN rw0_rd_out[195]
    DIRECTION OUTPUT ;
    USE SIGNAL ;
    SHAPE ABUTMENT ;
    PORT
      LAYER M3 ;
      RECT 113.859 0.000 113.877 0.054 ;
    END
  END rw0_rd_out[195]
  PIN rw0_rd_out[196]
    DIRECTION OUTPUT ;
    USE SIGNAL ;
    SHAPE ABUTMENT ;
    PORT
      LAYER M3 ;
      RECT 114.111 0.000 114.129 0.054 ;
    END
  END rw0_rd_out[196]
  PIN rw0_rd_out[197]
    DIRECTION OUTPUT ;
    USE SIGNAL ;
    SHAPE ABUTMENT ;
    PORT
      LAYER M3 ;
      RECT 114.363 0.000 114.381 0.054 ;
    END
  END rw0_rd_out[197]
  PIN rw0_rd_out[198]
    DIRECTION OUTPUT ;
    USE SIGNAL ;
    SHAPE ABUTMENT ;
    PORT
      LAYER M3 ;
      RECT 114.615 0.000 114.633 0.054 ;
    END
  END rw0_rd_out[198]
  PIN rw0_rd_out[199]
    DIRECTION OUTPUT ;
    USE SIGNAL ;
    SHAPE ABUTMENT ;
    PORT
      LAYER M3 ;
      RECT 114.867 0.000 114.885 0.054 ;
    END
  END rw0_rd_out[199]
  PIN rw0_rd_out[200]
    DIRECTION OUTPUT ;
    USE SIGNAL ;
    SHAPE ABUTMENT ;
    PORT
      LAYER M3 ;
      RECT 115.119 0.000 115.137 0.054 ;
    END
  END rw0_rd_out[200]
  PIN rw0_rd_out[201]
    DIRECTION OUTPUT ;
    USE SIGNAL ;
    SHAPE ABUTMENT ;
    PORT
      LAYER M3 ;
      RECT 115.371 0.000 115.389 0.054 ;
    END
  END rw0_rd_out[201]
  PIN rw0_rd_out[202]
    DIRECTION OUTPUT ;
    USE SIGNAL ;
    SHAPE ABUTMENT ;
    PORT
      LAYER M3 ;
      RECT 115.623 0.000 115.641 0.054 ;
    END
  END rw0_rd_out[202]
  PIN rw0_rd_out[203]
    DIRECTION OUTPUT ;
    USE SIGNAL ;
    SHAPE ABUTMENT ;
    PORT
      LAYER M3 ;
      RECT 115.875 0.000 115.893 0.054 ;
    END
  END rw0_rd_out[203]
  PIN rw0_rd_out[204]
    DIRECTION OUTPUT ;
    USE SIGNAL ;
    SHAPE ABUTMENT ;
    PORT
      LAYER M3 ;
      RECT 116.127 0.000 116.145 0.054 ;
    END
  END rw0_rd_out[204]
  PIN rw0_rd_out[205]
    DIRECTION OUTPUT ;
    USE SIGNAL ;
    SHAPE ABUTMENT ;
    PORT
      LAYER M3 ;
      RECT 116.379 0.000 116.397 0.054 ;
    END
  END rw0_rd_out[205]
  PIN rw0_rd_out[206]
    DIRECTION OUTPUT ;
    USE SIGNAL ;
    SHAPE ABUTMENT ;
    PORT
      LAYER M3 ;
      RECT 116.631 0.000 116.649 0.054 ;
    END
  END rw0_rd_out[206]
  PIN rw0_rd_out[207]
    DIRECTION OUTPUT ;
    USE SIGNAL ;
    SHAPE ABUTMENT ;
    PORT
      LAYER M3 ;
      RECT 116.883 0.000 116.901 0.054 ;
    END
  END rw0_rd_out[207]
  PIN rw0_rd_out[208]
    DIRECTION OUTPUT ;
    USE SIGNAL ;
    SHAPE ABUTMENT ;
    PORT
      LAYER M3 ;
      RECT 117.135 0.000 117.153 0.054 ;
    END
  END rw0_rd_out[208]
  PIN rw0_rd_out[209]
    DIRECTION OUTPUT ;
    USE SIGNAL ;
    SHAPE ABUTMENT ;
    PORT
      LAYER M3 ;
      RECT 117.387 0.000 117.405 0.054 ;
    END
  END rw0_rd_out[209]
  PIN rw0_rd_out[210]
    DIRECTION OUTPUT ;
    USE SIGNAL ;
    SHAPE ABUTMENT ;
    PORT
      LAYER M3 ;
      RECT 117.639 0.000 117.657 0.054 ;
    END
  END rw0_rd_out[210]
  PIN rw0_rd_out[211]
    DIRECTION OUTPUT ;
    USE SIGNAL ;
    SHAPE ABUTMENT ;
    PORT
      LAYER M3 ;
      RECT 117.891 0.000 117.909 0.054 ;
    END
  END rw0_rd_out[211]
  PIN rw0_rd_out[212]
    DIRECTION OUTPUT ;
    USE SIGNAL ;
    SHAPE ABUTMENT ;
    PORT
      LAYER M3 ;
      RECT 118.143 0.000 118.161 0.054 ;
    END
  END rw0_rd_out[212]
  PIN rw0_rd_out[213]
    DIRECTION OUTPUT ;
    USE SIGNAL ;
    SHAPE ABUTMENT ;
    PORT
      LAYER M3 ;
      RECT 118.395 0.000 118.413 0.054 ;
    END
  END rw0_rd_out[213]
  PIN rw0_rd_out[214]
    DIRECTION OUTPUT ;
    USE SIGNAL ;
    SHAPE ABUTMENT ;
    PORT
      LAYER M3 ;
      RECT 118.647 0.000 118.665 0.054 ;
    END
  END rw0_rd_out[214]
  PIN rw0_rd_out[215]
    DIRECTION OUTPUT ;
    USE SIGNAL ;
    SHAPE ABUTMENT ;
    PORT
      LAYER M3 ;
      RECT 118.899 0.000 118.917 0.054 ;
    END
  END rw0_rd_out[215]
  PIN rw0_rd_out[216]
    DIRECTION OUTPUT ;
    USE SIGNAL ;
    SHAPE ABUTMENT ;
    PORT
      LAYER M3 ;
      RECT 119.151 0.000 119.169 0.054 ;
    END
  END rw0_rd_out[216]
  PIN rw0_rd_out[217]
    DIRECTION OUTPUT ;
    USE SIGNAL ;
    SHAPE ABUTMENT ;
    PORT
      LAYER M3 ;
      RECT 119.403 0.000 119.421 0.054 ;
    END
  END rw0_rd_out[217]
  PIN rw0_rd_out[218]
    DIRECTION OUTPUT ;
    USE SIGNAL ;
    SHAPE ABUTMENT ;
    PORT
      LAYER M3 ;
      RECT 119.655 0.000 119.673 0.054 ;
    END
  END rw0_rd_out[218]
  PIN rw0_rd_out[219]
    DIRECTION OUTPUT ;
    USE SIGNAL ;
    SHAPE ABUTMENT ;
    PORT
      LAYER M3 ;
      RECT 119.907 0.000 119.925 0.054 ;
    END
  END rw0_rd_out[219]
  PIN rw0_rd_out[220]
    DIRECTION OUTPUT ;
    USE SIGNAL ;
    SHAPE ABUTMENT ;
    PORT
      LAYER M3 ;
      RECT 120.159 0.000 120.177 0.054 ;
    END
  END rw0_rd_out[220]
  PIN rw0_rd_out[221]
    DIRECTION OUTPUT ;
    USE SIGNAL ;
    SHAPE ABUTMENT ;
    PORT
      LAYER M3 ;
      RECT 120.411 0.000 120.429 0.054 ;
    END
  END rw0_rd_out[221]
  PIN rw0_rd_out[222]
    DIRECTION OUTPUT ;
    USE SIGNAL ;
    SHAPE ABUTMENT ;
    PORT
      LAYER M3 ;
      RECT 120.663 0.000 120.681 0.054 ;
    END
  END rw0_rd_out[222]
  PIN rw0_rd_out[223]
    DIRECTION OUTPUT ;
    USE SIGNAL ;
    SHAPE ABUTMENT ;
    PORT
      LAYER M3 ;
      RECT 120.915 0.000 120.933 0.054 ;
    END
  END rw0_rd_out[223]
  PIN rw0_rd_out[224]
    DIRECTION OUTPUT ;
    USE SIGNAL ;
    SHAPE ABUTMENT ;
    PORT
      LAYER M3 ;
      RECT 121.167 0.000 121.185 0.054 ;
    END
  END rw0_rd_out[224]
  PIN rw0_rd_out[225]
    DIRECTION OUTPUT ;
    USE SIGNAL ;
    SHAPE ABUTMENT ;
    PORT
      LAYER M3 ;
      RECT 121.419 0.000 121.437 0.054 ;
    END
  END rw0_rd_out[225]
  PIN rw0_rd_out[226]
    DIRECTION OUTPUT ;
    USE SIGNAL ;
    SHAPE ABUTMENT ;
    PORT
      LAYER M3 ;
      RECT 121.671 0.000 121.689 0.054 ;
    END
  END rw0_rd_out[226]
  PIN rw0_rd_out[227]
    DIRECTION OUTPUT ;
    USE SIGNAL ;
    SHAPE ABUTMENT ;
    PORT
      LAYER M3 ;
      RECT 121.923 0.000 121.941 0.054 ;
    END
  END rw0_rd_out[227]
  PIN rw0_rd_out[228]
    DIRECTION OUTPUT ;
    USE SIGNAL ;
    SHAPE ABUTMENT ;
    PORT
      LAYER M3 ;
      RECT 122.175 0.000 122.193 0.054 ;
    END
  END rw0_rd_out[228]
  PIN rw0_rd_out[229]
    DIRECTION OUTPUT ;
    USE SIGNAL ;
    SHAPE ABUTMENT ;
    PORT
      LAYER M3 ;
      RECT 122.427 0.000 122.445 0.054 ;
    END
  END rw0_rd_out[229]
  PIN rw0_rd_out[230]
    DIRECTION OUTPUT ;
    USE SIGNAL ;
    SHAPE ABUTMENT ;
    PORT
      LAYER M3 ;
      RECT 122.679 0.000 122.697 0.054 ;
    END
  END rw0_rd_out[230]
  PIN rw0_rd_out[231]
    DIRECTION OUTPUT ;
    USE SIGNAL ;
    SHAPE ABUTMENT ;
    PORT
      LAYER M3 ;
      RECT 122.931 0.000 122.949 0.054 ;
    END
  END rw0_rd_out[231]
  PIN rw0_rd_out[232]
    DIRECTION OUTPUT ;
    USE SIGNAL ;
    SHAPE ABUTMENT ;
    PORT
      LAYER M3 ;
      RECT 123.183 0.000 123.201 0.054 ;
    END
  END rw0_rd_out[232]
  PIN rw0_rd_out[233]
    DIRECTION OUTPUT ;
    USE SIGNAL ;
    SHAPE ABUTMENT ;
    PORT
      LAYER M3 ;
      RECT 123.435 0.000 123.453 0.054 ;
    END
  END rw0_rd_out[233]
  PIN rw0_rd_out[234]
    DIRECTION OUTPUT ;
    USE SIGNAL ;
    SHAPE ABUTMENT ;
    PORT
      LAYER M3 ;
      RECT 123.687 0.000 123.705 0.054 ;
    END
  END rw0_rd_out[234]
  PIN rw0_rd_out[235]
    DIRECTION OUTPUT ;
    USE SIGNAL ;
    SHAPE ABUTMENT ;
    PORT
      LAYER M3 ;
      RECT 123.939 0.000 123.957 0.054 ;
    END
  END rw0_rd_out[235]
  PIN rw0_rd_out[236]
    DIRECTION OUTPUT ;
    USE SIGNAL ;
    SHAPE ABUTMENT ;
    PORT
      LAYER M3 ;
      RECT 124.191 0.000 124.209 0.054 ;
    END
  END rw0_rd_out[236]
  PIN rw0_rd_out[237]
    DIRECTION OUTPUT ;
    USE SIGNAL ;
    SHAPE ABUTMENT ;
    PORT
      LAYER M3 ;
      RECT 124.443 0.000 124.461 0.054 ;
    END
  END rw0_rd_out[237]
  PIN rw0_rd_out[238]
    DIRECTION OUTPUT ;
    USE SIGNAL ;
    SHAPE ABUTMENT ;
    PORT
      LAYER M3 ;
      RECT 124.695 0.000 124.713 0.054 ;
    END
  END rw0_rd_out[238]
  PIN rw0_rd_out[239]
    DIRECTION OUTPUT ;
    USE SIGNAL ;
    SHAPE ABUTMENT ;
    PORT
      LAYER M3 ;
      RECT 124.947 0.000 124.965 0.054 ;
    END
  END rw0_rd_out[239]
  PIN rw0_rd_out[240]
    DIRECTION OUTPUT ;
    USE SIGNAL ;
    SHAPE ABUTMENT ;
    PORT
      LAYER M3 ;
      RECT 125.199 0.000 125.217 0.054 ;
    END
  END rw0_rd_out[240]
  PIN rw0_rd_out[241]
    DIRECTION OUTPUT ;
    USE SIGNAL ;
    SHAPE ABUTMENT ;
    PORT
      LAYER M3 ;
      RECT 125.451 0.000 125.469 0.054 ;
    END
  END rw0_rd_out[241]
  PIN rw0_rd_out[242]
    DIRECTION OUTPUT ;
    USE SIGNAL ;
    SHAPE ABUTMENT ;
    PORT
      LAYER M3 ;
      RECT 125.703 0.000 125.721 0.054 ;
    END
  END rw0_rd_out[242]
  PIN rw0_rd_out[243]
    DIRECTION OUTPUT ;
    USE SIGNAL ;
    SHAPE ABUTMENT ;
    PORT
      LAYER M3 ;
      RECT 125.955 0.000 125.973 0.054 ;
    END
  END rw0_rd_out[243]
  PIN rw0_rd_out[244]
    DIRECTION OUTPUT ;
    USE SIGNAL ;
    SHAPE ABUTMENT ;
    PORT
      LAYER M3 ;
      RECT 126.207 0.000 126.225 0.054 ;
    END
  END rw0_rd_out[244]
  PIN rw0_rd_out[245]
    DIRECTION OUTPUT ;
    USE SIGNAL ;
    SHAPE ABUTMENT ;
    PORT
      LAYER M3 ;
      RECT 126.459 0.000 126.477 0.054 ;
    END
  END rw0_rd_out[245]
  PIN rw0_rd_out[246]
    DIRECTION OUTPUT ;
    USE SIGNAL ;
    SHAPE ABUTMENT ;
    PORT
      LAYER M3 ;
      RECT 126.711 0.000 126.729 0.054 ;
    END
  END rw0_rd_out[246]
  PIN rw0_rd_out[247]
    DIRECTION OUTPUT ;
    USE SIGNAL ;
    SHAPE ABUTMENT ;
    PORT
      LAYER M3 ;
      RECT 126.963 0.000 126.981 0.054 ;
    END
  END rw0_rd_out[247]
  PIN rw0_rd_out[248]
    DIRECTION OUTPUT ;
    USE SIGNAL ;
    SHAPE ABUTMENT ;
    PORT
      LAYER M3 ;
      RECT 127.215 0.000 127.233 0.054 ;
    END
  END rw0_rd_out[248]
  PIN rw0_rd_out[249]
    DIRECTION OUTPUT ;
    USE SIGNAL ;
    SHAPE ABUTMENT ;
    PORT
      LAYER M3 ;
      RECT 127.467 0.000 127.485 0.054 ;
    END
  END rw0_rd_out[249]
  PIN rw0_rd_out[250]
    DIRECTION OUTPUT ;
    USE SIGNAL ;
    SHAPE ABUTMENT ;
    PORT
      LAYER M3 ;
      RECT 127.719 0.000 127.737 0.054 ;
    END
  END rw0_rd_out[250]
  PIN rw0_rd_out[251]
    DIRECTION OUTPUT ;
    USE SIGNAL ;
    SHAPE ABUTMENT ;
    PORT
      LAYER M3 ;
      RECT 127.971 0.000 127.989 0.054 ;
    END
  END rw0_rd_out[251]
  PIN rw0_rd_out[252]
    DIRECTION OUTPUT ;
    USE SIGNAL ;
    SHAPE ABUTMENT ;
    PORT
      LAYER M3 ;
      RECT 128.223 0.000 128.241 0.054 ;
    END
  END rw0_rd_out[252]
  PIN rw0_rd_out[253]
    DIRECTION OUTPUT ;
    USE SIGNAL ;
    SHAPE ABUTMENT ;
    PORT
      LAYER M3 ;
      RECT 128.475 0.000 128.493 0.054 ;
    END
  END rw0_rd_out[253]
  PIN rw0_rd_out[254]
    DIRECTION OUTPUT ;
    USE SIGNAL ;
    SHAPE ABUTMENT ;
    PORT
      LAYER M3 ;
      RECT 128.727 0.000 128.745 0.054 ;
    END
  END rw0_rd_out[254]
  PIN rw0_rd_out[255]
    DIRECTION OUTPUT ;
    USE SIGNAL ;
    SHAPE ABUTMENT ;
    PORT
      LAYER M3 ;
      RECT 128.979 0.000 128.997 0.054 ;
    END
  END rw0_rd_out[255]
  PIN rw0_rd_out[256]
    DIRECTION OUTPUT ;
    USE SIGNAL ;
    SHAPE ABUTMENT ;
    PORT
      LAYER M3 ;
      RECT 0.207 43.346 0.225 43.400 ;
    END
  END rw0_rd_out[256]
  PIN rw0_rd_out[257]
    DIRECTION OUTPUT ;
    USE SIGNAL ;
    SHAPE ABUTMENT ;
    PORT
      LAYER M3 ;
      RECT 0.711 43.346 0.729 43.400 ;
    END
  END rw0_rd_out[257]
  PIN rw0_rd_out[258]
    DIRECTION OUTPUT ;
    USE SIGNAL ;
    SHAPE ABUTMENT ;
    PORT
      LAYER M3 ;
      RECT 1.215 43.346 1.233 43.400 ;
    END
  END rw0_rd_out[258]
  PIN rw0_rd_out[259]
    DIRECTION OUTPUT ;
    USE SIGNAL ;
    SHAPE ABUTMENT ;
    PORT
      LAYER M3 ;
      RECT 1.719 43.346 1.737 43.400 ;
    END
  END rw0_rd_out[259]
  PIN rw0_rd_out[260]
    DIRECTION OUTPUT ;
    USE SIGNAL ;
    SHAPE ABUTMENT ;
    PORT
      LAYER M3 ;
      RECT 2.223 43.346 2.241 43.400 ;
    END
  END rw0_rd_out[260]
  PIN rw0_rd_out[261]
    DIRECTION OUTPUT ;
    USE SIGNAL ;
    SHAPE ABUTMENT ;
    PORT
      LAYER M3 ;
      RECT 2.727 43.346 2.745 43.400 ;
    END
  END rw0_rd_out[261]
  PIN rw0_rd_out[262]
    DIRECTION OUTPUT ;
    USE SIGNAL ;
    SHAPE ABUTMENT ;
    PORT
      LAYER M3 ;
      RECT 3.231 43.346 3.249 43.400 ;
    END
  END rw0_rd_out[262]
  PIN rw0_rd_out[263]
    DIRECTION OUTPUT ;
    USE SIGNAL ;
    SHAPE ABUTMENT ;
    PORT
      LAYER M3 ;
      RECT 3.735 43.346 3.753 43.400 ;
    END
  END rw0_rd_out[263]
  PIN rw0_rd_out[264]
    DIRECTION OUTPUT ;
    USE SIGNAL ;
    SHAPE ABUTMENT ;
    PORT
      LAYER M3 ;
      RECT 4.239 43.346 4.257 43.400 ;
    END
  END rw0_rd_out[264]
  PIN rw0_rd_out[265]
    DIRECTION OUTPUT ;
    USE SIGNAL ;
    SHAPE ABUTMENT ;
    PORT
      LAYER M3 ;
      RECT 4.743 43.346 4.761 43.400 ;
    END
  END rw0_rd_out[265]
  PIN rw0_rd_out[266]
    DIRECTION OUTPUT ;
    USE SIGNAL ;
    SHAPE ABUTMENT ;
    PORT
      LAYER M3 ;
      RECT 5.247 43.346 5.265 43.400 ;
    END
  END rw0_rd_out[266]
  PIN rw0_rd_out[267]
    DIRECTION OUTPUT ;
    USE SIGNAL ;
    SHAPE ABUTMENT ;
    PORT
      LAYER M3 ;
      RECT 5.751 43.346 5.769 43.400 ;
    END
  END rw0_rd_out[267]
  PIN rw0_rd_out[268]
    DIRECTION OUTPUT ;
    USE SIGNAL ;
    SHAPE ABUTMENT ;
    PORT
      LAYER M3 ;
      RECT 6.255 43.346 6.273 43.400 ;
    END
  END rw0_rd_out[268]
  PIN rw0_rd_out[269]
    DIRECTION OUTPUT ;
    USE SIGNAL ;
    SHAPE ABUTMENT ;
    PORT
      LAYER M3 ;
      RECT 6.759 43.346 6.777 43.400 ;
    END
  END rw0_rd_out[269]
  PIN rw0_rd_out[270]
    DIRECTION OUTPUT ;
    USE SIGNAL ;
    SHAPE ABUTMENT ;
    PORT
      LAYER M3 ;
      RECT 7.263 43.346 7.281 43.400 ;
    END
  END rw0_rd_out[270]
  PIN rw0_rd_out[271]
    DIRECTION OUTPUT ;
    USE SIGNAL ;
    SHAPE ABUTMENT ;
    PORT
      LAYER M3 ;
      RECT 7.767 43.346 7.785 43.400 ;
    END
  END rw0_rd_out[271]
  PIN rw0_rd_out[272]
    DIRECTION OUTPUT ;
    USE SIGNAL ;
    SHAPE ABUTMENT ;
    PORT
      LAYER M3 ;
      RECT 8.271 43.346 8.289 43.400 ;
    END
  END rw0_rd_out[272]
  PIN rw0_rd_out[273]
    DIRECTION OUTPUT ;
    USE SIGNAL ;
    SHAPE ABUTMENT ;
    PORT
      LAYER M3 ;
      RECT 8.775 43.346 8.793 43.400 ;
    END
  END rw0_rd_out[273]
  PIN rw0_rd_out[274]
    DIRECTION OUTPUT ;
    USE SIGNAL ;
    SHAPE ABUTMENT ;
    PORT
      LAYER M3 ;
      RECT 9.279 43.346 9.297 43.400 ;
    END
  END rw0_rd_out[274]
  PIN rw0_rd_out[275]
    DIRECTION OUTPUT ;
    USE SIGNAL ;
    SHAPE ABUTMENT ;
    PORT
      LAYER M3 ;
      RECT 9.783 43.346 9.801 43.400 ;
    END
  END rw0_rd_out[275]
  PIN rw0_rd_out[276]
    DIRECTION OUTPUT ;
    USE SIGNAL ;
    SHAPE ABUTMENT ;
    PORT
      LAYER M3 ;
      RECT 10.287 43.346 10.305 43.400 ;
    END
  END rw0_rd_out[276]
  PIN rw0_rd_out[277]
    DIRECTION OUTPUT ;
    USE SIGNAL ;
    SHAPE ABUTMENT ;
    PORT
      LAYER M3 ;
      RECT 10.791 43.346 10.809 43.400 ;
    END
  END rw0_rd_out[277]
  PIN rw0_rd_out[278]
    DIRECTION OUTPUT ;
    USE SIGNAL ;
    SHAPE ABUTMENT ;
    PORT
      LAYER M3 ;
      RECT 11.295 43.346 11.313 43.400 ;
    END
  END rw0_rd_out[278]
  PIN rw0_rd_out[279]
    DIRECTION OUTPUT ;
    USE SIGNAL ;
    SHAPE ABUTMENT ;
    PORT
      LAYER M3 ;
      RECT 11.799 43.346 11.817 43.400 ;
    END
  END rw0_rd_out[279]
  PIN rw0_rd_out[280]
    DIRECTION OUTPUT ;
    USE SIGNAL ;
    SHAPE ABUTMENT ;
    PORT
      LAYER M3 ;
      RECT 12.303 43.346 12.321 43.400 ;
    END
  END rw0_rd_out[280]
  PIN rw0_rd_out[281]
    DIRECTION OUTPUT ;
    USE SIGNAL ;
    SHAPE ABUTMENT ;
    PORT
      LAYER M3 ;
      RECT 12.807 43.346 12.825 43.400 ;
    END
  END rw0_rd_out[281]
  PIN rw0_rd_out[282]
    DIRECTION OUTPUT ;
    USE SIGNAL ;
    SHAPE ABUTMENT ;
    PORT
      LAYER M3 ;
      RECT 13.311 43.346 13.329 43.400 ;
    END
  END rw0_rd_out[282]
  PIN rw0_rd_out[283]
    DIRECTION OUTPUT ;
    USE SIGNAL ;
    SHAPE ABUTMENT ;
    PORT
      LAYER M3 ;
      RECT 13.815 43.346 13.833 43.400 ;
    END
  END rw0_rd_out[283]
  PIN rw0_rd_out[284]
    DIRECTION OUTPUT ;
    USE SIGNAL ;
    SHAPE ABUTMENT ;
    PORT
      LAYER M3 ;
      RECT 14.319 43.346 14.337 43.400 ;
    END
  END rw0_rd_out[284]
  PIN rw0_rd_out[285]
    DIRECTION OUTPUT ;
    USE SIGNAL ;
    SHAPE ABUTMENT ;
    PORT
      LAYER M3 ;
      RECT 14.823 43.346 14.841 43.400 ;
    END
  END rw0_rd_out[285]
  PIN rw0_rd_out[286]
    DIRECTION OUTPUT ;
    USE SIGNAL ;
    SHAPE ABUTMENT ;
    PORT
      LAYER M3 ;
      RECT 15.327 43.346 15.345 43.400 ;
    END
  END rw0_rd_out[286]
  PIN rw0_rd_out[287]
    DIRECTION OUTPUT ;
    USE SIGNAL ;
    SHAPE ABUTMENT ;
    PORT
      LAYER M3 ;
      RECT 15.831 43.346 15.849 43.400 ;
    END
  END rw0_rd_out[287]
  PIN rw0_rd_out[288]
    DIRECTION OUTPUT ;
    USE SIGNAL ;
    SHAPE ABUTMENT ;
    PORT
      LAYER M3 ;
      RECT 16.335 43.346 16.353 43.400 ;
    END
  END rw0_rd_out[288]
  PIN rw0_rd_out[289]
    DIRECTION OUTPUT ;
    USE SIGNAL ;
    SHAPE ABUTMENT ;
    PORT
      LAYER M3 ;
      RECT 16.839 43.346 16.857 43.400 ;
    END
  END rw0_rd_out[289]
  PIN rw0_rd_out[290]
    DIRECTION OUTPUT ;
    USE SIGNAL ;
    SHAPE ABUTMENT ;
    PORT
      LAYER M3 ;
      RECT 17.343 43.346 17.361 43.400 ;
    END
  END rw0_rd_out[290]
  PIN rw0_rd_out[291]
    DIRECTION OUTPUT ;
    USE SIGNAL ;
    SHAPE ABUTMENT ;
    PORT
      LAYER M3 ;
      RECT 17.847 43.346 17.865 43.400 ;
    END
  END rw0_rd_out[291]
  PIN rw0_rd_out[292]
    DIRECTION OUTPUT ;
    USE SIGNAL ;
    SHAPE ABUTMENT ;
    PORT
      LAYER M3 ;
      RECT 18.351 43.346 18.369 43.400 ;
    END
  END rw0_rd_out[292]
  PIN rw0_rd_out[293]
    DIRECTION OUTPUT ;
    USE SIGNAL ;
    SHAPE ABUTMENT ;
    PORT
      LAYER M3 ;
      RECT 18.855 43.346 18.873 43.400 ;
    END
  END rw0_rd_out[293]
  PIN rw0_rd_out[294]
    DIRECTION OUTPUT ;
    USE SIGNAL ;
    SHAPE ABUTMENT ;
    PORT
      LAYER M3 ;
      RECT 19.359 43.346 19.377 43.400 ;
    END
  END rw0_rd_out[294]
  PIN rw0_rd_out[295]
    DIRECTION OUTPUT ;
    USE SIGNAL ;
    SHAPE ABUTMENT ;
    PORT
      LAYER M3 ;
      RECT 19.863 43.346 19.881 43.400 ;
    END
  END rw0_rd_out[295]
  PIN rw0_rd_out[296]
    DIRECTION OUTPUT ;
    USE SIGNAL ;
    SHAPE ABUTMENT ;
    PORT
      LAYER M3 ;
      RECT 20.367 43.346 20.385 43.400 ;
    END
  END rw0_rd_out[296]
  PIN rw0_rd_out[297]
    DIRECTION OUTPUT ;
    USE SIGNAL ;
    SHAPE ABUTMENT ;
    PORT
      LAYER M3 ;
      RECT 20.871 43.346 20.889 43.400 ;
    END
  END rw0_rd_out[297]
  PIN rw0_rd_out[298]
    DIRECTION OUTPUT ;
    USE SIGNAL ;
    SHAPE ABUTMENT ;
    PORT
      LAYER M3 ;
      RECT 21.375 43.346 21.393 43.400 ;
    END
  END rw0_rd_out[298]
  PIN rw0_rd_out[299]
    DIRECTION OUTPUT ;
    USE SIGNAL ;
    SHAPE ABUTMENT ;
    PORT
      LAYER M3 ;
      RECT 21.879 43.346 21.897 43.400 ;
    END
  END rw0_rd_out[299]
  PIN rw0_rd_out[300]
    DIRECTION OUTPUT ;
    USE SIGNAL ;
    SHAPE ABUTMENT ;
    PORT
      LAYER M3 ;
      RECT 22.383 43.346 22.401 43.400 ;
    END
  END rw0_rd_out[300]
  PIN rw0_rd_out[301]
    DIRECTION OUTPUT ;
    USE SIGNAL ;
    SHAPE ABUTMENT ;
    PORT
      LAYER M3 ;
      RECT 22.887 43.346 22.905 43.400 ;
    END
  END rw0_rd_out[301]
  PIN rw0_rd_out[302]
    DIRECTION OUTPUT ;
    USE SIGNAL ;
    SHAPE ABUTMENT ;
    PORT
      LAYER M3 ;
      RECT 23.391 43.346 23.409 43.400 ;
    END
  END rw0_rd_out[302]
  PIN rw0_rd_out[303]
    DIRECTION OUTPUT ;
    USE SIGNAL ;
    SHAPE ABUTMENT ;
    PORT
      LAYER M3 ;
      RECT 23.895 43.346 23.913 43.400 ;
    END
  END rw0_rd_out[303]
  PIN rw0_rd_out[304]
    DIRECTION OUTPUT ;
    USE SIGNAL ;
    SHAPE ABUTMENT ;
    PORT
      LAYER M3 ;
      RECT 24.399 43.346 24.417 43.400 ;
    END
  END rw0_rd_out[304]
  PIN rw0_rd_out[305]
    DIRECTION OUTPUT ;
    USE SIGNAL ;
    SHAPE ABUTMENT ;
    PORT
      LAYER M3 ;
      RECT 24.903 43.346 24.921 43.400 ;
    END
  END rw0_rd_out[305]
  PIN rw0_rd_out[306]
    DIRECTION OUTPUT ;
    USE SIGNAL ;
    SHAPE ABUTMENT ;
    PORT
      LAYER M3 ;
      RECT 25.407 43.346 25.425 43.400 ;
    END
  END rw0_rd_out[306]
  PIN rw0_rd_out[307]
    DIRECTION OUTPUT ;
    USE SIGNAL ;
    SHAPE ABUTMENT ;
    PORT
      LAYER M3 ;
      RECT 25.911 43.346 25.929 43.400 ;
    END
  END rw0_rd_out[307]
  PIN rw0_rd_out[308]
    DIRECTION OUTPUT ;
    USE SIGNAL ;
    SHAPE ABUTMENT ;
    PORT
      LAYER M3 ;
      RECT 26.415 43.346 26.433 43.400 ;
    END
  END rw0_rd_out[308]
  PIN rw0_rd_out[309]
    DIRECTION OUTPUT ;
    USE SIGNAL ;
    SHAPE ABUTMENT ;
    PORT
      LAYER M3 ;
      RECT 26.919 43.346 26.937 43.400 ;
    END
  END rw0_rd_out[309]
  PIN rw0_rd_out[310]
    DIRECTION OUTPUT ;
    USE SIGNAL ;
    SHAPE ABUTMENT ;
    PORT
      LAYER M3 ;
      RECT 27.423 43.346 27.441 43.400 ;
    END
  END rw0_rd_out[310]
  PIN rw0_rd_out[311]
    DIRECTION OUTPUT ;
    USE SIGNAL ;
    SHAPE ABUTMENT ;
    PORT
      LAYER M3 ;
      RECT 27.927 43.346 27.945 43.400 ;
    END
  END rw0_rd_out[311]
  PIN rw0_rd_out[312]
    DIRECTION OUTPUT ;
    USE SIGNAL ;
    SHAPE ABUTMENT ;
    PORT
      LAYER M3 ;
      RECT 28.431 43.346 28.449 43.400 ;
    END
  END rw0_rd_out[312]
  PIN rw0_rd_out[313]
    DIRECTION OUTPUT ;
    USE SIGNAL ;
    SHAPE ABUTMENT ;
    PORT
      LAYER M3 ;
      RECT 28.935 43.346 28.953 43.400 ;
    END
  END rw0_rd_out[313]
  PIN rw0_rd_out[314]
    DIRECTION OUTPUT ;
    USE SIGNAL ;
    SHAPE ABUTMENT ;
    PORT
      LAYER M3 ;
      RECT 29.439 43.346 29.457 43.400 ;
    END
  END rw0_rd_out[314]
  PIN rw0_rd_out[315]
    DIRECTION OUTPUT ;
    USE SIGNAL ;
    SHAPE ABUTMENT ;
    PORT
      LAYER M3 ;
      RECT 29.943 43.346 29.961 43.400 ;
    END
  END rw0_rd_out[315]
  PIN rw0_rd_out[316]
    DIRECTION OUTPUT ;
    USE SIGNAL ;
    SHAPE ABUTMENT ;
    PORT
      LAYER M3 ;
      RECT 30.447 43.346 30.465 43.400 ;
    END
  END rw0_rd_out[316]
  PIN rw0_rd_out[317]
    DIRECTION OUTPUT ;
    USE SIGNAL ;
    SHAPE ABUTMENT ;
    PORT
      LAYER M3 ;
      RECT 30.951 43.346 30.969 43.400 ;
    END
  END rw0_rd_out[317]
  PIN rw0_rd_out[318]
    DIRECTION OUTPUT ;
    USE SIGNAL ;
    SHAPE ABUTMENT ;
    PORT
      LAYER M3 ;
      RECT 31.455 43.346 31.473 43.400 ;
    END
  END rw0_rd_out[318]
  PIN rw0_rd_out[319]
    DIRECTION OUTPUT ;
    USE SIGNAL ;
    SHAPE ABUTMENT ;
    PORT
      LAYER M3 ;
      RECT 31.959 43.346 31.977 43.400 ;
    END
  END rw0_rd_out[319]
  PIN rw0_rd_out[320]
    DIRECTION OUTPUT ;
    USE SIGNAL ;
    SHAPE ABUTMENT ;
    PORT
      LAYER M3 ;
      RECT 32.463 43.346 32.481 43.400 ;
    END
  END rw0_rd_out[320]
  PIN rw0_rd_out[321]
    DIRECTION OUTPUT ;
    USE SIGNAL ;
    SHAPE ABUTMENT ;
    PORT
      LAYER M3 ;
      RECT 32.967 43.346 32.985 43.400 ;
    END
  END rw0_rd_out[321]
  PIN rw0_rd_out[322]
    DIRECTION OUTPUT ;
    USE SIGNAL ;
    SHAPE ABUTMENT ;
    PORT
      LAYER M3 ;
      RECT 33.471 43.346 33.489 43.400 ;
    END
  END rw0_rd_out[322]
  PIN rw0_rd_out[323]
    DIRECTION OUTPUT ;
    USE SIGNAL ;
    SHAPE ABUTMENT ;
    PORT
      LAYER M3 ;
      RECT 33.975 43.346 33.993 43.400 ;
    END
  END rw0_rd_out[323]
  PIN rw0_rd_out[324]
    DIRECTION OUTPUT ;
    USE SIGNAL ;
    SHAPE ABUTMENT ;
    PORT
      LAYER M3 ;
      RECT 34.479 43.346 34.497 43.400 ;
    END
  END rw0_rd_out[324]
  PIN rw0_rd_out[325]
    DIRECTION OUTPUT ;
    USE SIGNAL ;
    SHAPE ABUTMENT ;
    PORT
      LAYER M3 ;
      RECT 34.983 43.346 35.001 43.400 ;
    END
  END rw0_rd_out[325]
  PIN rw0_rd_out[326]
    DIRECTION OUTPUT ;
    USE SIGNAL ;
    SHAPE ABUTMENT ;
    PORT
      LAYER M3 ;
      RECT 35.487 43.346 35.505 43.400 ;
    END
  END rw0_rd_out[326]
  PIN rw0_rd_out[327]
    DIRECTION OUTPUT ;
    USE SIGNAL ;
    SHAPE ABUTMENT ;
    PORT
      LAYER M3 ;
      RECT 35.991 43.346 36.009 43.400 ;
    END
  END rw0_rd_out[327]
  PIN rw0_rd_out[328]
    DIRECTION OUTPUT ;
    USE SIGNAL ;
    SHAPE ABUTMENT ;
    PORT
      LAYER M3 ;
      RECT 36.495 43.346 36.513 43.400 ;
    END
  END rw0_rd_out[328]
  PIN rw0_rd_out[329]
    DIRECTION OUTPUT ;
    USE SIGNAL ;
    SHAPE ABUTMENT ;
    PORT
      LAYER M3 ;
      RECT 36.999 43.346 37.017 43.400 ;
    END
  END rw0_rd_out[329]
  PIN rw0_rd_out[330]
    DIRECTION OUTPUT ;
    USE SIGNAL ;
    SHAPE ABUTMENT ;
    PORT
      LAYER M3 ;
      RECT 37.503 43.346 37.521 43.400 ;
    END
  END rw0_rd_out[330]
  PIN rw0_rd_out[331]
    DIRECTION OUTPUT ;
    USE SIGNAL ;
    SHAPE ABUTMENT ;
    PORT
      LAYER M3 ;
      RECT 38.007 43.346 38.025 43.400 ;
    END
  END rw0_rd_out[331]
  PIN rw0_rd_out[332]
    DIRECTION OUTPUT ;
    USE SIGNAL ;
    SHAPE ABUTMENT ;
    PORT
      LAYER M3 ;
      RECT 38.511 43.346 38.529 43.400 ;
    END
  END rw0_rd_out[332]
  PIN rw0_rd_out[333]
    DIRECTION OUTPUT ;
    USE SIGNAL ;
    SHAPE ABUTMENT ;
    PORT
      LAYER M3 ;
      RECT 39.015 43.346 39.033 43.400 ;
    END
  END rw0_rd_out[333]
  PIN rw0_rd_out[334]
    DIRECTION OUTPUT ;
    USE SIGNAL ;
    SHAPE ABUTMENT ;
    PORT
      LAYER M3 ;
      RECT 39.519 43.346 39.537 43.400 ;
    END
  END rw0_rd_out[334]
  PIN rw0_rd_out[335]
    DIRECTION OUTPUT ;
    USE SIGNAL ;
    SHAPE ABUTMENT ;
    PORT
      LAYER M3 ;
      RECT 40.023 43.346 40.041 43.400 ;
    END
  END rw0_rd_out[335]
  PIN rw0_rd_out[336]
    DIRECTION OUTPUT ;
    USE SIGNAL ;
    SHAPE ABUTMENT ;
    PORT
      LAYER M3 ;
      RECT 40.527 43.346 40.545 43.400 ;
    END
  END rw0_rd_out[336]
  PIN rw0_rd_out[337]
    DIRECTION OUTPUT ;
    USE SIGNAL ;
    SHAPE ABUTMENT ;
    PORT
      LAYER M3 ;
      RECT 41.031 43.346 41.049 43.400 ;
    END
  END rw0_rd_out[337]
  PIN rw0_rd_out[338]
    DIRECTION OUTPUT ;
    USE SIGNAL ;
    SHAPE ABUTMENT ;
    PORT
      LAYER M3 ;
      RECT 41.535 43.346 41.553 43.400 ;
    END
  END rw0_rd_out[338]
  PIN rw0_rd_out[339]
    DIRECTION OUTPUT ;
    USE SIGNAL ;
    SHAPE ABUTMENT ;
    PORT
      LAYER M3 ;
      RECT 42.039 43.346 42.057 43.400 ;
    END
  END rw0_rd_out[339]
  PIN rw0_rd_out[340]
    DIRECTION OUTPUT ;
    USE SIGNAL ;
    SHAPE ABUTMENT ;
    PORT
      LAYER M3 ;
      RECT 42.543 43.346 42.561 43.400 ;
    END
  END rw0_rd_out[340]
  PIN rw0_rd_out[341]
    DIRECTION OUTPUT ;
    USE SIGNAL ;
    SHAPE ABUTMENT ;
    PORT
      LAYER M3 ;
      RECT 43.047 43.346 43.065 43.400 ;
    END
  END rw0_rd_out[341]
  PIN rw0_rd_out[342]
    DIRECTION OUTPUT ;
    USE SIGNAL ;
    SHAPE ABUTMENT ;
    PORT
      LAYER M3 ;
      RECT 43.551 43.346 43.569 43.400 ;
    END
  END rw0_rd_out[342]
  PIN rw0_rd_out[343]
    DIRECTION OUTPUT ;
    USE SIGNAL ;
    SHAPE ABUTMENT ;
    PORT
      LAYER M3 ;
      RECT 44.055 43.346 44.073 43.400 ;
    END
  END rw0_rd_out[343]
  PIN rw0_rd_out[344]
    DIRECTION OUTPUT ;
    USE SIGNAL ;
    SHAPE ABUTMENT ;
    PORT
      LAYER M3 ;
      RECT 44.559 43.346 44.577 43.400 ;
    END
  END rw0_rd_out[344]
  PIN rw0_rd_out[345]
    DIRECTION OUTPUT ;
    USE SIGNAL ;
    SHAPE ABUTMENT ;
    PORT
      LAYER M3 ;
      RECT 45.063 43.346 45.081 43.400 ;
    END
  END rw0_rd_out[345]
  PIN rw0_rd_out[346]
    DIRECTION OUTPUT ;
    USE SIGNAL ;
    SHAPE ABUTMENT ;
    PORT
      LAYER M3 ;
      RECT 45.567 43.346 45.585 43.400 ;
    END
  END rw0_rd_out[346]
  PIN rw0_rd_out[347]
    DIRECTION OUTPUT ;
    USE SIGNAL ;
    SHAPE ABUTMENT ;
    PORT
      LAYER M3 ;
      RECT 46.071 43.346 46.089 43.400 ;
    END
  END rw0_rd_out[347]
  PIN rw0_rd_out[348]
    DIRECTION OUTPUT ;
    USE SIGNAL ;
    SHAPE ABUTMENT ;
    PORT
      LAYER M3 ;
      RECT 46.575 43.346 46.593 43.400 ;
    END
  END rw0_rd_out[348]
  PIN rw0_rd_out[349]
    DIRECTION OUTPUT ;
    USE SIGNAL ;
    SHAPE ABUTMENT ;
    PORT
      LAYER M3 ;
      RECT 47.079 43.346 47.097 43.400 ;
    END
  END rw0_rd_out[349]
  PIN rw0_rd_out[350]
    DIRECTION OUTPUT ;
    USE SIGNAL ;
    SHAPE ABUTMENT ;
    PORT
      LAYER M3 ;
      RECT 47.583 43.346 47.601 43.400 ;
    END
  END rw0_rd_out[350]
  PIN rw0_rd_out[351]
    DIRECTION OUTPUT ;
    USE SIGNAL ;
    SHAPE ABUTMENT ;
    PORT
      LAYER M3 ;
      RECT 48.087 43.346 48.105 43.400 ;
    END
  END rw0_rd_out[351]
  PIN rw0_rd_out[352]
    DIRECTION OUTPUT ;
    USE SIGNAL ;
    SHAPE ABUTMENT ;
    PORT
      LAYER M3 ;
      RECT 48.591 43.346 48.609 43.400 ;
    END
  END rw0_rd_out[352]
  PIN rw0_rd_out[353]
    DIRECTION OUTPUT ;
    USE SIGNAL ;
    SHAPE ABUTMENT ;
    PORT
      LAYER M3 ;
      RECT 49.095 43.346 49.113 43.400 ;
    END
  END rw0_rd_out[353]
  PIN rw0_rd_out[354]
    DIRECTION OUTPUT ;
    USE SIGNAL ;
    SHAPE ABUTMENT ;
    PORT
      LAYER M3 ;
      RECT 49.599 43.346 49.617 43.400 ;
    END
  END rw0_rd_out[354]
  PIN rw0_rd_out[355]
    DIRECTION OUTPUT ;
    USE SIGNAL ;
    SHAPE ABUTMENT ;
    PORT
      LAYER M3 ;
      RECT 50.103 43.346 50.121 43.400 ;
    END
  END rw0_rd_out[355]
  PIN rw0_rd_out[356]
    DIRECTION OUTPUT ;
    USE SIGNAL ;
    SHAPE ABUTMENT ;
    PORT
      LAYER M3 ;
      RECT 50.607 43.346 50.625 43.400 ;
    END
  END rw0_rd_out[356]
  PIN rw0_rd_out[357]
    DIRECTION OUTPUT ;
    USE SIGNAL ;
    SHAPE ABUTMENT ;
    PORT
      LAYER M3 ;
      RECT 51.111 43.346 51.129 43.400 ;
    END
  END rw0_rd_out[357]
  PIN rw0_rd_out[358]
    DIRECTION OUTPUT ;
    USE SIGNAL ;
    SHAPE ABUTMENT ;
    PORT
      LAYER M3 ;
      RECT 51.615 43.346 51.633 43.400 ;
    END
  END rw0_rd_out[358]
  PIN rw0_rd_out[359]
    DIRECTION OUTPUT ;
    USE SIGNAL ;
    SHAPE ABUTMENT ;
    PORT
      LAYER M3 ;
      RECT 52.119 43.346 52.137 43.400 ;
    END
  END rw0_rd_out[359]
  PIN rw0_rd_out[360]
    DIRECTION OUTPUT ;
    USE SIGNAL ;
    SHAPE ABUTMENT ;
    PORT
      LAYER M3 ;
      RECT 52.623 43.346 52.641 43.400 ;
    END
  END rw0_rd_out[360]
  PIN rw0_rd_out[361]
    DIRECTION OUTPUT ;
    USE SIGNAL ;
    SHAPE ABUTMENT ;
    PORT
      LAYER M3 ;
      RECT 53.127 43.346 53.145 43.400 ;
    END
  END rw0_rd_out[361]
  PIN rw0_rd_out[362]
    DIRECTION OUTPUT ;
    USE SIGNAL ;
    SHAPE ABUTMENT ;
    PORT
      LAYER M3 ;
      RECT 53.631 43.346 53.649 43.400 ;
    END
  END rw0_rd_out[362]
  PIN rw0_rd_out[363]
    DIRECTION OUTPUT ;
    USE SIGNAL ;
    SHAPE ABUTMENT ;
    PORT
      LAYER M3 ;
      RECT 54.135 43.346 54.153 43.400 ;
    END
  END rw0_rd_out[363]
  PIN rw0_rd_out[364]
    DIRECTION OUTPUT ;
    USE SIGNAL ;
    SHAPE ABUTMENT ;
    PORT
      LAYER M3 ;
      RECT 54.639 43.346 54.657 43.400 ;
    END
  END rw0_rd_out[364]
  PIN rw0_rd_out[365]
    DIRECTION OUTPUT ;
    USE SIGNAL ;
    SHAPE ABUTMENT ;
    PORT
      LAYER M3 ;
      RECT 55.143 43.346 55.161 43.400 ;
    END
  END rw0_rd_out[365]
  PIN rw0_rd_out[366]
    DIRECTION OUTPUT ;
    USE SIGNAL ;
    SHAPE ABUTMENT ;
    PORT
      LAYER M3 ;
      RECT 55.647 43.346 55.665 43.400 ;
    END
  END rw0_rd_out[366]
  PIN rw0_rd_out[367]
    DIRECTION OUTPUT ;
    USE SIGNAL ;
    SHAPE ABUTMENT ;
    PORT
      LAYER M3 ;
      RECT 56.151 43.346 56.169 43.400 ;
    END
  END rw0_rd_out[367]
  PIN rw0_rd_out[368]
    DIRECTION OUTPUT ;
    USE SIGNAL ;
    SHAPE ABUTMENT ;
    PORT
      LAYER M3 ;
      RECT 56.655 43.346 56.673 43.400 ;
    END
  END rw0_rd_out[368]
  PIN rw0_rd_out[369]
    DIRECTION OUTPUT ;
    USE SIGNAL ;
    SHAPE ABUTMENT ;
    PORT
      LAYER M3 ;
      RECT 57.159 43.346 57.177 43.400 ;
    END
  END rw0_rd_out[369]
  PIN rw0_rd_out[370]
    DIRECTION OUTPUT ;
    USE SIGNAL ;
    SHAPE ABUTMENT ;
    PORT
      LAYER M3 ;
      RECT 57.663 43.346 57.681 43.400 ;
    END
  END rw0_rd_out[370]
  PIN rw0_rd_out[371]
    DIRECTION OUTPUT ;
    USE SIGNAL ;
    SHAPE ABUTMENT ;
    PORT
      LAYER M3 ;
      RECT 58.167 43.346 58.185 43.400 ;
    END
  END rw0_rd_out[371]
  PIN rw0_rd_out[372]
    DIRECTION OUTPUT ;
    USE SIGNAL ;
    SHAPE ABUTMENT ;
    PORT
      LAYER M3 ;
      RECT 58.671 43.346 58.689 43.400 ;
    END
  END rw0_rd_out[372]
  PIN rw0_rd_out[373]
    DIRECTION OUTPUT ;
    USE SIGNAL ;
    SHAPE ABUTMENT ;
    PORT
      LAYER M3 ;
      RECT 59.175 43.346 59.193 43.400 ;
    END
  END rw0_rd_out[373]
  PIN rw0_rd_out[374]
    DIRECTION OUTPUT ;
    USE SIGNAL ;
    SHAPE ABUTMENT ;
    PORT
      LAYER M3 ;
      RECT 59.679 43.346 59.697 43.400 ;
    END
  END rw0_rd_out[374]
  PIN rw0_rd_out[375]
    DIRECTION OUTPUT ;
    USE SIGNAL ;
    SHAPE ABUTMENT ;
    PORT
      LAYER M3 ;
      RECT 60.183 43.346 60.201 43.400 ;
    END
  END rw0_rd_out[375]
  PIN rw0_rd_out[376]
    DIRECTION OUTPUT ;
    USE SIGNAL ;
    SHAPE ABUTMENT ;
    PORT
      LAYER M3 ;
      RECT 60.687 43.346 60.705 43.400 ;
    END
  END rw0_rd_out[376]
  PIN rw0_rd_out[377]
    DIRECTION OUTPUT ;
    USE SIGNAL ;
    SHAPE ABUTMENT ;
    PORT
      LAYER M3 ;
      RECT 61.191 43.346 61.209 43.400 ;
    END
  END rw0_rd_out[377]
  PIN rw0_rd_out[378]
    DIRECTION OUTPUT ;
    USE SIGNAL ;
    SHAPE ABUTMENT ;
    PORT
      LAYER M3 ;
      RECT 61.695 43.346 61.713 43.400 ;
    END
  END rw0_rd_out[378]
  PIN rw0_rd_out[379]
    DIRECTION OUTPUT ;
    USE SIGNAL ;
    SHAPE ABUTMENT ;
    PORT
      LAYER M3 ;
      RECT 62.199 43.346 62.217 43.400 ;
    END
  END rw0_rd_out[379]
  PIN rw0_rd_out[380]
    DIRECTION OUTPUT ;
    USE SIGNAL ;
    SHAPE ABUTMENT ;
    PORT
      LAYER M3 ;
      RECT 62.703 43.346 62.721 43.400 ;
    END
  END rw0_rd_out[380]
  PIN rw0_rd_out[381]
    DIRECTION OUTPUT ;
    USE SIGNAL ;
    SHAPE ABUTMENT ;
    PORT
      LAYER M3 ;
      RECT 63.207 43.346 63.225 43.400 ;
    END
  END rw0_rd_out[381]
  PIN rw0_rd_out[382]
    DIRECTION OUTPUT ;
    USE SIGNAL ;
    SHAPE ABUTMENT ;
    PORT
      LAYER M3 ;
      RECT 63.711 43.346 63.729 43.400 ;
    END
  END rw0_rd_out[382]
  PIN rw0_rd_out[383]
    DIRECTION OUTPUT ;
    USE SIGNAL ;
    SHAPE ABUTMENT ;
    PORT
      LAYER M3 ;
      RECT 64.215 43.346 64.233 43.400 ;
    END
  END rw0_rd_out[383]
  PIN rw0_rd_out[384]
    DIRECTION OUTPUT ;
    USE SIGNAL ;
    SHAPE ABUTMENT ;
    PORT
      LAYER M3 ;
      RECT 64.719 43.346 64.737 43.400 ;
    END
  END rw0_rd_out[384]
  PIN rw0_rd_out[385]
    DIRECTION OUTPUT ;
    USE SIGNAL ;
    SHAPE ABUTMENT ;
    PORT
      LAYER M3 ;
      RECT 65.223 43.346 65.241 43.400 ;
    END
  END rw0_rd_out[385]
  PIN rw0_rd_out[386]
    DIRECTION OUTPUT ;
    USE SIGNAL ;
    SHAPE ABUTMENT ;
    PORT
      LAYER M3 ;
      RECT 65.727 43.346 65.745 43.400 ;
    END
  END rw0_rd_out[386]
  PIN rw0_rd_out[387]
    DIRECTION OUTPUT ;
    USE SIGNAL ;
    SHAPE ABUTMENT ;
    PORT
      LAYER M3 ;
      RECT 66.231 43.346 66.249 43.400 ;
    END
  END rw0_rd_out[387]
  PIN rw0_rd_out[388]
    DIRECTION OUTPUT ;
    USE SIGNAL ;
    SHAPE ABUTMENT ;
    PORT
      LAYER M3 ;
      RECT 66.735 43.346 66.753 43.400 ;
    END
  END rw0_rd_out[388]
  PIN rw0_rd_out[389]
    DIRECTION OUTPUT ;
    USE SIGNAL ;
    SHAPE ABUTMENT ;
    PORT
      LAYER M3 ;
      RECT 67.239 43.346 67.257 43.400 ;
    END
  END rw0_rd_out[389]
  PIN rw0_rd_out[390]
    DIRECTION OUTPUT ;
    USE SIGNAL ;
    SHAPE ABUTMENT ;
    PORT
      LAYER M3 ;
      RECT 67.743 43.346 67.761 43.400 ;
    END
  END rw0_rd_out[390]
  PIN rw0_rd_out[391]
    DIRECTION OUTPUT ;
    USE SIGNAL ;
    SHAPE ABUTMENT ;
    PORT
      LAYER M3 ;
      RECT 68.247 43.346 68.265 43.400 ;
    END
  END rw0_rd_out[391]
  PIN rw0_rd_out[392]
    DIRECTION OUTPUT ;
    USE SIGNAL ;
    SHAPE ABUTMENT ;
    PORT
      LAYER M3 ;
      RECT 68.751 43.346 68.769 43.400 ;
    END
  END rw0_rd_out[392]
  PIN rw0_rd_out[393]
    DIRECTION OUTPUT ;
    USE SIGNAL ;
    SHAPE ABUTMENT ;
    PORT
      LAYER M3 ;
      RECT 69.255 43.346 69.273 43.400 ;
    END
  END rw0_rd_out[393]
  PIN rw0_rd_out[394]
    DIRECTION OUTPUT ;
    USE SIGNAL ;
    SHAPE ABUTMENT ;
    PORT
      LAYER M3 ;
      RECT 69.759 43.346 69.777 43.400 ;
    END
  END rw0_rd_out[394]
  PIN rw0_rd_out[395]
    DIRECTION OUTPUT ;
    USE SIGNAL ;
    SHAPE ABUTMENT ;
    PORT
      LAYER M3 ;
      RECT 70.263 43.346 70.281 43.400 ;
    END
  END rw0_rd_out[395]
  PIN rw0_rd_out[396]
    DIRECTION OUTPUT ;
    USE SIGNAL ;
    SHAPE ABUTMENT ;
    PORT
      LAYER M3 ;
      RECT 70.767 43.346 70.785 43.400 ;
    END
  END rw0_rd_out[396]
  PIN rw0_rd_out[397]
    DIRECTION OUTPUT ;
    USE SIGNAL ;
    SHAPE ABUTMENT ;
    PORT
      LAYER M3 ;
      RECT 71.271 43.346 71.289 43.400 ;
    END
  END rw0_rd_out[397]
  PIN rw0_rd_out[398]
    DIRECTION OUTPUT ;
    USE SIGNAL ;
    SHAPE ABUTMENT ;
    PORT
      LAYER M3 ;
      RECT 71.775 43.346 71.793 43.400 ;
    END
  END rw0_rd_out[398]
  PIN rw0_rd_out[399]
    DIRECTION OUTPUT ;
    USE SIGNAL ;
    SHAPE ABUTMENT ;
    PORT
      LAYER M3 ;
      RECT 72.279 43.346 72.297 43.400 ;
    END
  END rw0_rd_out[399]
  PIN rw0_rd_out[400]
    DIRECTION OUTPUT ;
    USE SIGNAL ;
    SHAPE ABUTMENT ;
    PORT
      LAYER M3 ;
      RECT 72.783 43.346 72.801 43.400 ;
    END
  END rw0_rd_out[400]
  PIN rw0_rd_out[401]
    DIRECTION OUTPUT ;
    USE SIGNAL ;
    SHAPE ABUTMENT ;
    PORT
      LAYER M3 ;
      RECT 73.287 43.346 73.305 43.400 ;
    END
  END rw0_rd_out[401]
  PIN rw0_rd_out[402]
    DIRECTION OUTPUT ;
    USE SIGNAL ;
    SHAPE ABUTMENT ;
    PORT
      LAYER M3 ;
      RECT 73.791 43.346 73.809 43.400 ;
    END
  END rw0_rd_out[402]
  PIN rw0_rd_out[403]
    DIRECTION OUTPUT ;
    USE SIGNAL ;
    SHAPE ABUTMENT ;
    PORT
      LAYER M3 ;
      RECT 74.295 43.346 74.313 43.400 ;
    END
  END rw0_rd_out[403]
  PIN rw0_rd_out[404]
    DIRECTION OUTPUT ;
    USE SIGNAL ;
    SHAPE ABUTMENT ;
    PORT
      LAYER M3 ;
      RECT 74.799 43.346 74.817 43.400 ;
    END
  END rw0_rd_out[404]
  PIN rw0_rd_out[405]
    DIRECTION OUTPUT ;
    USE SIGNAL ;
    SHAPE ABUTMENT ;
    PORT
      LAYER M3 ;
      RECT 75.303 43.346 75.321 43.400 ;
    END
  END rw0_rd_out[405]
  PIN rw0_rd_out[406]
    DIRECTION OUTPUT ;
    USE SIGNAL ;
    SHAPE ABUTMENT ;
    PORT
      LAYER M3 ;
      RECT 75.807 43.346 75.825 43.400 ;
    END
  END rw0_rd_out[406]
  PIN rw0_rd_out[407]
    DIRECTION OUTPUT ;
    USE SIGNAL ;
    SHAPE ABUTMENT ;
    PORT
      LAYER M3 ;
      RECT 76.311 43.346 76.329 43.400 ;
    END
  END rw0_rd_out[407]
  PIN rw0_rd_out[408]
    DIRECTION OUTPUT ;
    USE SIGNAL ;
    SHAPE ABUTMENT ;
    PORT
      LAYER M3 ;
      RECT 76.815 43.346 76.833 43.400 ;
    END
  END rw0_rd_out[408]
  PIN rw0_rd_out[409]
    DIRECTION OUTPUT ;
    USE SIGNAL ;
    SHAPE ABUTMENT ;
    PORT
      LAYER M3 ;
      RECT 77.319 43.346 77.337 43.400 ;
    END
  END rw0_rd_out[409]
  PIN rw0_rd_out[410]
    DIRECTION OUTPUT ;
    USE SIGNAL ;
    SHAPE ABUTMENT ;
    PORT
      LAYER M3 ;
      RECT 77.823 43.346 77.841 43.400 ;
    END
  END rw0_rd_out[410]
  PIN rw0_rd_out[411]
    DIRECTION OUTPUT ;
    USE SIGNAL ;
    SHAPE ABUTMENT ;
    PORT
      LAYER M3 ;
      RECT 78.327 43.346 78.345 43.400 ;
    END
  END rw0_rd_out[411]
  PIN rw0_rd_out[412]
    DIRECTION OUTPUT ;
    USE SIGNAL ;
    SHAPE ABUTMENT ;
    PORT
      LAYER M3 ;
      RECT 78.831 43.346 78.849 43.400 ;
    END
  END rw0_rd_out[412]
  PIN rw0_rd_out[413]
    DIRECTION OUTPUT ;
    USE SIGNAL ;
    SHAPE ABUTMENT ;
    PORT
      LAYER M3 ;
      RECT 79.335 43.346 79.353 43.400 ;
    END
  END rw0_rd_out[413]
  PIN rw0_rd_out[414]
    DIRECTION OUTPUT ;
    USE SIGNAL ;
    SHAPE ABUTMENT ;
    PORT
      LAYER M3 ;
      RECT 79.839 43.346 79.857 43.400 ;
    END
  END rw0_rd_out[414]
  PIN rw0_rd_out[415]
    DIRECTION OUTPUT ;
    USE SIGNAL ;
    SHAPE ABUTMENT ;
    PORT
      LAYER M3 ;
      RECT 80.343 43.346 80.361 43.400 ;
    END
  END rw0_rd_out[415]
  PIN rw0_rd_out[416]
    DIRECTION OUTPUT ;
    USE SIGNAL ;
    SHAPE ABUTMENT ;
    PORT
      LAYER M3 ;
      RECT 80.847 43.346 80.865 43.400 ;
    END
  END rw0_rd_out[416]
  PIN rw0_rd_out[417]
    DIRECTION OUTPUT ;
    USE SIGNAL ;
    SHAPE ABUTMENT ;
    PORT
      LAYER M3 ;
      RECT 81.351 43.346 81.369 43.400 ;
    END
  END rw0_rd_out[417]
  PIN rw0_rd_out[418]
    DIRECTION OUTPUT ;
    USE SIGNAL ;
    SHAPE ABUTMENT ;
    PORT
      LAYER M3 ;
      RECT 81.855 43.346 81.873 43.400 ;
    END
  END rw0_rd_out[418]
  PIN rw0_rd_out[419]
    DIRECTION OUTPUT ;
    USE SIGNAL ;
    SHAPE ABUTMENT ;
    PORT
      LAYER M3 ;
      RECT 82.359 43.346 82.377 43.400 ;
    END
  END rw0_rd_out[419]
  PIN rw0_rd_out[420]
    DIRECTION OUTPUT ;
    USE SIGNAL ;
    SHAPE ABUTMENT ;
    PORT
      LAYER M3 ;
      RECT 82.863 43.346 82.881 43.400 ;
    END
  END rw0_rd_out[420]
  PIN rw0_rd_out[421]
    DIRECTION OUTPUT ;
    USE SIGNAL ;
    SHAPE ABUTMENT ;
    PORT
      LAYER M3 ;
      RECT 83.367 43.346 83.385 43.400 ;
    END
  END rw0_rd_out[421]
  PIN rw0_rd_out[422]
    DIRECTION OUTPUT ;
    USE SIGNAL ;
    SHAPE ABUTMENT ;
    PORT
      LAYER M3 ;
      RECT 83.871 43.346 83.889 43.400 ;
    END
  END rw0_rd_out[422]
  PIN rw0_rd_out[423]
    DIRECTION OUTPUT ;
    USE SIGNAL ;
    SHAPE ABUTMENT ;
    PORT
      LAYER M3 ;
      RECT 84.375 43.346 84.393 43.400 ;
    END
  END rw0_rd_out[423]
  PIN rw0_rd_out[424]
    DIRECTION OUTPUT ;
    USE SIGNAL ;
    SHAPE ABUTMENT ;
    PORT
      LAYER M3 ;
      RECT 84.879 43.346 84.897 43.400 ;
    END
  END rw0_rd_out[424]
  PIN rw0_rd_out[425]
    DIRECTION OUTPUT ;
    USE SIGNAL ;
    SHAPE ABUTMENT ;
    PORT
      LAYER M3 ;
      RECT 85.383 43.346 85.401 43.400 ;
    END
  END rw0_rd_out[425]
  PIN rw0_rd_out[426]
    DIRECTION OUTPUT ;
    USE SIGNAL ;
    SHAPE ABUTMENT ;
    PORT
      LAYER M3 ;
      RECT 85.887 43.346 85.905 43.400 ;
    END
  END rw0_rd_out[426]
  PIN rw0_rd_out[427]
    DIRECTION OUTPUT ;
    USE SIGNAL ;
    SHAPE ABUTMENT ;
    PORT
      LAYER M3 ;
      RECT 86.391 43.346 86.409 43.400 ;
    END
  END rw0_rd_out[427]
  PIN rw0_rd_out[428]
    DIRECTION OUTPUT ;
    USE SIGNAL ;
    SHAPE ABUTMENT ;
    PORT
      LAYER M3 ;
      RECT 86.895 43.346 86.913 43.400 ;
    END
  END rw0_rd_out[428]
  PIN rw0_rd_out[429]
    DIRECTION OUTPUT ;
    USE SIGNAL ;
    SHAPE ABUTMENT ;
    PORT
      LAYER M3 ;
      RECT 87.399 43.346 87.417 43.400 ;
    END
  END rw0_rd_out[429]
  PIN rw0_rd_out[430]
    DIRECTION OUTPUT ;
    USE SIGNAL ;
    SHAPE ABUTMENT ;
    PORT
      LAYER M3 ;
      RECT 87.903 43.346 87.921 43.400 ;
    END
  END rw0_rd_out[430]
  PIN rw0_rd_out[431]
    DIRECTION OUTPUT ;
    USE SIGNAL ;
    SHAPE ABUTMENT ;
    PORT
      LAYER M3 ;
      RECT 88.407 43.346 88.425 43.400 ;
    END
  END rw0_rd_out[431]
  PIN rw0_rd_out[432]
    DIRECTION OUTPUT ;
    USE SIGNAL ;
    SHAPE ABUTMENT ;
    PORT
      LAYER M3 ;
      RECT 88.911 43.346 88.929 43.400 ;
    END
  END rw0_rd_out[432]
  PIN rw0_rd_out[433]
    DIRECTION OUTPUT ;
    USE SIGNAL ;
    SHAPE ABUTMENT ;
    PORT
      LAYER M3 ;
      RECT 89.415 43.346 89.433 43.400 ;
    END
  END rw0_rd_out[433]
  PIN rw0_rd_out[434]
    DIRECTION OUTPUT ;
    USE SIGNAL ;
    SHAPE ABUTMENT ;
    PORT
      LAYER M3 ;
      RECT 89.919 43.346 89.937 43.400 ;
    END
  END rw0_rd_out[434]
  PIN rw0_rd_out[435]
    DIRECTION OUTPUT ;
    USE SIGNAL ;
    SHAPE ABUTMENT ;
    PORT
      LAYER M3 ;
      RECT 90.423 43.346 90.441 43.400 ;
    END
  END rw0_rd_out[435]
  PIN rw0_rd_out[436]
    DIRECTION OUTPUT ;
    USE SIGNAL ;
    SHAPE ABUTMENT ;
    PORT
      LAYER M3 ;
      RECT 90.927 43.346 90.945 43.400 ;
    END
  END rw0_rd_out[436]
  PIN rw0_rd_out[437]
    DIRECTION OUTPUT ;
    USE SIGNAL ;
    SHAPE ABUTMENT ;
    PORT
      LAYER M3 ;
      RECT 91.431 43.346 91.449 43.400 ;
    END
  END rw0_rd_out[437]
  PIN rw0_rd_out[438]
    DIRECTION OUTPUT ;
    USE SIGNAL ;
    SHAPE ABUTMENT ;
    PORT
      LAYER M3 ;
      RECT 91.935 43.346 91.953 43.400 ;
    END
  END rw0_rd_out[438]
  PIN rw0_rd_out[439]
    DIRECTION OUTPUT ;
    USE SIGNAL ;
    SHAPE ABUTMENT ;
    PORT
      LAYER M3 ;
      RECT 92.439 43.346 92.457 43.400 ;
    END
  END rw0_rd_out[439]
  PIN rw0_rd_out[440]
    DIRECTION OUTPUT ;
    USE SIGNAL ;
    SHAPE ABUTMENT ;
    PORT
      LAYER M3 ;
      RECT 92.943 43.346 92.961 43.400 ;
    END
  END rw0_rd_out[440]
  PIN rw0_rd_out[441]
    DIRECTION OUTPUT ;
    USE SIGNAL ;
    SHAPE ABUTMENT ;
    PORT
      LAYER M3 ;
      RECT 93.447 43.346 93.465 43.400 ;
    END
  END rw0_rd_out[441]
  PIN rw0_rd_out[442]
    DIRECTION OUTPUT ;
    USE SIGNAL ;
    SHAPE ABUTMENT ;
    PORT
      LAYER M3 ;
      RECT 93.951 43.346 93.969 43.400 ;
    END
  END rw0_rd_out[442]
  PIN rw0_rd_out[443]
    DIRECTION OUTPUT ;
    USE SIGNAL ;
    SHAPE ABUTMENT ;
    PORT
      LAYER M3 ;
      RECT 94.455 43.346 94.473 43.400 ;
    END
  END rw0_rd_out[443]
  PIN rw0_rd_out[444]
    DIRECTION OUTPUT ;
    USE SIGNAL ;
    SHAPE ABUTMENT ;
    PORT
      LAYER M3 ;
      RECT 94.959 43.346 94.977 43.400 ;
    END
  END rw0_rd_out[444]
  PIN rw0_rd_out[445]
    DIRECTION OUTPUT ;
    USE SIGNAL ;
    SHAPE ABUTMENT ;
    PORT
      LAYER M3 ;
      RECT 95.463 43.346 95.481 43.400 ;
    END
  END rw0_rd_out[445]
  PIN rw0_rd_out[446]
    DIRECTION OUTPUT ;
    USE SIGNAL ;
    SHAPE ABUTMENT ;
    PORT
      LAYER M3 ;
      RECT 95.967 43.346 95.985 43.400 ;
    END
  END rw0_rd_out[446]
  PIN rw0_rd_out[447]
    DIRECTION OUTPUT ;
    USE SIGNAL ;
    SHAPE ABUTMENT ;
    PORT
      LAYER M3 ;
      RECT 96.471 43.346 96.489 43.400 ;
    END
  END rw0_rd_out[447]
  PIN rw0_rd_out[448]
    DIRECTION OUTPUT ;
    USE SIGNAL ;
    SHAPE ABUTMENT ;
    PORT
      LAYER M3 ;
      RECT 96.975 43.346 96.993 43.400 ;
    END
  END rw0_rd_out[448]
  PIN rw0_rd_out[449]
    DIRECTION OUTPUT ;
    USE SIGNAL ;
    SHAPE ABUTMENT ;
    PORT
      LAYER M3 ;
      RECT 97.479 43.346 97.497 43.400 ;
    END
  END rw0_rd_out[449]
  PIN rw0_rd_out[450]
    DIRECTION OUTPUT ;
    USE SIGNAL ;
    SHAPE ABUTMENT ;
    PORT
      LAYER M3 ;
      RECT 97.983 43.346 98.001 43.400 ;
    END
  END rw0_rd_out[450]
  PIN rw0_rd_out[451]
    DIRECTION OUTPUT ;
    USE SIGNAL ;
    SHAPE ABUTMENT ;
    PORT
      LAYER M3 ;
      RECT 98.487 43.346 98.505 43.400 ;
    END
  END rw0_rd_out[451]
  PIN rw0_rd_out[452]
    DIRECTION OUTPUT ;
    USE SIGNAL ;
    SHAPE ABUTMENT ;
    PORT
      LAYER M3 ;
      RECT 98.991 43.346 99.009 43.400 ;
    END
  END rw0_rd_out[452]
  PIN rw0_rd_out[453]
    DIRECTION OUTPUT ;
    USE SIGNAL ;
    SHAPE ABUTMENT ;
    PORT
      LAYER M3 ;
      RECT 99.495 43.346 99.513 43.400 ;
    END
  END rw0_rd_out[453]
  PIN rw0_rd_out[454]
    DIRECTION OUTPUT ;
    USE SIGNAL ;
    SHAPE ABUTMENT ;
    PORT
      LAYER M3 ;
      RECT 99.999 43.346 100.017 43.400 ;
    END
  END rw0_rd_out[454]
  PIN rw0_rd_out[455]
    DIRECTION OUTPUT ;
    USE SIGNAL ;
    SHAPE ABUTMENT ;
    PORT
      LAYER M3 ;
      RECT 100.503 43.346 100.521 43.400 ;
    END
  END rw0_rd_out[455]
  PIN rw0_rd_out[456]
    DIRECTION OUTPUT ;
    USE SIGNAL ;
    SHAPE ABUTMENT ;
    PORT
      LAYER M3 ;
      RECT 101.007 43.346 101.025 43.400 ;
    END
  END rw0_rd_out[456]
  PIN rw0_rd_out[457]
    DIRECTION OUTPUT ;
    USE SIGNAL ;
    SHAPE ABUTMENT ;
    PORT
      LAYER M3 ;
      RECT 101.511 43.346 101.529 43.400 ;
    END
  END rw0_rd_out[457]
  PIN rw0_rd_out[458]
    DIRECTION OUTPUT ;
    USE SIGNAL ;
    SHAPE ABUTMENT ;
    PORT
      LAYER M3 ;
      RECT 102.015 43.346 102.033 43.400 ;
    END
  END rw0_rd_out[458]
  PIN rw0_rd_out[459]
    DIRECTION OUTPUT ;
    USE SIGNAL ;
    SHAPE ABUTMENT ;
    PORT
      LAYER M3 ;
      RECT 102.519 43.346 102.537 43.400 ;
    END
  END rw0_rd_out[459]
  PIN rw0_rd_out[460]
    DIRECTION OUTPUT ;
    USE SIGNAL ;
    SHAPE ABUTMENT ;
    PORT
      LAYER M3 ;
      RECT 103.023 43.346 103.041 43.400 ;
    END
  END rw0_rd_out[460]
  PIN rw0_rd_out[461]
    DIRECTION OUTPUT ;
    USE SIGNAL ;
    SHAPE ABUTMENT ;
    PORT
      LAYER M3 ;
      RECT 103.527 43.346 103.545 43.400 ;
    END
  END rw0_rd_out[461]
  PIN rw0_rd_out[462]
    DIRECTION OUTPUT ;
    USE SIGNAL ;
    SHAPE ABUTMENT ;
    PORT
      LAYER M3 ;
      RECT 104.031 43.346 104.049 43.400 ;
    END
  END rw0_rd_out[462]
  PIN rw0_rd_out[463]
    DIRECTION OUTPUT ;
    USE SIGNAL ;
    SHAPE ABUTMENT ;
    PORT
      LAYER M3 ;
      RECT 104.535 43.346 104.553 43.400 ;
    END
  END rw0_rd_out[463]
  PIN rw0_rd_out[464]
    DIRECTION OUTPUT ;
    USE SIGNAL ;
    SHAPE ABUTMENT ;
    PORT
      LAYER M3 ;
      RECT 105.039 43.346 105.057 43.400 ;
    END
  END rw0_rd_out[464]
  PIN rw0_rd_out[465]
    DIRECTION OUTPUT ;
    USE SIGNAL ;
    SHAPE ABUTMENT ;
    PORT
      LAYER M3 ;
      RECT 105.543 43.346 105.561 43.400 ;
    END
  END rw0_rd_out[465]
  PIN rw0_rd_out[466]
    DIRECTION OUTPUT ;
    USE SIGNAL ;
    SHAPE ABUTMENT ;
    PORT
      LAYER M3 ;
      RECT 106.047 43.346 106.065 43.400 ;
    END
  END rw0_rd_out[466]
  PIN rw0_rd_out[467]
    DIRECTION OUTPUT ;
    USE SIGNAL ;
    SHAPE ABUTMENT ;
    PORT
      LAYER M3 ;
      RECT 106.551 43.346 106.569 43.400 ;
    END
  END rw0_rd_out[467]
  PIN rw0_rd_out[468]
    DIRECTION OUTPUT ;
    USE SIGNAL ;
    SHAPE ABUTMENT ;
    PORT
      LAYER M3 ;
      RECT 107.055 43.346 107.073 43.400 ;
    END
  END rw0_rd_out[468]
  PIN rw0_rd_out[469]
    DIRECTION OUTPUT ;
    USE SIGNAL ;
    SHAPE ABUTMENT ;
    PORT
      LAYER M3 ;
      RECT 107.559 43.346 107.577 43.400 ;
    END
  END rw0_rd_out[469]
  PIN rw0_rd_out[470]
    DIRECTION OUTPUT ;
    USE SIGNAL ;
    SHAPE ABUTMENT ;
    PORT
      LAYER M3 ;
      RECT 108.063 43.346 108.081 43.400 ;
    END
  END rw0_rd_out[470]
  PIN rw0_rd_out[471]
    DIRECTION OUTPUT ;
    USE SIGNAL ;
    SHAPE ABUTMENT ;
    PORT
      LAYER M3 ;
      RECT 108.567 43.346 108.585 43.400 ;
    END
  END rw0_rd_out[471]
  PIN rw0_rd_out[472]
    DIRECTION OUTPUT ;
    USE SIGNAL ;
    SHAPE ABUTMENT ;
    PORT
      LAYER M3 ;
      RECT 109.071 43.346 109.089 43.400 ;
    END
  END rw0_rd_out[472]
  PIN rw0_rd_out[473]
    DIRECTION OUTPUT ;
    USE SIGNAL ;
    SHAPE ABUTMENT ;
    PORT
      LAYER M3 ;
      RECT 109.575 43.346 109.593 43.400 ;
    END
  END rw0_rd_out[473]
  PIN rw0_rd_out[474]
    DIRECTION OUTPUT ;
    USE SIGNAL ;
    SHAPE ABUTMENT ;
    PORT
      LAYER M3 ;
      RECT 110.079 43.346 110.097 43.400 ;
    END
  END rw0_rd_out[474]
  PIN rw0_rd_out[475]
    DIRECTION OUTPUT ;
    USE SIGNAL ;
    SHAPE ABUTMENT ;
    PORT
      LAYER M3 ;
      RECT 110.583 43.346 110.601 43.400 ;
    END
  END rw0_rd_out[475]
  PIN rw0_rd_out[476]
    DIRECTION OUTPUT ;
    USE SIGNAL ;
    SHAPE ABUTMENT ;
    PORT
      LAYER M3 ;
      RECT 111.087 43.346 111.105 43.400 ;
    END
  END rw0_rd_out[476]
  PIN rw0_rd_out[477]
    DIRECTION OUTPUT ;
    USE SIGNAL ;
    SHAPE ABUTMENT ;
    PORT
      LAYER M3 ;
      RECT 111.591 43.346 111.609 43.400 ;
    END
  END rw0_rd_out[477]
  PIN rw0_rd_out[478]
    DIRECTION OUTPUT ;
    USE SIGNAL ;
    SHAPE ABUTMENT ;
    PORT
      LAYER M3 ;
      RECT 112.095 43.346 112.113 43.400 ;
    END
  END rw0_rd_out[478]
  PIN rw0_rd_out[479]
    DIRECTION OUTPUT ;
    USE SIGNAL ;
    SHAPE ABUTMENT ;
    PORT
      LAYER M3 ;
      RECT 112.599 43.346 112.617 43.400 ;
    END
  END rw0_rd_out[479]
  PIN rw0_rd_out[480]
    DIRECTION OUTPUT ;
    USE SIGNAL ;
    SHAPE ABUTMENT ;
    PORT
      LAYER M3 ;
      RECT 113.103 43.346 113.121 43.400 ;
    END
  END rw0_rd_out[480]
  PIN rw0_rd_out[481]
    DIRECTION OUTPUT ;
    USE SIGNAL ;
    SHAPE ABUTMENT ;
    PORT
      LAYER M3 ;
      RECT 113.607 43.346 113.625 43.400 ;
    END
  END rw0_rd_out[481]
  PIN rw0_rd_out[482]
    DIRECTION OUTPUT ;
    USE SIGNAL ;
    SHAPE ABUTMENT ;
    PORT
      LAYER M3 ;
      RECT 114.111 43.346 114.129 43.400 ;
    END
  END rw0_rd_out[482]
  PIN rw0_rd_out[483]
    DIRECTION OUTPUT ;
    USE SIGNAL ;
    SHAPE ABUTMENT ;
    PORT
      LAYER M3 ;
      RECT 114.615 43.346 114.633 43.400 ;
    END
  END rw0_rd_out[483]
  PIN rw0_rd_out[484]
    DIRECTION OUTPUT ;
    USE SIGNAL ;
    SHAPE ABUTMENT ;
    PORT
      LAYER M3 ;
      RECT 115.119 43.346 115.137 43.400 ;
    END
  END rw0_rd_out[484]
  PIN rw0_rd_out[485]
    DIRECTION OUTPUT ;
    USE SIGNAL ;
    SHAPE ABUTMENT ;
    PORT
      LAYER M3 ;
      RECT 115.623 43.346 115.641 43.400 ;
    END
  END rw0_rd_out[485]
  PIN rw0_rd_out[486]
    DIRECTION OUTPUT ;
    USE SIGNAL ;
    SHAPE ABUTMENT ;
    PORT
      LAYER M3 ;
      RECT 116.127 43.346 116.145 43.400 ;
    END
  END rw0_rd_out[486]
  PIN rw0_rd_out[487]
    DIRECTION OUTPUT ;
    USE SIGNAL ;
    SHAPE ABUTMENT ;
    PORT
      LAYER M3 ;
      RECT 116.631 43.346 116.649 43.400 ;
    END
  END rw0_rd_out[487]
  PIN rw0_rd_out[488]
    DIRECTION OUTPUT ;
    USE SIGNAL ;
    SHAPE ABUTMENT ;
    PORT
      LAYER M3 ;
      RECT 117.135 43.346 117.153 43.400 ;
    END
  END rw0_rd_out[488]
  PIN rw0_rd_out[489]
    DIRECTION OUTPUT ;
    USE SIGNAL ;
    SHAPE ABUTMENT ;
    PORT
      LAYER M3 ;
      RECT 117.639 43.346 117.657 43.400 ;
    END
  END rw0_rd_out[489]
  PIN rw0_rd_out[490]
    DIRECTION OUTPUT ;
    USE SIGNAL ;
    SHAPE ABUTMENT ;
    PORT
      LAYER M3 ;
      RECT 118.143 43.346 118.161 43.400 ;
    END
  END rw0_rd_out[490]
  PIN rw0_rd_out[491]
    DIRECTION OUTPUT ;
    USE SIGNAL ;
    SHAPE ABUTMENT ;
    PORT
      LAYER M3 ;
      RECT 118.647 43.346 118.665 43.400 ;
    END
  END rw0_rd_out[491]
  PIN rw0_rd_out[492]
    DIRECTION OUTPUT ;
    USE SIGNAL ;
    SHAPE ABUTMENT ;
    PORT
      LAYER M3 ;
      RECT 119.151 43.346 119.169 43.400 ;
    END
  END rw0_rd_out[492]
  PIN rw0_rd_out[493]
    DIRECTION OUTPUT ;
    USE SIGNAL ;
    SHAPE ABUTMENT ;
    PORT
      LAYER M3 ;
      RECT 119.655 43.346 119.673 43.400 ;
    END
  END rw0_rd_out[493]
  PIN rw0_rd_out[494]
    DIRECTION OUTPUT ;
    USE SIGNAL ;
    SHAPE ABUTMENT ;
    PORT
      LAYER M3 ;
      RECT 120.159 43.346 120.177 43.400 ;
    END
  END rw0_rd_out[494]
  PIN rw0_rd_out[495]
    DIRECTION OUTPUT ;
    USE SIGNAL ;
    SHAPE ABUTMENT ;
    PORT
      LAYER M3 ;
      RECT 120.663 43.346 120.681 43.400 ;
    END
  END rw0_rd_out[495]
  PIN rw0_rd_out[496]
    DIRECTION OUTPUT ;
    USE SIGNAL ;
    SHAPE ABUTMENT ;
    PORT
      LAYER M3 ;
      RECT 121.167 43.346 121.185 43.400 ;
    END
  END rw0_rd_out[496]
  PIN rw0_rd_out[497]
    DIRECTION OUTPUT ;
    USE SIGNAL ;
    SHAPE ABUTMENT ;
    PORT
      LAYER M3 ;
      RECT 121.671 43.346 121.689 43.400 ;
    END
  END rw0_rd_out[497]
  PIN rw0_rd_out[498]
    DIRECTION OUTPUT ;
    USE SIGNAL ;
    SHAPE ABUTMENT ;
    PORT
      LAYER M3 ;
      RECT 122.175 43.346 122.193 43.400 ;
    END
  END rw0_rd_out[498]
  PIN rw0_rd_out[499]
    DIRECTION OUTPUT ;
    USE SIGNAL ;
    SHAPE ABUTMENT ;
    PORT
      LAYER M3 ;
      RECT 122.679 43.346 122.697 43.400 ;
    END
  END rw0_rd_out[499]
  PIN rw0_rd_out[500]
    DIRECTION OUTPUT ;
    USE SIGNAL ;
    SHAPE ABUTMENT ;
    PORT
      LAYER M3 ;
      RECT 123.183 43.346 123.201 43.400 ;
    END
  END rw0_rd_out[500]
  PIN rw0_rd_out[501]
    DIRECTION OUTPUT ;
    USE SIGNAL ;
    SHAPE ABUTMENT ;
    PORT
      LAYER M3 ;
      RECT 123.687 43.346 123.705 43.400 ;
    END
  END rw0_rd_out[501]
  PIN rw0_rd_out[502]
    DIRECTION OUTPUT ;
    USE SIGNAL ;
    SHAPE ABUTMENT ;
    PORT
      LAYER M3 ;
      RECT 124.191 43.346 124.209 43.400 ;
    END
  END rw0_rd_out[502]
  PIN rw0_rd_out[503]
    DIRECTION OUTPUT ;
    USE SIGNAL ;
    SHAPE ABUTMENT ;
    PORT
      LAYER M3 ;
      RECT 124.695 43.346 124.713 43.400 ;
    END
  END rw0_rd_out[503]
  PIN rw0_rd_out[504]
    DIRECTION OUTPUT ;
    USE SIGNAL ;
    SHAPE ABUTMENT ;
    PORT
      LAYER M3 ;
      RECT 125.199 43.346 125.217 43.400 ;
    END
  END rw0_rd_out[504]
  PIN rw0_rd_out[505]
    DIRECTION OUTPUT ;
    USE SIGNAL ;
    SHAPE ABUTMENT ;
    PORT
      LAYER M3 ;
      RECT 125.703 43.346 125.721 43.400 ;
    END
  END rw0_rd_out[505]
  PIN rw0_rd_out[506]
    DIRECTION OUTPUT ;
    USE SIGNAL ;
    SHAPE ABUTMENT ;
    PORT
      LAYER M3 ;
      RECT 126.207 43.346 126.225 43.400 ;
    END
  END rw0_rd_out[506]
  PIN rw0_rd_out[507]
    DIRECTION OUTPUT ;
    USE SIGNAL ;
    SHAPE ABUTMENT ;
    PORT
      LAYER M3 ;
      RECT 126.711 43.346 126.729 43.400 ;
    END
  END rw0_rd_out[507]
  PIN rw0_rd_out[508]
    DIRECTION OUTPUT ;
    USE SIGNAL ;
    SHAPE ABUTMENT ;
    PORT
      LAYER M3 ;
      RECT 127.215 43.346 127.233 43.400 ;
    END
  END rw0_rd_out[508]
  PIN rw0_rd_out[509]
    DIRECTION OUTPUT ;
    USE SIGNAL ;
    SHAPE ABUTMENT ;
    PORT
      LAYER M3 ;
      RECT 127.719 43.346 127.737 43.400 ;
    END
  END rw0_rd_out[509]
  PIN rw0_rd_out[510]
    DIRECTION OUTPUT ;
    USE SIGNAL ;
    SHAPE ABUTMENT ;
    PORT
      LAYER M3 ;
      RECT 128.223 43.346 128.241 43.400 ;
    END
  END rw0_rd_out[510]
  PIN rw0_rd_out[511]
    DIRECTION OUTPUT ;
    USE SIGNAL ;
    SHAPE ABUTMENT ;
    PORT
      LAYER M3 ;
      RECT 128.727 43.346 128.745 43.400 ;
    END
  END rw0_rd_out[511]
  PIN rw0_addr_in[0]
    DIRECTION INPUT ;
    USE SIGNAL ;
    SHAPE ABUTMENT ;
    PORT
      LAYER M4 ;
      RECT 0.000 37.140 0.072 37.164 ;
    END
  END rw0_addr_in[0]
  PIN rw0_addr_in[1]
    DIRECTION INPUT ;
    USE SIGNAL ;
    SHAPE ABUTMENT ;
    PORT
      LAYER M4 ;
      RECT 0.000 37.428 0.072 37.452 ;
    END
  END rw0_addr_in[1]
  PIN rw0_addr_in[2]
    DIRECTION INPUT ;
    USE SIGNAL ;
    SHAPE ABUTMENT ;
    PORT
      LAYER M4 ;
      RECT 0.000 37.716 0.072 37.740 ;
    END
  END rw0_addr_in[2]
  PIN rw0_addr_in[3]
    DIRECTION INPUT ;
    USE SIGNAL ;
    SHAPE ABUTMENT ;
    PORT
      LAYER M4 ;
      RECT 138.248 37.140 138.320 37.164 ;
    END
  END rw0_addr_in[3]
  PIN rw0_addr_in[4]
    DIRECTION INPUT ;
    USE SIGNAL ;
    SHAPE ABUTMENT ;
    PORT
      LAYER M4 ;
      RECT 138.248 37.428 138.320 37.452 ;
    END
  END rw0_addr_in[4]
  PIN rw0_addr_in[5]
    DIRECTION INPUT ;
    USE SIGNAL ;
    SHAPE ABUTMENT ;
    PORT
      LAYER M4 ;
      RECT 138.248 37.716 138.320 37.740 ;
    END
  END rw0_addr_in[5]
  PIN rw0_we_in
    DIRECTION INPUT ;
    USE SIGNAL ;
    SHAPE ABUTMENT ;
    PORT
      LAYER M3 ;
      RECT 129.231 43.346 129.249 43.400 ;
    END
  END rw0_we_in
  PIN rw0_ce_in
    DIRECTION INPUT ;
    USE SIGNAL ;
    SHAPE ABUTMENT ;
    PORT
      LAYER M3 ;
      RECT 129.735 43.346 129.753 43.400 ;
    END
  END rw0_ce_in
  PIN rw0_clk
    DIRECTION INPUT ;
    USE SIGNAL ;
    SHAPE ABUTMENT ;
    PORT
      LAYER M3 ;
      RECT 130.239 43.346 130.257 43.400 ;
    END
  END rw0_clk
  PIN VSS
    DIRECTION INOUT ;
    USE GROUND ;
    PORT
      LAYER M4 ;
      RECT 0.216 0.240 138.104 0.336 ;
      RECT 0.216 1.008 138.104 1.104 ;
      RECT 0.216 1.776 138.104 1.872 ;
      RECT 0.216 2.544 138.104 2.640 ;
      RECT 0.216 3.312 138.104 3.408 ;
      RECT 0.216 4.080 138.104 4.176 ;
      RECT 0.216 4.848 138.104 4.944 ;
      RECT 0.216 5.616 138.104 5.712 ;
      RECT 0.216 6.384 138.104 6.480 ;
      RECT 0.216 7.152 138.104 7.248 ;
      RECT 0.216 7.920 138.104 8.016 ;
      RECT 0.216 8.688 138.104 8.784 ;
      RECT 0.216 9.456 138.104 9.552 ;
      RECT 0.216 10.224 138.104 10.320 ;
      RECT 0.216 10.992 138.104 11.088 ;
      RECT 0.216 11.760 138.104 11.856 ;
      RECT 0.216 12.528 138.104 12.624 ;
      RECT 0.216 13.296 138.104 13.392 ;
      RECT 0.216 14.064 138.104 14.160 ;
      RECT 0.216 14.832 138.104 14.928 ;
      RECT 0.216 15.600 138.104 15.696 ;
      RECT 0.216 16.368 138.104 16.464 ;
      RECT 0.216 17.136 138.104 17.232 ;
      RECT 0.216 17.904 138.104 18.000 ;
      RECT 0.216 18.672 138.104 18.768 ;
      RECT 0.216 19.440 138.104 19.536 ;
      RECT 0.216 20.208 138.104 20.304 ;
      RECT 0.216 20.976 138.104 21.072 ;
      RECT 0.216 21.744 138.104 21.840 ;
      RECT 0.216 22.512 138.104 22.608 ;
      RECT 0.216 23.280 138.104 23.376 ;
      RECT 0.216 24.048 138.104 24.144 ;
      RECT 0.216 24.816 138.104 24.912 ;
      RECT 0.216 25.584 138.104 25.680 ;
      RECT 0.216 26.352 138.104 26.448 ;
      RECT 0.216 27.120 138.104 27.216 ;
      RECT 0.216 27.888 138.104 27.984 ;
      RECT 0.216 28.656 138.104 28.752 ;
      RECT 0.216 29.424 138.104 29.520 ;
      RECT 0.216 30.192 138.104 30.288 ;
      RECT 0.216 30.960 138.104 31.056 ;
      RECT 0.216 31.728 138.104 31.824 ;
      RECT 0.216 32.496 138.104 32.592 ;
      RECT 0.216 33.264 138.104 33.360 ;
      RECT 0.216 34.032 138.104 34.128 ;
      RECT 0.216 34.800 138.104 34.896 ;
      RECT 0.216 35.568 138.104 35.664 ;
      RECT 0.216 36.336 138.104 36.432 ;
      RECT 0.216 37.104 138.104 37.200 ;
      RECT 0.216 37.872 138.104 37.968 ;
      RECT 0.216 38.640 138.104 38.736 ;
      RECT 0.216 39.408 138.104 39.504 ;
      RECT 0.216 40.176 138.104 40.272 ;
      RECT 0.216 40.944 138.104 41.040 ;
      RECT 0.216 41.712 138.104 41.808 ;
      RECT 0.216 42.480 138.104 42.576 ;
      RECT 0.216 43.248 138.104 43.344 ;
    END
  END VSS
  PIN VDD
    DIRECTION INOUT ;
    USE POWER ;
    PORT
      LAYER M4 ;
      RECT 0.216 0.624 138.104 0.720 ;
      RECT 0.216 1.392 138.104 1.488 ;
      RECT 0.216 2.160 138.104 2.256 ;
      RECT 0.216 2.928 138.104 3.024 ;
      RECT 0.216 3.696 138.104 3.792 ;
      RECT 0.216 4.464 138.104 4.560 ;
      RECT 0.216 5.232 138.104 5.328 ;
      RECT 0.216 6.000 138.104 6.096 ;
      RECT 0.216 6.768 138.104 6.864 ;
      RECT 0.216 7.536 138.104 7.632 ;
      RECT 0.216 8.304 138.104 8.400 ;
      RECT 0.216 9.072 138.104 9.168 ;
      RECT 0.216 9.840 138.104 9.936 ;
      RECT 0.216 10.608 138.104 10.704 ;
      RECT 0.216 11.376 138.104 11.472 ;
      RECT 0.216 12.144 138.104 12.240 ;
      RECT 0.216 12.912 138.104 13.008 ;
      RECT 0.216 13.680 138.104 13.776 ;
      RECT 0.216 14.448 138.104 14.544 ;
      RECT 0.216 15.216 138.104 15.312 ;
      RECT 0.216 15.984 138.104 16.080 ;
      RECT 0.216 16.752 138.104 16.848 ;
      RECT 0.216 17.520 138.104 17.616 ;
      RECT 0.216 18.288 138.104 18.384 ;
      RECT 0.216 19.056 138.104 19.152 ;
      RECT 0.216 19.824 138.104 19.920 ;
      RECT 0.216 20.592 138.104 20.688 ;
      RECT 0.216 21.360 138.104 21.456 ;
      RECT 0.216 22.128 138.104 22.224 ;
      RECT 0.216 22.896 138.104 22.992 ;
      RECT 0.216 23.664 138.104 23.760 ;
      RECT 0.216 24.432 138.104 24.528 ;
      RECT 0.216 25.200 138.104 25.296 ;
      RECT 0.216 25.968 138.104 26.064 ;
      RECT 0.216 26.736 138.104 26.832 ;
      RECT 0.216 27.504 138.104 27.600 ;
      RECT 0.216 28.272 138.104 28.368 ;
      RECT 0.216 29.040 138.104 29.136 ;
      RECT 0.216 29.808 138.104 29.904 ;
      RECT 0.216 30.576 138.104 30.672 ;
      RECT 0.216 31.344 138.104 31.440 ;
      RECT 0.216 32.112 138.104 32.208 ;
      RECT 0.216 32.880 138.104 32.976 ;
      RECT 0.216 33.648 138.104 33.744 ;
      RECT 0.216 34.416 138.104 34.512 ;
      RECT 0.216 35.184 138.104 35.280 ;
      RECT 0.216 35.952 138.104 36.048 ;
      RECT 0.216 36.720 138.104 36.816 ;
      RECT 0.216 37.488 138.104 37.584 ;
      RECT 0.216 38.256 138.104 38.352 ;
      RECT 0.216 39.024 138.104 39.120 ;
      RECT 0.216 39.792 138.104 39.888 ;
      RECT 0.216 40.560 138.104 40.656 ;
      RECT 0.216 41.328 138.104 41.424 ;
      RECT 0.216 42.096 138.104 42.192 ;
      RECT 0.216 42.864 138.104 42.960 ;
    END
  END VDD
  OBS
    LAYER M1 ;
    RECT 0 0 138.320 43.400 ;
    LAYER M2 ;
    RECT 0 0 138.320 43.400 ;
    LAYER M3 ;
    RECT 0 0 138.320 43.400 ;
    LAYER M4 ;
    RECT 0 0 138.320 43.400 ;
  END
END fakeram_64x512

END LIBRARY
